VERSION 5.8 ;
BUSBITCHARS "[]" ;
DIVIDERCHAR "/" ;
UNITS
    DATABASE MICRONS 1000 ;
END UNITS

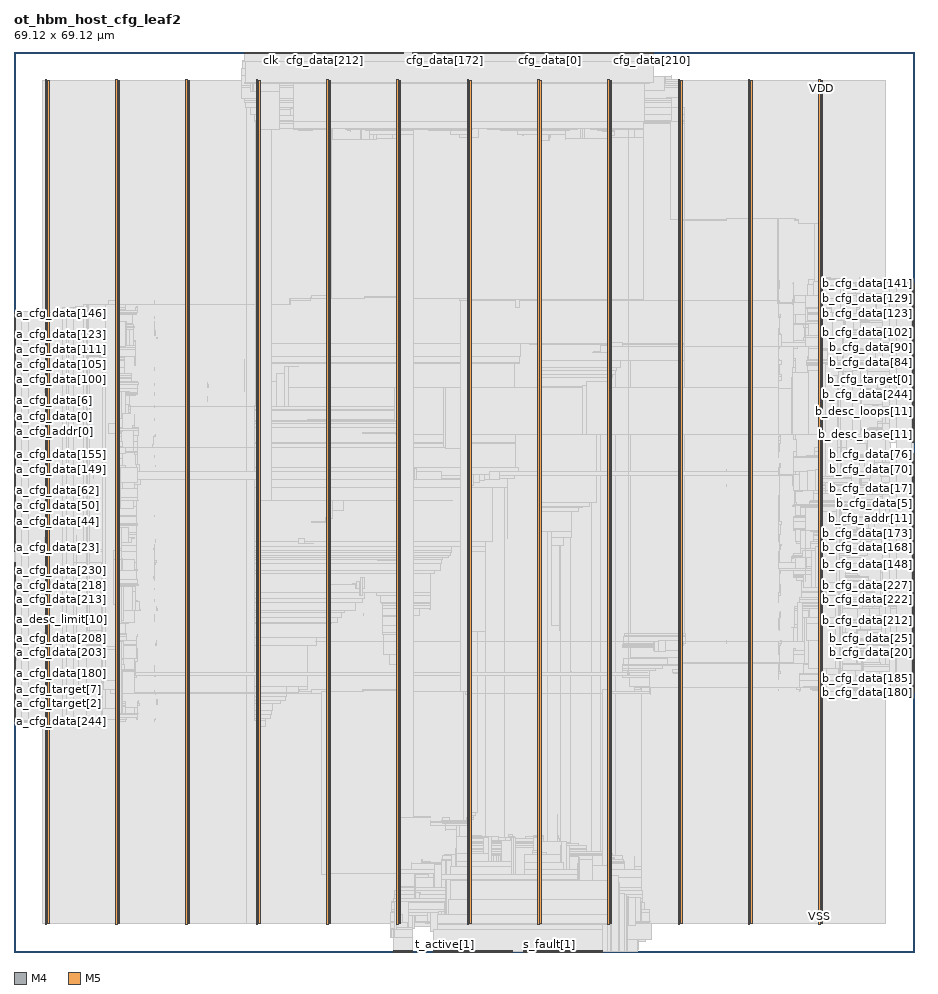
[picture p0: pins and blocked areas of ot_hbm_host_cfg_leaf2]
MACRO ot_hbm_host_cfg_leaf2
  FOREIGN ot_hbm_host_cfg_leaf2 0 0 ;
  CLASS BLOCK ;
  SIZE 69.12 BY 69.12 ;
  PIN a_cfg_addr[0]
    DIRECTION OUTPUT ;
    USE SIGNAL ;
    PORT
      LAYER M4 ;
        RECT  0 39.984 0.084 40.008 ;
    END
  END a_cfg_addr[0]
  PIN a_cfg_addr[10]
    DIRECTION OUTPUT ;
    USE SIGNAL ;
    PORT
      LAYER M4 ;
        RECT  0 40.944 0.084 40.968 ;
    END
  END a_cfg_addr[10]
  PIN a_cfg_addr[11]
    DIRECTION OUTPUT ;
    USE SIGNAL ;
    PORT
      LAYER M4 ;
        RECT  0 41.04 0.084 41.064 ;
    END
  END a_cfg_addr[11]
  PIN a_cfg_addr[1]
    DIRECTION OUTPUT ;
    USE SIGNAL ;
    PORT
      LAYER M4 ;
        RECT  0 40.08 0.084 40.104 ;
    END
  END a_cfg_addr[1]
  PIN a_cfg_addr[2]
    DIRECTION OUTPUT ;
    USE SIGNAL ;
    PORT
      LAYER M4 ;
        RECT  0 40.176 0.084 40.2 ;
    END
  END a_cfg_addr[2]
  PIN a_cfg_addr[3]
    DIRECTION OUTPUT ;
    USE SIGNAL ;
    PORT
      LAYER M4 ;
        RECT  0 40.272 0.084 40.296 ;
    END
  END a_cfg_addr[3]
  PIN a_cfg_addr[4]
    DIRECTION OUTPUT ;
    USE SIGNAL ;
    PORT
      LAYER M4 ;
        RECT  0 40.368 0.084 40.392 ;
    END
  END a_cfg_addr[4]
  PIN a_cfg_addr[5]
    DIRECTION OUTPUT ;
    USE SIGNAL ;
    PORT
      LAYER M4 ;
        RECT  0 40.464 0.084 40.488 ;
    END
  END a_cfg_addr[5]
  PIN a_cfg_addr[6]
    DIRECTION OUTPUT ;
    USE SIGNAL ;
    PORT
      LAYER M4 ;
        RECT  0 40.56 0.084 40.584 ;
    END
  END a_cfg_addr[6]
  PIN a_cfg_addr[7]
    DIRECTION OUTPUT ;
    USE SIGNAL ;
    PORT
      LAYER M4 ;
        RECT  0 40.656 0.084 40.68 ;
    END
  END a_cfg_addr[7]
  PIN a_cfg_addr[8]
    DIRECTION OUTPUT ;
    USE SIGNAL ;
    PORT
      LAYER M4 ;
        RECT  0 40.752 0.084 40.776 ;
    END
  END a_cfg_addr[8]
  PIN a_cfg_addr[9]
    DIRECTION OUTPUT ;
    USE SIGNAL ;
    PORT
      LAYER M4 ;
        RECT  0 40.848 0.084 40.872 ;
    END
  END a_cfg_addr[9]
  PIN a_cfg_data[0]
    DIRECTION OUTPUT ;
    USE SIGNAL ;
    PORT
      LAYER M4 ;
        RECT  0 41.136 0.084 41.16 ;
    END
  END a_cfg_data[0]
  PIN a_cfg_data[100]
    DIRECTION OUTPUT ;
    USE SIGNAL ;
    PORT
      LAYER M4 ;
        RECT  0 44.592 0.084 44.616 ;
    END
  END a_cfg_data[100]
  PIN a_cfg_data[101]
    DIRECTION OUTPUT ;
    USE SIGNAL ;
    PORT
      LAYER M4 ;
        RECT  0 44.688 0.084 44.712 ;
    END
  END a_cfg_data[101]
  PIN a_cfg_data[102]
    DIRECTION OUTPUT ;
    USE SIGNAL ;
    PORT
      LAYER M4 ;
        RECT  0 44.784 0.084 44.808 ;
    END
  END a_cfg_data[102]
  PIN a_cfg_data[103]
    DIRECTION OUTPUT ;
    USE SIGNAL ;
    PORT
      LAYER M4 ;
        RECT  0 44.88 0.084 44.904 ;
    END
  END a_cfg_data[103]
  PIN a_cfg_data[104]
    DIRECTION OUTPUT ;
    USE SIGNAL ;
    PORT
      LAYER M4 ;
        RECT  0 44.976 0.084 45 ;
    END
  END a_cfg_data[104]
  PIN a_cfg_data[105]
    DIRECTION OUTPUT ;
    USE SIGNAL ;
    PORT
      LAYER M4 ;
        RECT  0 45.072 0.084 45.096 ;
    END
  END a_cfg_data[105]
  PIN a_cfg_data[106]
    DIRECTION OUTPUT ;
    USE SIGNAL ;
    PORT
      LAYER M4 ;
        RECT  0 45.168 0.084 45.192 ;
    END
  END a_cfg_data[106]
  PIN a_cfg_data[107]
    DIRECTION OUTPUT ;
    USE SIGNAL ;
    PORT
      LAYER M4 ;
        RECT  0 45.264 0.084 45.288 ;
    END
  END a_cfg_data[107]
  PIN a_cfg_data[108]
    DIRECTION OUTPUT ;
    USE SIGNAL ;
    PORT
      LAYER M4 ;
        RECT  0 45.36 0.084 45.384 ;
    END
  END a_cfg_data[108]
  PIN a_cfg_data[109]
    DIRECTION OUTPUT ;
    USE SIGNAL ;
    PORT
      LAYER M4 ;
        RECT  0 45.456 0.084 45.48 ;
    END
  END a_cfg_data[109]
  PIN a_cfg_data[10]
    DIRECTION OUTPUT ;
    USE SIGNAL ;
    PORT
      LAYER M4 ;
        RECT  0 42.096 0.084 42.12 ;
    END
  END a_cfg_data[10]
  PIN a_cfg_data[110]
    DIRECTION OUTPUT ;
    USE SIGNAL ;
    PORT
      LAYER M4 ;
        RECT  0 45.552 0.084 45.576 ;
    END
  END a_cfg_data[110]
  PIN a_cfg_data[111]
    DIRECTION OUTPUT ;
    USE SIGNAL ;
    PORT
      LAYER M4 ;
        RECT  0 45.648 0.084 45.672 ;
    END
  END a_cfg_data[111]
  PIN a_cfg_data[112]
    DIRECTION OUTPUT ;
    USE SIGNAL ;
    PORT
      LAYER M4 ;
        RECT  0 45.744 0.084 45.768 ;
    END
  END a_cfg_data[112]
  PIN a_cfg_data[113]
    DIRECTION OUTPUT ;
    USE SIGNAL ;
    PORT
      LAYER M4 ;
        RECT  0 45.84 0.084 45.864 ;
    END
  END a_cfg_data[113]
  PIN a_cfg_data[114]
    DIRECTION OUTPUT ;
    USE SIGNAL ;
    PORT
      LAYER M4 ;
        RECT  0 45.936 0.084 45.96 ;
    END
  END a_cfg_data[114]
  PIN a_cfg_data[115]
    DIRECTION OUTPUT ;
    USE SIGNAL ;
    PORT
      LAYER M4 ;
        RECT  0 46.032 0.084 46.056 ;
    END
  END a_cfg_data[115]
  PIN a_cfg_data[116]
    DIRECTION OUTPUT ;
    USE SIGNAL ;
    PORT
      LAYER M4 ;
        RECT  0 46.128 0.084 46.152 ;
    END
  END a_cfg_data[116]
  PIN a_cfg_data[117]
    DIRECTION OUTPUT ;
    USE SIGNAL ;
    PORT
      LAYER M4 ;
        RECT  0 46.224 0.084 46.248 ;
    END
  END a_cfg_data[117]
  PIN a_cfg_data[118]
    DIRECTION OUTPUT ;
    USE SIGNAL ;
    PORT
      LAYER M4 ;
        RECT  0 46.32 0.084 46.344 ;
    END
  END a_cfg_data[118]
  PIN a_cfg_data[119]
    DIRECTION OUTPUT ;
    USE SIGNAL ;
    PORT
      LAYER M4 ;
        RECT  0 46.416 0.084 46.44 ;
    END
  END a_cfg_data[119]
  PIN a_cfg_data[11]
    DIRECTION OUTPUT ;
    USE SIGNAL ;
    PORT
      LAYER M4 ;
        RECT  0 42.192 0.084 42.216 ;
    END
  END a_cfg_data[11]
  PIN a_cfg_data[120]
    DIRECTION OUTPUT ;
    USE SIGNAL ;
    PORT
      LAYER M4 ;
        RECT  0 46.512 0.084 46.536 ;
    END
  END a_cfg_data[120]
  PIN a_cfg_data[121]
    DIRECTION OUTPUT ;
    USE SIGNAL ;
    PORT
      LAYER M4 ;
        RECT  0 46.608 0.084 46.632 ;
    END
  END a_cfg_data[121]
  PIN a_cfg_data[122]
    DIRECTION OUTPUT ;
    USE SIGNAL ;
    PORT
      LAYER M4 ;
        RECT  0 46.704 0.084 46.728 ;
    END
  END a_cfg_data[122]
  PIN a_cfg_data[123]
    DIRECTION OUTPUT ;
    USE SIGNAL ;
    PORT
      LAYER M4 ;
        RECT  0 46.8 0.084 46.824 ;
    END
  END a_cfg_data[123]
  PIN a_cfg_data[124]
    DIRECTION OUTPUT ;
    USE SIGNAL ;
    PORT
      LAYER M4 ;
        RECT  0 46.896 0.084 46.92 ;
    END
  END a_cfg_data[124]
  PIN a_cfg_data[125]
    DIRECTION OUTPUT ;
    USE SIGNAL ;
    PORT
      LAYER M4 ;
        RECT  0 46.992 0.084 47.016 ;
    END
  END a_cfg_data[125]
  PIN a_cfg_data[126]
    DIRECTION OUTPUT ;
    USE SIGNAL ;
    PORT
      LAYER M4 ;
        RECT  0 47.088 0.084 47.112 ;
    END
  END a_cfg_data[126]
  PIN a_cfg_data[127]
    DIRECTION OUTPUT ;
    USE SIGNAL ;
    PORT
      LAYER M4 ;
        RECT  0 47.184 0.084 47.208 ;
    END
  END a_cfg_data[127]
  PIN a_cfg_data[128]
    DIRECTION OUTPUT ;
    USE SIGNAL ;
    PORT
      LAYER M4 ;
        RECT  0 47.28 0.084 47.304 ;
    END
  END a_cfg_data[128]
  PIN a_cfg_data[129]
    DIRECTION OUTPUT ;
    USE SIGNAL ;
    PORT
      LAYER M4 ;
        RECT  0 47.376 0.084 47.4 ;
    END
  END a_cfg_data[129]
  PIN a_cfg_data[12]
    DIRECTION OUTPUT ;
    USE SIGNAL ;
    PORT
      LAYER M4 ;
        RECT  0 42.288 0.084 42.312 ;
    END
  END a_cfg_data[12]
  PIN a_cfg_data[130]
    DIRECTION OUTPUT ;
    USE SIGNAL ;
    PORT
      LAYER M4 ;
        RECT  0 47.472 0.084 47.496 ;
    END
  END a_cfg_data[130]
  PIN a_cfg_data[131]
    DIRECTION OUTPUT ;
    USE SIGNAL ;
    PORT
      LAYER M4 ;
        RECT  0 47.568 0.084 47.592 ;
    END
  END a_cfg_data[131]
  PIN a_cfg_data[132]
    DIRECTION OUTPUT ;
    USE SIGNAL ;
    PORT
      LAYER M4 ;
        RECT  0 47.664 0.084 47.688 ;
    END
  END a_cfg_data[132]
  PIN a_cfg_data[133]
    DIRECTION OUTPUT ;
    USE SIGNAL ;
    PORT
      LAYER M4 ;
        RECT  0 47.76 0.084 47.784 ;
    END
  END a_cfg_data[133]
  PIN a_cfg_data[134]
    DIRECTION OUTPUT ;
    USE SIGNAL ;
    PORT
      LAYER M4 ;
        RECT  0 47.856 0.084 47.88 ;
    END
  END a_cfg_data[134]
  PIN a_cfg_data[135]
    DIRECTION OUTPUT ;
    USE SIGNAL ;
    PORT
      LAYER M4 ;
        RECT  0 47.952 0.084 47.976 ;
    END
  END a_cfg_data[135]
  PIN a_cfg_data[136]
    DIRECTION OUTPUT ;
    USE SIGNAL ;
    PORT
      LAYER M4 ;
        RECT  0 48.048 0.084 48.072 ;
    END
  END a_cfg_data[136]
  PIN a_cfg_data[137]
    DIRECTION OUTPUT ;
    USE SIGNAL ;
    PORT
      LAYER M4 ;
        RECT  0 48.144 0.084 48.168 ;
    END
  END a_cfg_data[137]
  PIN a_cfg_data[138]
    DIRECTION OUTPUT ;
    USE SIGNAL ;
    PORT
      LAYER M4 ;
        RECT  0 48.24 0.084 48.264 ;
    END
  END a_cfg_data[138]
  PIN a_cfg_data[139]
    DIRECTION OUTPUT ;
    USE SIGNAL ;
    PORT
      LAYER M4 ;
        RECT  0 48.336 0.084 48.36 ;
    END
  END a_cfg_data[139]
  PIN a_cfg_data[13]
    DIRECTION OUTPUT ;
    USE SIGNAL ;
    PORT
      LAYER M4 ;
        RECT  0 42.384 0.084 42.408 ;
    END
  END a_cfg_data[13]
  PIN a_cfg_data[140]
    DIRECTION OUTPUT ;
    USE SIGNAL ;
    PORT
      LAYER M4 ;
        RECT  0 48.432 0.084 48.456 ;
    END
  END a_cfg_data[140]
  PIN a_cfg_data[141]
    DIRECTION OUTPUT ;
    USE SIGNAL ;
    PORT
      LAYER M4 ;
        RECT  0 48.528 0.084 48.552 ;
    END
  END a_cfg_data[141]
  PIN a_cfg_data[142]
    DIRECTION OUTPUT ;
    USE SIGNAL ;
    PORT
      LAYER M4 ;
        RECT  0 48.624 0.084 48.648 ;
    END
  END a_cfg_data[142]
  PIN a_cfg_data[143]
    DIRECTION OUTPUT ;
    USE SIGNAL ;
    PORT
      LAYER M4 ;
        RECT  0 48.72 0.084 48.744 ;
    END
  END a_cfg_data[143]
  PIN a_cfg_data[144]
    DIRECTION OUTPUT ;
    USE SIGNAL ;
    PORT
      LAYER M4 ;
        RECT  0 48.816 0.084 48.84 ;
    END
  END a_cfg_data[144]
  PIN a_cfg_data[145]
    DIRECTION OUTPUT ;
    USE SIGNAL ;
    PORT
      LAYER M4 ;
        RECT  0 48.912 0.084 48.936 ;
    END
  END a_cfg_data[145]
  PIN a_cfg_data[146]
    DIRECTION OUTPUT ;
    USE SIGNAL ;
    PORT
      LAYER M4 ;
        RECT  0 49.008 0.084 49.032 ;
    END
  END a_cfg_data[146]
  PIN a_cfg_data[147]
    DIRECTION OUTPUT ;
    USE SIGNAL ;
    PORT
      LAYER M4 ;
        RECT  0 49.104 0.084 49.128 ;
    END
  END a_cfg_data[147]
  PIN a_cfg_data[148]
    DIRECTION OUTPUT ;
    USE SIGNAL ;
    PORT
      LAYER M4 ;
        RECT  0 36.912 0.084 36.936 ;
    END
  END a_cfg_data[148]
  PIN a_cfg_data[149]
    DIRECTION OUTPUT ;
    USE SIGNAL ;
    PORT
      LAYER M4 ;
        RECT  0 37.008 0.084 37.032 ;
    END
  END a_cfg_data[149]
  PIN a_cfg_data[14]
    DIRECTION OUTPUT ;
    USE SIGNAL ;
    PORT
      LAYER M4 ;
        RECT  0 42.48 0.084 42.504 ;
    END
  END a_cfg_data[14]
  PIN a_cfg_data[150]
    DIRECTION OUTPUT ;
    USE SIGNAL ;
    PORT
      LAYER M4 ;
        RECT  0 37.104 0.084 37.128 ;
    END
  END a_cfg_data[150]
  PIN a_cfg_data[151]
    DIRECTION OUTPUT ;
    USE SIGNAL ;
    PORT
      LAYER M4 ;
        RECT  0 37.2 0.084 37.224 ;
    END
  END a_cfg_data[151]
  PIN a_cfg_data[152]
    DIRECTION OUTPUT ;
    USE SIGNAL ;
    PORT
      LAYER M4 ;
        RECT  0 37.296 0.084 37.32 ;
    END
  END a_cfg_data[152]
  PIN a_cfg_data[153]
    DIRECTION OUTPUT ;
    USE SIGNAL ;
    PORT
      LAYER M4 ;
        RECT  0 37.392 0.084 37.416 ;
    END
  END a_cfg_data[153]
  PIN a_cfg_data[154]
    DIRECTION OUTPUT ;
    USE SIGNAL ;
    PORT
      LAYER M4 ;
        RECT  0 37.488 0.084 37.512 ;
    END
  END a_cfg_data[154]
  PIN a_cfg_data[155]
    DIRECTION OUTPUT ;
    USE SIGNAL ;
    PORT
      LAYER M4 ;
        RECT  0 37.584 0.084 37.608 ;
    END
  END a_cfg_data[155]
  PIN a_cfg_data[156]
    DIRECTION OUTPUT ;
    USE SIGNAL ;
    PORT
      LAYER M4 ;
        RECT  0 37.68 0.084 37.704 ;
    END
  END a_cfg_data[156]
  PIN a_cfg_data[157]
    DIRECTION OUTPUT ;
    USE SIGNAL ;
    PORT
      LAYER M4 ;
        RECT  0 37.776 0.084 37.8 ;
    END
  END a_cfg_data[157]
  PIN a_cfg_data[158]
    DIRECTION OUTPUT ;
    USE SIGNAL ;
    PORT
      LAYER M4 ;
        RECT  0 37.872 0.084 37.896 ;
    END
  END a_cfg_data[158]
  PIN a_cfg_data[159]
    DIRECTION OUTPUT ;
    USE SIGNAL ;
    PORT
      LAYER M4 ;
        RECT  0 37.968 0.084 37.992 ;
    END
  END a_cfg_data[159]
  PIN a_cfg_data[15]
    DIRECTION OUTPUT ;
    USE SIGNAL ;
    PORT
      LAYER M4 ;
        RECT  0 42.576 0.084 42.6 ;
    END
  END a_cfg_data[15]
  PIN a_cfg_data[160]
    DIRECTION OUTPUT ;
    USE SIGNAL ;
    PORT
      LAYER M4 ;
        RECT  0 38.064 0.084 38.088 ;
    END
  END a_cfg_data[160]
  PIN a_cfg_data[161]
    DIRECTION OUTPUT ;
    USE SIGNAL ;
    PORT
      LAYER M4 ;
        RECT  0 38.16 0.084 38.184 ;
    END
  END a_cfg_data[161]
  PIN a_cfg_data[162]
    DIRECTION OUTPUT ;
    USE SIGNAL ;
    PORT
      LAYER M4 ;
        RECT  0 38.256 0.084 38.28 ;
    END
  END a_cfg_data[162]
  PIN a_cfg_data[163]
    DIRECTION OUTPUT ;
    USE SIGNAL ;
    PORT
      LAYER M4 ;
        RECT  0 38.352 0.084 38.376 ;
    END
  END a_cfg_data[163]
  PIN a_cfg_data[164]
    DIRECTION OUTPUT ;
    USE SIGNAL ;
    PORT
      LAYER M4 ;
        RECT  0 38.448 0.084 38.472 ;
    END
  END a_cfg_data[164]
  PIN a_cfg_data[165]
    DIRECTION OUTPUT ;
    USE SIGNAL ;
    PORT
      LAYER M4 ;
        RECT  0 38.544 0.084 38.568 ;
    END
  END a_cfg_data[165]
  PIN a_cfg_data[166]
    DIRECTION OUTPUT ;
    USE SIGNAL ;
    PORT
      LAYER M4 ;
        RECT  0 38.64 0.084 38.664 ;
    END
  END a_cfg_data[166]
  PIN a_cfg_data[167]
    DIRECTION OUTPUT ;
    USE SIGNAL ;
    PORT
      LAYER M4 ;
        RECT  0 38.736 0.084 38.76 ;
    END
  END a_cfg_data[167]
  PIN a_cfg_data[168]
    DIRECTION OUTPUT ;
    USE SIGNAL ;
    PORT
      LAYER M4 ;
        RECT  0 38.832 0.084 38.856 ;
    END
  END a_cfg_data[168]
  PIN a_cfg_data[169]
    DIRECTION OUTPUT ;
    USE SIGNAL ;
    PORT
      LAYER M4 ;
        RECT  0 38.928 0.084 38.952 ;
    END
  END a_cfg_data[169]
  PIN a_cfg_data[16]
    DIRECTION OUTPUT ;
    USE SIGNAL ;
    PORT
      LAYER M4 ;
        RECT  0 42.672 0.084 42.696 ;
    END
  END a_cfg_data[16]
  PIN a_cfg_data[170]
    DIRECTION OUTPUT ;
    USE SIGNAL ;
    PORT
      LAYER M4 ;
        RECT  0 39.024 0.084 39.048 ;
    END
  END a_cfg_data[170]
  PIN a_cfg_data[171]
    DIRECTION OUTPUT ;
    USE SIGNAL ;
    PORT
      LAYER M4 ;
        RECT  0 39.12 0.084 39.144 ;
    END
  END a_cfg_data[171]
  PIN a_cfg_data[172]
    DIRECTION OUTPUT ;
    USE SIGNAL ;
    PORT
      LAYER M4 ;
        RECT  0 39.216 0.084 39.24 ;
    END
  END a_cfg_data[172]
  PIN a_cfg_data[173]
    DIRECTION OUTPUT ;
    USE SIGNAL ;
    PORT
      LAYER M4 ;
        RECT  0 39.312 0.084 39.336 ;
    END
  END a_cfg_data[173]
  PIN a_cfg_data[174]
    DIRECTION OUTPUT ;
    USE SIGNAL ;
    PORT
      LAYER M4 ;
        RECT  0 39.408 0.084 39.432 ;
    END
  END a_cfg_data[174]
  PIN a_cfg_data[175]
    DIRECTION OUTPUT ;
    USE SIGNAL ;
    PORT
      LAYER M4 ;
        RECT  0 39.504 0.084 39.528 ;
    END
  END a_cfg_data[175]
  PIN a_cfg_data[176]
    DIRECTION OUTPUT ;
    USE SIGNAL ;
    PORT
      LAYER M4 ;
        RECT  0 39.6 0.084 39.624 ;
    END
  END a_cfg_data[176]
  PIN a_cfg_data[177]
    DIRECTION OUTPUT ;
    USE SIGNAL ;
    PORT
      LAYER M4 ;
        RECT  0 39.696 0.084 39.72 ;
    END
  END a_cfg_data[177]
  PIN a_cfg_data[178]
    DIRECTION OUTPUT ;
    USE SIGNAL ;
    PORT
      LAYER M4 ;
        RECT  0 39.792 0.084 39.816 ;
    END
  END a_cfg_data[178]
  PIN a_cfg_data[179]
    DIRECTION OUTPUT ;
    USE SIGNAL ;
    PORT
      LAYER M4 ;
        RECT  0 39.888 0.084 39.912 ;
    END
  END a_cfg_data[179]
  PIN a_cfg_data[17]
    DIRECTION OUTPUT ;
    USE SIGNAL ;
    PORT
      LAYER M4 ;
        RECT  0 42.768 0.084 42.792 ;
    END
  END a_cfg_data[17]
  PIN a_cfg_data[180]
    DIRECTION OUTPUT ;
    USE SIGNAL ;
    PORT
      LAYER M4 ;
        RECT  0 20.784 0.084 20.808 ;
    END
  END a_cfg_data[180]
  PIN a_cfg_data[181]
    DIRECTION OUTPUT ;
    USE SIGNAL ;
    PORT
      LAYER M4 ;
        RECT  0 20.88 0.084 20.904 ;
    END
  END a_cfg_data[181]
  PIN a_cfg_data[182]
    DIRECTION OUTPUT ;
    USE SIGNAL ;
    PORT
      LAYER M4 ;
        RECT  0 20.976 0.084 21 ;
    END
  END a_cfg_data[182]
  PIN a_cfg_data[183]
    DIRECTION OUTPUT ;
    USE SIGNAL ;
    PORT
      LAYER M4 ;
        RECT  0 21.072 0.084 21.096 ;
    END
  END a_cfg_data[183]
  PIN a_cfg_data[184]
    DIRECTION OUTPUT ;
    USE SIGNAL ;
    PORT
      LAYER M4 ;
        RECT  0 21.168 0.084 21.192 ;
    END
  END a_cfg_data[184]
  PIN a_cfg_data[185]
    DIRECTION OUTPUT ;
    USE SIGNAL ;
    PORT
      LAYER M4 ;
        RECT  0 21.264 0.084 21.288 ;
    END
  END a_cfg_data[185]
  PIN a_cfg_data[186]
    DIRECTION OUTPUT ;
    USE SIGNAL ;
    PORT
      LAYER M4 ;
        RECT  0 21.36 0.084 21.384 ;
    END
  END a_cfg_data[186]
  PIN a_cfg_data[187]
    DIRECTION OUTPUT ;
    USE SIGNAL ;
    PORT
      LAYER M4 ;
        RECT  0 21.456 0.084 21.48 ;
    END
  END a_cfg_data[187]
  PIN a_cfg_data[188]
    DIRECTION OUTPUT ;
    USE SIGNAL ;
    PORT
      LAYER M4 ;
        RECT  0 21.552 0.084 21.576 ;
    END
  END a_cfg_data[188]
  PIN a_cfg_data[189]
    DIRECTION OUTPUT ;
    USE SIGNAL ;
    PORT
      LAYER M4 ;
        RECT  0 21.648 0.084 21.672 ;
    END
  END a_cfg_data[189]
  PIN a_cfg_data[18]
    DIRECTION OUTPUT ;
    USE SIGNAL ;
    PORT
      LAYER M4 ;
        RECT  0 42.864 0.084 42.888 ;
    END
  END a_cfg_data[18]
  PIN a_cfg_data[190]
    DIRECTION OUTPUT ;
    USE SIGNAL ;
    PORT
      LAYER M4 ;
        RECT  0 21.744 0.084 21.768 ;
    END
  END a_cfg_data[190]
  PIN a_cfg_data[191]
    DIRECTION OUTPUT ;
    USE SIGNAL ;
    PORT
      LAYER M4 ;
        RECT  0 21.84 0.084 21.864 ;
    END
  END a_cfg_data[191]
  PIN a_cfg_data[192]
    DIRECTION OUTPUT ;
    USE SIGNAL ;
    PORT
      LAYER M4 ;
        RECT  0 21.936 0.084 21.96 ;
    END
  END a_cfg_data[192]
  PIN a_cfg_data[193]
    DIRECTION OUTPUT ;
    USE SIGNAL ;
    PORT
      LAYER M4 ;
        RECT  0 22.032 0.084 22.056 ;
    END
  END a_cfg_data[193]
  PIN a_cfg_data[194]
    DIRECTION OUTPUT ;
    USE SIGNAL ;
    PORT
      LAYER M4 ;
        RECT  0 22.128 0.084 22.152 ;
    END
  END a_cfg_data[194]
  PIN a_cfg_data[195]
    DIRECTION OUTPUT ;
    USE SIGNAL ;
    PORT
      LAYER M4 ;
        RECT  0 22.224 0.084 22.248 ;
    END
  END a_cfg_data[195]
  PIN a_cfg_data[196]
    DIRECTION OUTPUT ;
    USE SIGNAL ;
    PORT
      LAYER M4 ;
        RECT  0 22.32 0.084 22.344 ;
    END
  END a_cfg_data[196]
  PIN a_cfg_data[197]
    DIRECTION OUTPUT ;
    USE SIGNAL ;
    PORT
      LAYER M4 ;
        RECT  0 22.416 0.084 22.44 ;
    END
  END a_cfg_data[197]
  PIN a_cfg_data[198]
    DIRECTION OUTPUT ;
    USE SIGNAL ;
    PORT
      LAYER M4 ;
        RECT  0 22.512 0.084 22.536 ;
    END
  END a_cfg_data[198]
  PIN a_cfg_data[199]
    DIRECTION OUTPUT ;
    USE SIGNAL ;
    PORT
      LAYER M4 ;
        RECT  0 22.608 0.084 22.632 ;
    END
  END a_cfg_data[199]
  PIN a_cfg_data[19]
    DIRECTION OUTPUT ;
    USE SIGNAL ;
    PORT
      LAYER M4 ;
        RECT  0 42.96 0.084 42.984 ;
    END
  END a_cfg_data[19]
  PIN a_cfg_data[1]
    DIRECTION OUTPUT ;
    USE SIGNAL ;
    PORT
      LAYER M4 ;
        RECT  0 41.232 0.084 41.256 ;
    END
  END a_cfg_data[1]
  PIN a_cfg_data[200]
    DIRECTION OUTPUT ;
    USE SIGNAL ;
    PORT
      LAYER M4 ;
        RECT  0 22.704 0.084 22.728 ;
    END
  END a_cfg_data[200]
  PIN a_cfg_data[201]
    DIRECTION OUTPUT ;
    USE SIGNAL ;
    PORT
      LAYER M4 ;
        RECT  0 22.8 0.084 22.824 ;
    END
  END a_cfg_data[201]
  PIN a_cfg_data[202]
    DIRECTION OUTPUT ;
    USE SIGNAL ;
    PORT
      LAYER M4 ;
        RECT  0 22.896 0.084 22.92 ;
    END
  END a_cfg_data[202]
  PIN a_cfg_data[203]
    DIRECTION OUTPUT ;
    USE SIGNAL ;
    PORT
      LAYER M4 ;
        RECT  0 22.992 0.084 23.016 ;
    END
  END a_cfg_data[203]
  PIN a_cfg_data[204]
    DIRECTION OUTPUT ;
    USE SIGNAL ;
    PORT
      LAYER M4 ;
        RECT  0 23.088 0.084 23.112 ;
    END
  END a_cfg_data[204]
  PIN a_cfg_data[205]
    DIRECTION OUTPUT ;
    USE SIGNAL ;
    PORT
      LAYER M4 ;
        RECT  0 23.184 0.084 23.208 ;
    END
  END a_cfg_data[205]
  PIN a_cfg_data[206]
    DIRECTION OUTPUT ;
    USE SIGNAL ;
    PORT
      LAYER M4 ;
        RECT  0 23.28 0.084 23.304 ;
    END
  END a_cfg_data[206]
  PIN a_cfg_data[207]
    DIRECTION OUTPUT ;
    USE SIGNAL ;
    PORT
      LAYER M4 ;
        RECT  0 23.376 0.084 23.4 ;
    END
  END a_cfg_data[207]
  PIN a_cfg_data[208]
    DIRECTION OUTPUT ;
    USE SIGNAL ;
    PORT
      LAYER M4 ;
        RECT  0 23.472 0.084 23.496 ;
    END
  END a_cfg_data[208]
  PIN a_cfg_data[209]
    DIRECTION OUTPUT ;
    USE SIGNAL ;
    PORT
      LAYER M4 ;
        RECT  0 23.568 0.084 23.592 ;
    END
  END a_cfg_data[209]
  PIN a_cfg_data[20]
    DIRECTION OUTPUT ;
    USE SIGNAL ;
    PORT
      LAYER M4 ;
        RECT  0 30.768 0.084 30.792 ;
    END
  END a_cfg_data[20]
  PIN a_cfg_data[210]
    DIRECTION OUTPUT ;
    USE SIGNAL ;
    PORT
      LAYER M4 ;
        RECT  0 23.664 0.084 23.688 ;
    END
  END a_cfg_data[210]
  PIN a_cfg_data[211]
    DIRECTION OUTPUT ;
    USE SIGNAL ;
    PORT
      LAYER M4 ;
        RECT  0 23.76 0.084 23.784 ;
    END
  END a_cfg_data[211]
  PIN a_cfg_data[212]
    DIRECTION OUTPUT ;
    USE SIGNAL ;
    PORT
      LAYER M4 ;
        RECT  0 26.928 0.084 26.952 ;
    END
  END a_cfg_data[212]
  PIN a_cfg_data[213]
    DIRECTION OUTPUT ;
    USE SIGNAL ;
    PORT
      LAYER M4 ;
        RECT  0 27.024 0.084 27.048 ;
    END
  END a_cfg_data[213]
  PIN a_cfg_data[214]
    DIRECTION OUTPUT ;
    USE SIGNAL ;
    PORT
      LAYER M4 ;
        RECT  0 27.12 0.084 27.144 ;
    END
  END a_cfg_data[214]
  PIN a_cfg_data[215]
    DIRECTION OUTPUT ;
    USE SIGNAL ;
    PORT
      LAYER M4 ;
        RECT  0 27.216 0.084 27.24 ;
    END
  END a_cfg_data[215]
  PIN a_cfg_data[216]
    DIRECTION OUTPUT ;
    USE SIGNAL ;
    PORT
      LAYER M4 ;
        RECT  0 27.312 0.084 27.336 ;
    END
  END a_cfg_data[216]
  PIN a_cfg_data[217]
    DIRECTION OUTPUT ;
    USE SIGNAL ;
    PORT
      LAYER M4 ;
        RECT  0 27.408 0.084 27.432 ;
    END
  END a_cfg_data[217]
  PIN a_cfg_data[218]
    DIRECTION OUTPUT ;
    USE SIGNAL ;
    PORT
      LAYER M4 ;
        RECT  0 27.504 0.084 27.528 ;
    END
  END a_cfg_data[218]
  PIN a_cfg_data[219]
    DIRECTION OUTPUT ;
    USE SIGNAL ;
    PORT
      LAYER M4 ;
        RECT  0 27.6 0.084 27.624 ;
    END
  END a_cfg_data[219]
  PIN a_cfg_data[21]
    DIRECTION OUTPUT ;
    USE SIGNAL ;
    PORT
      LAYER M4 ;
        RECT  0 30.864 0.084 30.888 ;
    END
  END a_cfg_data[21]
  PIN a_cfg_data[220]
    DIRECTION OUTPUT ;
    USE SIGNAL ;
    PORT
      LAYER M4 ;
        RECT  0 27.696 0.084 27.72 ;
    END
  END a_cfg_data[220]
  PIN a_cfg_data[221]
    DIRECTION OUTPUT ;
    USE SIGNAL ;
    PORT
      LAYER M4 ;
        RECT  0 27.792 0.084 27.816 ;
    END
  END a_cfg_data[221]
  PIN a_cfg_data[222]
    DIRECTION OUTPUT ;
    USE SIGNAL ;
    PORT
      LAYER M4 ;
        RECT  0 27.888 0.084 27.912 ;
    END
  END a_cfg_data[222]
  PIN a_cfg_data[223]
    DIRECTION OUTPUT ;
    USE SIGNAL ;
    PORT
      LAYER M4 ;
        RECT  0 27.984 0.084 28.008 ;
    END
  END a_cfg_data[223]
  PIN a_cfg_data[224]
    DIRECTION OUTPUT ;
    USE SIGNAL ;
    PORT
      LAYER M4 ;
        RECT  0 28.08 0.084 28.104 ;
    END
  END a_cfg_data[224]
  PIN a_cfg_data[225]
    DIRECTION OUTPUT ;
    USE SIGNAL ;
    PORT
      LAYER M4 ;
        RECT  0 28.176 0.084 28.2 ;
    END
  END a_cfg_data[225]
  PIN a_cfg_data[226]
    DIRECTION OUTPUT ;
    USE SIGNAL ;
    PORT
      LAYER M4 ;
        RECT  0 28.272 0.084 28.296 ;
    END
  END a_cfg_data[226]
  PIN a_cfg_data[227]
    DIRECTION OUTPUT ;
    USE SIGNAL ;
    PORT
      LAYER M4 ;
        RECT  0 28.368 0.084 28.392 ;
    END
  END a_cfg_data[227]
  PIN a_cfg_data[228]
    DIRECTION OUTPUT ;
    USE SIGNAL ;
    PORT
      LAYER M4 ;
        RECT  0 28.464 0.084 28.488 ;
    END
  END a_cfg_data[228]
  PIN a_cfg_data[229]
    DIRECTION OUTPUT ;
    USE SIGNAL ;
    PORT
      LAYER M4 ;
        RECT  0 28.56 0.084 28.584 ;
    END
  END a_cfg_data[229]
  PIN a_cfg_data[22]
    DIRECTION OUTPUT ;
    USE SIGNAL ;
    PORT
      LAYER M4 ;
        RECT  0 30.96 0.084 30.984 ;
    END
  END a_cfg_data[22]
  PIN a_cfg_data[230]
    DIRECTION OUTPUT ;
    USE SIGNAL ;
    PORT
      LAYER M4 ;
        RECT  0 28.656 0.084 28.68 ;
    END
  END a_cfg_data[230]
  PIN a_cfg_data[231]
    DIRECTION OUTPUT ;
    USE SIGNAL ;
    PORT
      LAYER M4 ;
        RECT  0 28.752 0.084 28.776 ;
    END
  END a_cfg_data[231]
  PIN a_cfg_data[232]
    DIRECTION OUTPUT ;
    USE SIGNAL ;
    PORT
      LAYER M4 ;
        RECT  0 28.848 0.084 28.872 ;
    END
  END a_cfg_data[232]
  PIN a_cfg_data[233]
    DIRECTION OUTPUT ;
    USE SIGNAL ;
    PORT
      LAYER M4 ;
        RECT  0 28.944 0.084 28.968 ;
    END
  END a_cfg_data[233]
  PIN a_cfg_data[234]
    DIRECTION OUTPUT ;
    USE SIGNAL ;
    PORT
      LAYER M4 ;
        RECT  0 29.04 0.084 29.064 ;
    END
  END a_cfg_data[234]
  PIN a_cfg_data[235]
    DIRECTION OUTPUT ;
    USE SIGNAL ;
    PORT
      LAYER M4 ;
        RECT  0 29.136 0.084 29.16 ;
    END
  END a_cfg_data[235]
  PIN a_cfg_data[236]
    DIRECTION OUTPUT ;
    USE SIGNAL ;
    PORT
      LAYER M4 ;
        RECT  0 29.232 0.084 29.256 ;
    END
  END a_cfg_data[236]
  PIN a_cfg_data[237]
    DIRECTION OUTPUT ;
    USE SIGNAL ;
    PORT
      LAYER M4 ;
        RECT  0 29.328 0.084 29.352 ;
    END
  END a_cfg_data[237]
  PIN a_cfg_data[238]
    DIRECTION OUTPUT ;
    USE SIGNAL ;
    PORT
      LAYER M4 ;
        RECT  0 29.424 0.084 29.448 ;
    END
  END a_cfg_data[238]
  PIN a_cfg_data[239]
    DIRECTION OUTPUT ;
    USE SIGNAL ;
    PORT
      LAYER M4 ;
        RECT  0 29.52 0.084 29.544 ;
    END
  END a_cfg_data[239]
  PIN a_cfg_data[23]
    DIRECTION OUTPUT ;
    USE SIGNAL ;
    PORT
      LAYER M4 ;
        RECT  0 31.056 0.084 31.08 ;
    END
  END a_cfg_data[23]
  PIN a_cfg_data[240]
    DIRECTION OUTPUT ;
    USE SIGNAL ;
    PORT
      LAYER M4 ;
        RECT  0 29.616 0.084 29.64 ;
    END
  END a_cfg_data[240]
  PIN a_cfg_data[241]
    DIRECTION OUTPUT ;
    USE SIGNAL ;
    PORT
      LAYER M4 ;
        RECT  0 29.712 0.084 29.736 ;
    END
  END a_cfg_data[241]
  PIN a_cfg_data[242]
    DIRECTION OUTPUT ;
    USE SIGNAL ;
    PORT
      LAYER M4 ;
        RECT  0 29.808 0.084 29.832 ;
    END
  END a_cfg_data[242]
  PIN a_cfg_data[243]
    DIRECTION OUTPUT ;
    USE SIGNAL ;
    PORT
      LAYER M4 ;
        RECT  0 29.904 0.084 29.928 ;
    END
  END a_cfg_data[243]
  PIN a_cfg_data[244]
    DIRECTION OUTPUT ;
    USE SIGNAL ;
    PORT
      LAYER M4 ;
        RECT  0 17.712 0.084 17.736 ;
    END
  END a_cfg_data[244]
  PIN a_cfg_data[245]
    DIRECTION OUTPUT ;
    USE SIGNAL ;
    PORT
      LAYER M4 ;
        RECT  0 17.808 0.084 17.832 ;
    END
  END a_cfg_data[245]
  PIN a_cfg_data[246]
    DIRECTION OUTPUT ;
    USE SIGNAL ;
    PORT
      LAYER M4 ;
        RECT  0 17.904 0.084 17.928 ;
    END
  END a_cfg_data[246]
  PIN a_cfg_data[247]
    DIRECTION OUTPUT ;
    USE SIGNAL ;
    PORT
      LAYER M4 ;
        RECT  0 18 0.084 18.024 ;
    END
  END a_cfg_data[247]
  PIN a_cfg_data[248]
    DIRECTION OUTPUT ;
    USE SIGNAL ;
    PORT
      LAYER M4 ;
        RECT  0 18.096 0.084 18.12 ;
    END
  END a_cfg_data[248]
  PIN a_cfg_data[249]
    DIRECTION OUTPUT ;
    USE SIGNAL ;
    PORT
      LAYER M4 ;
        RECT  0 18.192 0.084 18.216 ;
    END
  END a_cfg_data[249]
  PIN a_cfg_data[24]
    DIRECTION OUTPUT ;
    USE SIGNAL ;
    PORT
      LAYER M4 ;
        RECT  0 31.152 0.084 31.176 ;
    END
  END a_cfg_data[24]
  PIN a_cfg_data[250]
    DIRECTION OUTPUT ;
    USE SIGNAL ;
    PORT
      LAYER M4 ;
        RECT  0 18.288 0.084 18.312 ;
    END
  END a_cfg_data[250]
  PIN a_cfg_data[251]
    DIRECTION OUTPUT ;
    USE SIGNAL ;
    PORT
      LAYER M4 ;
        RECT  0 18.384 0.084 18.408 ;
    END
  END a_cfg_data[251]
  PIN a_cfg_data[252]
    DIRECTION OUTPUT ;
    USE SIGNAL ;
    PORT
      LAYER M4 ;
        RECT  0 18.48 0.084 18.504 ;
    END
  END a_cfg_data[252]
  PIN a_cfg_data[253]
    DIRECTION OUTPUT ;
    USE SIGNAL ;
    PORT
      LAYER M4 ;
        RECT  0 18.576 0.084 18.6 ;
    END
  END a_cfg_data[253]
  PIN a_cfg_data[254]
    DIRECTION OUTPUT ;
    USE SIGNAL ;
    PORT
      LAYER M4 ;
        RECT  0 18.672 0.084 18.696 ;
    END
  END a_cfg_data[254]
  PIN a_cfg_data[255]
    DIRECTION OUTPUT ;
    USE SIGNAL ;
    PORT
      LAYER M4 ;
        RECT  0 18.768 0.084 18.792 ;
    END
  END a_cfg_data[255]
  PIN a_cfg_data[25]
    DIRECTION OUTPUT ;
    USE SIGNAL ;
    PORT
      LAYER M4 ;
        RECT  0 31.248 0.084 31.272 ;
    END
  END a_cfg_data[25]
  PIN a_cfg_data[26]
    DIRECTION OUTPUT ;
    USE SIGNAL ;
    PORT
      LAYER M4 ;
        RECT  0 31.344 0.084 31.368 ;
    END
  END a_cfg_data[26]
  PIN a_cfg_data[27]
    DIRECTION OUTPUT ;
    USE SIGNAL ;
    PORT
      LAYER M4 ;
        RECT  0 31.44 0.084 31.464 ;
    END
  END a_cfg_data[27]
  PIN a_cfg_data[28]
    DIRECTION OUTPUT ;
    USE SIGNAL ;
    PORT
      LAYER M4 ;
        RECT  0 31.536 0.084 31.56 ;
    END
  END a_cfg_data[28]
  PIN a_cfg_data[29]
    DIRECTION OUTPUT ;
    USE SIGNAL ;
    PORT
      LAYER M4 ;
        RECT  0 31.632 0.084 31.656 ;
    END
  END a_cfg_data[29]
  PIN a_cfg_data[2]
    DIRECTION OUTPUT ;
    USE SIGNAL ;
    PORT
      LAYER M4 ;
        RECT  0 41.328 0.084 41.352 ;
    END
  END a_cfg_data[2]
  PIN a_cfg_data[30]
    DIRECTION OUTPUT ;
    USE SIGNAL ;
    PORT
      LAYER M4 ;
        RECT  0 31.728 0.084 31.752 ;
    END
  END a_cfg_data[30]
  PIN a_cfg_data[31]
    DIRECTION OUTPUT ;
    USE SIGNAL ;
    PORT
      LAYER M4 ;
        RECT  0 31.824 0.084 31.848 ;
    END
  END a_cfg_data[31]
  PIN a_cfg_data[32]
    DIRECTION OUTPUT ;
    USE SIGNAL ;
    PORT
      LAYER M4 ;
        RECT  0 31.92 0.084 31.944 ;
    END
  END a_cfg_data[32]
  PIN a_cfg_data[33]
    DIRECTION OUTPUT ;
    USE SIGNAL ;
    PORT
      LAYER M4 ;
        RECT  0 32.016 0.084 32.04 ;
    END
  END a_cfg_data[33]
  PIN a_cfg_data[34]
    DIRECTION OUTPUT ;
    USE SIGNAL ;
    PORT
      LAYER M4 ;
        RECT  0 32.112 0.084 32.136 ;
    END
  END a_cfg_data[34]
  PIN a_cfg_data[35]
    DIRECTION OUTPUT ;
    USE SIGNAL ;
    PORT
      LAYER M4 ;
        RECT  0 32.208 0.084 32.232 ;
    END
  END a_cfg_data[35]
  PIN a_cfg_data[36]
    DIRECTION OUTPUT ;
    USE SIGNAL ;
    PORT
      LAYER M4 ;
        RECT  0 32.304 0.084 32.328 ;
    END
  END a_cfg_data[36]
  PIN a_cfg_data[37]
    DIRECTION OUTPUT ;
    USE SIGNAL ;
    PORT
      LAYER M4 ;
        RECT  0 32.4 0.084 32.424 ;
    END
  END a_cfg_data[37]
  PIN a_cfg_data[38]
    DIRECTION OUTPUT ;
    USE SIGNAL ;
    PORT
      LAYER M4 ;
        RECT  0 32.496 0.084 32.52 ;
    END
  END a_cfg_data[38]
  PIN a_cfg_data[39]
    DIRECTION OUTPUT ;
    USE SIGNAL ;
    PORT
      LAYER M4 ;
        RECT  0 32.592 0.084 32.616 ;
    END
  END a_cfg_data[39]
  PIN a_cfg_data[3]
    DIRECTION OUTPUT ;
    USE SIGNAL ;
    PORT
      LAYER M4 ;
        RECT  0 41.424 0.084 41.448 ;
    END
  END a_cfg_data[3]
  PIN a_cfg_data[40]
    DIRECTION OUTPUT ;
    USE SIGNAL ;
    PORT
      LAYER M4 ;
        RECT  0 32.688 0.084 32.712 ;
    END
  END a_cfg_data[40]
  PIN a_cfg_data[41]
    DIRECTION OUTPUT ;
    USE SIGNAL ;
    PORT
      LAYER M4 ;
        RECT  0 32.784 0.084 32.808 ;
    END
  END a_cfg_data[41]
  PIN a_cfg_data[42]
    DIRECTION OUTPUT ;
    USE SIGNAL ;
    PORT
      LAYER M4 ;
        RECT  0 32.88 0.084 32.904 ;
    END
  END a_cfg_data[42]
  PIN a_cfg_data[43]
    DIRECTION OUTPUT ;
    USE SIGNAL ;
    PORT
      LAYER M4 ;
        RECT  0 32.976 0.084 33 ;
    END
  END a_cfg_data[43]
  PIN a_cfg_data[44]
    DIRECTION OUTPUT ;
    USE SIGNAL ;
    PORT
      LAYER M4 ;
        RECT  0 33.072 0.084 33.096 ;
    END
  END a_cfg_data[44]
  PIN a_cfg_data[45]
    DIRECTION OUTPUT ;
    USE SIGNAL ;
    PORT
      LAYER M4 ;
        RECT  0 33.168 0.084 33.192 ;
    END
  END a_cfg_data[45]
  PIN a_cfg_data[46]
    DIRECTION OUTPUT ;
    USE SIGNAL ;
    PORT
      LAYER M4 ;
        RECT  0 33.264 0.084 33.288 ;
    END
  END a_cfg_data[46]
  PIN a_cfg_data[47]
    DIRECTION OUTPUT ;
    USE SIGNAL ;
    PORT
      LAYER M4 ;
        RECT  0 33.36 0.084 33.384 ;
    END
  END a_cfg_data[47]
  PIN a_cfg_data[48]
    DIRECTION OUTPUT ;
    USE SIGNAL ;
    PORT
      LAYER M4 ;
        RECT  0 33.456 0.084 33.48 ;
    END
  END a_cfg_data[48]
  PIN a_cfg_data[49]
    DIRECTION OUTPUT ;
    USE SIGNAL ;
    PORT
      LAYER M4 ;
        RECT  0 33.552 0.084 33.576 ;
    END
  END a_cfg_data[49]
  PIN a_cfg_data[4]
    DIRECTION OUTPUT ;
    USE SIGNAL ;
    PORT
      LAYER M4 ;
        RECT  0 41.52 0.084 41.544 ;
    END
  END a_cfg_data[4]
  PIN a_cfg_data[50]
    DIRECTION OUTPUT ;
    USE SIGNAL ;
    PORT
      LAYER M4 ;
        RECT  0 33.648 0.084 33.672 ;
    END
  END a_cfg_data[50]
  PIN a_cfg_data[51]
    DIRECTION OUTPUT ;
    USE SIGNAL ;
    PORT
      LAYER M4 ;
        RECT  0 33.744 0.084 33.768 ;
    END
  END a_cfg_data[51]
  PIN a_cfg_data[52]
    DIRECTION OUTPUT ;
    USE SIGNAL ;
    PORT
      LAYER M4 ;
        RECT  0 33.84 0.084 33.864 ;
    END
  END a_cfg_data[52]
  PIN a_cfg_data[53]
    DIRECTION OUTPUT ;
    USE SIGNAL ;
    PORT
      LAYER M4 ;
        RECT  0 33.936 0.084 33.96 ;
    END
  END a_cfg_data[53]
  PIN a_cfg_data[54]
    DIRECTION OUTPUT ;
    USE SIGNAL ;
    PORT
      LAYER M4 ;
        RECT  0 34.032 0.084 34.056 ;
    END
  END a_cfg_data[54]
  PIN a_cfg_data[55]
    DIRECTION OUTPUT ;
    USE SIGNAL ;
    PORT
      LAYER M4 ;
        RECT  0 34.128 0.084 34.152 ;
    END
  END a_cfg_data[55]
  PIN a_cfg_data[56]
    DIRECTION OUTPUT ;
    USE SIGNAL ;
    PORT
      LAYER M4 ;
        RECT  0 34.224 0.084 34.248 ;
    END
  END a_cfg_data[56]
  PIN a_cfg_data[57]
    DIRECTION OUTPUT ;
    USE SIGNAL ;
    PORT
      LAYER M4 ;
        RECT  0 34.32 0.084 34.344 ;
    END
  END a_cfg_data[57]
  PIN a_cfg_data[58]
    DIRECTION OUTPUT ;
    USE SIGNAL ;
    PORT
      LAYER M4 ;
        RECT  0 34.416 0.084 34.44 ;
    END
  END a_cfg_data[58]
  PIN a_cfg_data[59]
    DIRECTION OUTPUT ;
    USE SIGNAL ;
    PORT
      LAYER M4 ;
        RECT  0 34.512 0.084 34.536 ;
    END
  END a_cfg_data[59]
  PIN a_cfg_data[5]
    DIRECTION OUTPUT ;
    USE SIGNAL ;
    PORT
      LAYER M4 ;
        RECT  0 41.616 0.084 41.64 ;
    END
  END a_cfg_data[5]
  PIN a_cfg_data[60]
    DIRECTION OUTPUT ;
    USE SIGNAL ;
    PORT
      LAYER M4 ;
        RECT  0 34.608 0.084 34.632 ;
    END
  END a_cfg_data[60]
  PIN a_cfg_data[61]
    DIRECTION OUTPUT ;
    USE SIGNAL ;
    PORT
      LAYER M4 ;
        RECT  0 34.704 0.084 34.728 ;
    END
  END a_cfg_data[61]
  PIN a_cfg_data[62]
    DIRECTION OUTPUT ;
    USE SIGNAL ;
    PORT
      LAYER M4 ;
        RECT  0 34.8 0.084 34.824 ;
    END
  END a_cfg_data[62]
  PIN a_cfg_data[63]
    DIRECTION OUTPUT ;
    USE SIGNAL ;
    PORT
      LAYER M4 ;
        RECT  0 34.896 0.084 34.92 ;
    END
  END a_cfg_data[63]
  PIN a_cfg_data[64]
    DIRECTION OUTPUT ;
    USE SIGNAL ;
    PORT
      LAYER M4 ;
        RECT  0 34.992 0.084 35.016 ;
    END
  END a_cfg_data[64]
  PIN a_cfg_data[65]
    DIRECTION OUTPUT ;
    USE SIGNAL ;
    PORT
      LAYER M4 ;
        RECT  0 35.088 0.084 35.112 ;
    END
  END a_cfg_data[65]
  PIN a_cfg_data[66]
    DIRECTION OUTPUT ;
    USE SIGNAL ;
    PORT
      LAYER M4 ;
        RECT  0 35.184 0.084 35.208 ;
    END
  END a_cfg_data[66]
  PIN a_cfg_data[67]
    DIRECTION OUTPUT ;
    USE SIGNAL ;
    PORT
      LAYER M4 ;
        RECT  0 35.28 0.084 35.304 ;
    END
  END a_cfg_data[67]
  PIN a_cfg_data[68]
    DIRECTION OUTPUT ;
    USE SIGNAL ;
    PORT
      LAYER M4 ;
        RECT  0 35.376 0.084 35.4 ;
    END
  END a_cfg_data[68]
  PIN a_cfg_data[69]
    DIRECTION OUTPUT ;
    USE SIGNAL ;
    PORT
      LAYER M4 ;
        RECT  0 35.472 0.084 35.496 ;
    END
  END a_cfg_data[69]
  PIN a_cfg_data[6]
    DIRECTION OUTPUT ;
    USE SIGNAL ;
    PORT
      LAYER M4 ;
        RECT  0 41.712 0.084 41.736 ;
    END
  END a_cfg_data[6]
  PIN a_cfg_data[70]
    DIRECTION OUTPUT ;
    USE SIGNAL ;
    PORT
      LAYER M4 ;
        RECT  0 35.568 0.084 35.592 ;
    END
  END a_cfg_data[70]
  PIN a_cfg_data[71]
    DIRECTION OUTPUT ;
    USE SIGNAL ;
    PORT
      LAYER M4 ;
        RECT  0 35.664 0.084 35.688 ;
    END
  END a_cfg_data[71]
  PIN a_cfg_data[72]
    DIRECTION OUTPUT ;
    USE SIGNAL ;
    PORT
      LAYER M4 ;
        RECT  0 35.76 0.084 35.784 ;
    END
  END a_cfg_data[72]
  PIN a_cfg_data[73]
    DIRECTION OUTPUT ;
    USE SIGNAL ;
    PORT
      LAYER M4 ;
        RECT  0 35.856 0.084 35.88 ;
    END
  END a_cfg_data[73]
  PIN a_cfg_data[74]
    DIRECTION OUTPUT ;
    USE SIGNAL ;
    PORT
      LAYER M4 ;
        RECT  0 35.952 0.084 35.976 ;
    END
  END a_cfg_data[74]
  PIN a_cfg_data[75]
    DIRECTION OUTPUT ;
    USE SIGNAL ;
    PORT
      LAYER M4 ;
        RECT  0 36.048 0.084 36.072 ;
    END
  END a_cfg_data[75]
  PIN a_cfg_data[76]
    DIRECTION OUTPUT ;
    USE SIGNAL ;
    PORT
      LAYER M4 ;
        RECT  0 36.144 0.084 36.168 ;
    END
  END a_cfg_data[76]
  PIN a_cfg_data[77]
    DIRECTION OUTPUT ;
    USE SIGNAL ;
    PORT
      LAYER M4 ;
        RECT  0 36.24 0.084 36.264 ;
    END
  END a_cfg_data[77]
  PIN a_cfg_data[78]
    DIRECTION OUTPUT ;
    USE SIGNAL ;
    PORT
      LAYER M4 ;
        RECT  0 36.336 0.084 36.36 ;
    END
  END a_cfg_data[78]
  PIN a_cfg_data[79]
    DIRECTION OUTPUT ;
    USE SIGNAL ;
    PORT
      LAYER M4 ;
        RECT  0 36.432 0.084 36.456 ;
    END
  END a_cfg_data[79]
  PIN a_cfg_data[7]
    DIRECTION OUTPUT ;
    USE SIGNAL ;
    PORT
      LAYER M4 ;
        RECT  0 41.808 0.084 41.832 ;
    END
  END a_cfg_data[7]
  PIN a_cfg_data[80]
    DIRECTION OUTPUT ;
    USE SIGNAL ;
    PORT
      LAYER M4 ;
        RECT  0 36.528 0.084 36.552 ;
    END
  END a_cfg_data[80]
  PIN a_cfg_data[81]
    DIRECTION OUTPUT ;
    USE SIGNAL ;
    PORT
      LAYER M4 ;
        RECT  0 36.624 0.084 36.648 ;
    END
  END a_cfg_data[81]
  PIN a_cfg_data[82]
    DIRECTION OUTPUT ;
    USE SIGNAL ;
    PORT
      LAYER M4 ;
        RECT  0 36.72 0.084 36.744 ;
    END
  END a_cfg_data[82]
  PIN a_cfg_data[83]
    DIRECTION OUTPUT ;
    USE SIGNAL ;
    PORT
      LAYER M4 ;
        RECT  0 36.816 0.084 36.84 ;
    END
  END a_cfg_data[83]
  PIN a_cfg_data[84]
    DIRECTION OUTPUT ;
    USE SIGNAL ;
    PORT
      LAYER M4 ;
        RECT  0 43.056 0.084 43.08 ;
    END
  END a_cfg_data[84]
  PIN a_cfg_data[85]
    DIRECTION OUTPUT ;
    USE SIGNAL ;
    PORT
      LAYER M4 ;
        RECT  0 43.152 0.084 43.176 ;
    END
  END a_cfg_data[85]
  PIN a_cfg_data[86]
    DIRECTION OUTPUT ;
    USE SIGNAL ;
    PORT
      LAYER M4 ;
        RECT  0 43.248 0.084 43.272 ;
    END
  END a_cfg_data[86]
  PIN a_cfg_data[87]
    DIRECTION OUTPUT ;
    USE SIGNAL ;
    PORT
      LAYER M4 ;
        RECT  0 43.344 0.084 43.368 ;
    END
  END a_cfg_data[87]
  PIN a_cfg_data[88]
    DIRECTION OUTPUT ;
    USE SIGNAL ;
    PORT
      LAYER M4 ;
        RECT  0 43.44 0.084 43.464 ;
    END
  END a_cfg_data[88]
  PIN a_cfg_data[89]
    DIRECTION OUTPUT ;
    USE SIGNAL ;
    PORT
      LAYER M4 ;
        RECT  0 43.536 0.084 43.56 ;
    END
  END a_cfg_data[89]
  PIN a_cfg_data[8]
    DIRECTION OUTPUT ;
    USE SIGNAL ;
    PORT
      LAYER M4 ;
        RECT  0 41.904 0.084 41.928 ;
    END
  END a_cfg_data[8]
  PIN a_cfg_data[90]
    DIRECTION OUTPUT ;
    USE SIGNAL ;
    PORT
      LAYER M4 ;
        RECT  0 43.632 0.084 43.656 ;
    END
  END a_cfg_data[90]
  PIN a_cfg_data[91]
    DIRECTION OUTPUT ;
    USE SIGNAL ;
    PORT
      LAYER M4 ;
        RECT  0 43.728 0.084 43.752 ;
    END
  END a_cfg_data[91]
  PIN a_cfg_data[92]
    DIRECTION OUTPUT ;
    USE SIGNAL ;
    PORT
      LAYER M4 ;
        RECT  0 43.824 0.084 43.848 ;
    END
  END a_cfg_data[92]
  PIN a_cfg_data[93]
    DIRECTION OUTPUT ;
    USE SIGNAL ;
    PORT
      LAYER M4 ;
        RECT  0 43.92 0.084 43.944 ;
    END
  END a_cfg_data[93]
  PIN a_cfg_data[94]
    DIRECTION OUTPUT ;
    USE SIGNAL ;
    PORT
      LAYER M4 ;
        RECT  0 44.016 0.084 44.04 ;
    END
  END a_cfg_data[94]
  PIN a_cfg_data[95]
    DIRECTION OUTPUT ;
    USE SIGNAL ;
    PORT
      LAYER M4 ;
        RECT  0 44.112 0.084 44.136 ;
    END
  END a_cfg_data[95]
  PIN a_cfg_data[96]
    DIRECTION OUTPUT ;
    USE SIGNAL ;
    PORT
      LAYER M4 ;
        RECT  0 44.208 0.084 44.232 ;
    END
  END a_cfg_data[96]
  PIN a_cfg_data[97]
    DIRECTION OUTPUT ;
    USE SIGNAL ;
    PORT
      LAYER M4 ;
        RECT  0 44.304 0.084 44.328 ;
    END
  END a_cfg_data[97]
  PIN a_cfg_data[98]
    DIRECTION OUTPUT ;
    USE SIGNAL ;
    PORT
      LAYER M4 ;
        RECT  0 44.4 0.084 44.424 ;
    END
  END a_cfg_data[98]
  PIN a_cfg_data[99]
    DIRECTION OUTPUT ;
    USE SIGNAL ;
    PORT
      LAYER M4 ;
        RECT  0 44.496 0.084 44.52 ;
    END
  END a_cfg_data[99]
  PIN a_cfg_data[9]
    DIRECTION OUTPUT ;
    USE SIGNAL ;
    PORT
      LAYER M4 ;
        RECT  0 42 0.084 42.024 ;
    END
  END a_cfg_data[9]
  PIN a_cfg_target[0]
    DIRECTION OUTPUT ;
    USE SIGNAL ;
    PORT
      LAYER M4 ;
        RECT  0 18.864 0.084 18.888 ;
    END
  END a_cfg_target[0]
  PIN a_cfg_target[1]
    DIRECTION OUTPUT ;
    USE SIGNAL ;
    PORT
      LAYER M4 ;
        RECT  0 18.96 0.084 18.984 ;
    END
  END a_cfg_target[1]
  PIN a_cfg_target[2]
    DIRECTION OUTPUT ;
    USE SIGNAL ;
    PORT
      LAYER M4 ;
        RECT  0 19.056 0.084 19.08 ;
    END
  END a_cfg_target[2]
  PIN a_cfg_target[3]
    DIRECTION OUTPUT ;
    USE SIGNAL ;
    PORT
      LAYER M4 ;
        RECT  0 19.152 0.084 19.176 ;
    END
  END a_cfg_target[3]
  PIN a_cfg_target[4]
    DIRECTION OUTPUT ;
    USE SIGNAL ;
    PORT
      LAYER M4 ;
        RECT  0 19.248 0.084 19.272 ;
    END
  END a_cfg_target[4]
  PIN a_cfg_target[5]
    DIRECTION OUTPUT ;
    USE SIGNAL ;
    PORT
      LAYER M4 ;
        RECT  0 19.344 0.084 19.368 ;
    END
  END a_cfg_target[5]
  PIN a_cfg_target[6]
    DIRECTION OUTPUT ;
    USE SIGNAL ;
    PORT
      LAYER M4 ;
        RECT  0 19.44 0.084 19.464 ;
    END
  END a_cfg_target[6]
  PIN a_cfg_target[7]
    DIRECTION OUTPUT ;
    USE SIGNAL ;
    PORT
      LAYER M4 ;
        RECT  0 19.536 0.084 19.56 ;
    END
  END a_cfg_target[7]
  PIN a_cfg_v
    DIRECTION OUTPUT ;
    USE SIGNAL ;
    PORT
      LAYER M4 ;
        RECT  0 19.632 0.084 19.656 ;
    END
  END a_cfg_v
  PIN a_desc_base[0]
    DIRECTION OUTPUT ;
    USE SIGNAL ;
    PORT
      LAYER M4 ;
        RECT  0 19.728 0.084 19.752 ;
    END
  END a_desc_base[0]
  PIN a_desc_base[10]
    DIRECTION OUTPUT ;
    USE SIGNAL ;
    PORT
      LAYER M4 ;
        RECT  0 20.688 0.084 20.712 ;
    END
  END a_desc_base[10]
  PIN a_desc_base[11]
    DIRECTION OUTPUT ;
    USE SIGNAL ;
    PORT
      LAYER M4 ;
        RECT  0 23.856 0.084 23.88 ;
    END
  END a_desc_base[11]
  PIN a_desc_base[1]
    DIRECTION OUTPUT ;
    USE SIGNAL ;
    PORT
      LAYER M4 ;
        RECT  0 19.824 0.084 19.848 ;
    END
  END a_desc_base[1]
  PIN a_desc_base[2]
    DIRECTION OUTPUT ;
    USE SIGNAL ;
    PORT
      LAYER M4 ;
        RECT  0 19.92 0.084 19.944 ;
    END
  END a_desc_base[2]
  PIN a_desc_base[3]
    DIRECTION OUTPUT ;
    USE SIGNAL ;
    PORT
      LAYER M4 ;
        RECT  0 20.016 0.084 20.04 ;
    END
  END a_desc_base[3]
  PIN a_desc_base[4]
    DIRECTION OUTPUT ;
    USE SIGNAL ;
    PORT
      LAYER M4 ;
        RECT  0 20.112 0.084 20.136 ;
    END
  END a_desc_base[4]
  PIN a_desc_base[5]
    DIRECTION OUTPUT ;
    USE SIGNAL ;
    PORT
      LAYER M4 ;
        RECT  0 20.208 0.084 20.232 ;
    END
  END a_desc_base[5]
  PIN a_desc_base[6]
    DIRECTION OUTPUT ;
    USE SIGNAL ;
    PORT
      LAYER M4 ;
        RECT  0 20.304 0.084 20.328 ;
    END
  END a_desc_base[6]
  PIN a_desc_base[7]
    DIRECTION OUTPUT ;
    USE SIGNAL ;
    PORT
      LAYER M4 ;
        RECT  0 20.4 0.084 20.424 ;
    END
  END a_desc_base[7]
  PIN a_desc_base[8]
    DIRECTION OUTPUT ;
    USE SIGNAL ;
    PORT
      LAYER M4 ;
        RECT  0 20.496 0.084 20.52 ;
    END
  END a_desc_base[8]
  PIN a_desc_base[9]
    DIRECTION OUTPUT ;
    USE SIGNAL ;
    PORT
      LAYER M4 ;
        RECT  0 20.592 0.084 20.616 ;
    END
  END a_desc_base[9]
  PIN a_desc_limit[0]
    DIRECTION OUTPUT ;
    USE SIGNAL ;
    PORT
      LAYER M4 ;
        RECT  0 23.952 0.084 23.976 ;
    END
  END a_desc_limit[0]
  PIN a_desc_limit[10]
    DIRECTION OUTPUT ;
    USE SIGNAL ;
    PORT
      LAYER M4 ;
        RECT  0 24.912 0.084 24.936 ;
    END
  END a_desc_limit[10]
  PIN a_desc_limit[11]
    DIRECTION OUTPUT ;
    USE SIGNAL ;
    PORT
      LAYER M4 ;
        RECT  0 25.008 0.084 25.032 ;
    END
  END a_desc_limit[11]
  PIN a_desc_limit[12]
    DIRECTION OUTPUT ;
    USE SIGNAL ;
    PORT
      LAYER M4 ;
        RECT  0 25.104 0.084 25.128 ;
    END
  END a_desc_limit[12]
  PIN a_desc_limit[1]
    DIRECTION OUTPUT ;
    USE SIGNAL ;
    PORT
      LAYER M4 ;
        RECT  0 24.048 0.084 24.072 ;
    END
  END a_desc_limit[1]
  PIN a_desc_limit[2]
    DIRECTION OUTPUT ;
    USE SIGNAL ;
    PORT
      LAYER M4 ;
        RECT  0 24.144 0.084 24.168 ;
    END
  END a_desc_limit[2]
  PIN a_desc_limit[3]
    DIRECTION OUTPUT ;
    USE SIGNAL ;
    PORT
      LAYER M4 ;
        RECT  0 24.24 0.084 24.264 ;
    END
  END a_desc_limit[3]
  PIN a_desc_limit[4]
    DIRECTION OUTPUT ;
    USE SIGNAL ;
    PORT
      LAYER M4 ;
        RECT  0 24.336 0.084 24.36 ;
    END
  END a_desc_limit[4]
  PIN a_desc_limit[5]
    DIRECTION OUTPUT ;
    USE SIGNAL ;
    PORT
      LAYER M4 ;
        RECT  0 24.432 0.084 24.456 ;
    END
  END a_desc_limit[5]
  PIN a_desc_limit[6]
    DIRECTION OUTPUT ;
    USE SIGNAL ;
    PORT
      LAYER M4 ;
        RECT  0 24.528 0.084 24.552 ;
    END
  END a_desc_limit[6]
  PIN a_desc_limit[7]
    DIRECTION OUTPUT ;
    USE SIGNAL ;
    PORT
      LAYER M4 ;
        RECT  0 24.624 0.084 24.648 ;
    END
  END a_desc_limit[7]
  PIN a_desc_limit[8]
    DIRECTION OUTPUT ;
    USE SIGNAL ;
    PORT
      LAYER M4 ;
        RECT  0 24.72 0.084 24.744 ;
    END
  END a_desc_limit[8]
  PIN a_desc_limit[9]
    DIRECTION OUTPUT ;
    USE SIGNAL ;
    PORT
      LAYER M4 ;
        RECT  0 24.816 0.084 24.84 ;
    END
  END a_desc_limit[9]
  PIN a_desc_loops[0]
    DIRECTION OUTPUT ;
    USE SIGNAL ;
    PORT
      LAYER M4 ;
        RECT  0 25.2 0.084 25.224 ;
    END
  END a_desc_loops[0]
  PIN a_desc_loops[10]
    DIRECTION OUTPUT ;
    USE SIGNAL ;
    PORT
      LAYER M4 ;
        RECT  0 26.16 0.084 26.184 ;
    END
  END a_desc_loops[10]
  PIN a_desc_loops[11]
    DIRECTION OUTPUT ;
    USE SIGNAL ;
    PORT
      LAYER M4 ;
        RECT  0 26.256 0.084 26.28 ;
    END
  END a_desc_loops[11]
  PIN a_desc_loops[12]
    DIRECTION OUTPUT ;
    USE SIGNAL ;
    PORT
      LAYER M4 ;
        RECT  0 26.352 0.084 26.376 ;
    END
  END a_desc_loops[12]
  PIN a_desc_loops[13]
    DIRECTION OUTPUT ;
    USE SIGNAL ;
    PORT
      LAYER M4 ;
        RECT  0 26.448 0.084 26.472 ;
    END
  END a_desc_loops[13]
  PIN a_desc_loops[14]
    DIRECTION OUTPUT ;
    USE SIGNAL ;
    PORT
      LAYER M4 ;
        RECT  0 26.544 0.084 26.568 ;
    END
  END a_desc_loops[14]
  PIN a_desc_loops[15]
    DIRECTION OUTPUT ;
    USE SIGNAL ;
    PORT
      LAYER M4 ;
        RECT  0 26.64 0.084 26.664 ;
    END
  END a_desc_loops[15]
  PIN a_desc_loops[1]
    DIRECTION OUTPUT ;
    USE SIGNAL ;
    PORT
      LAYER M4 ;
        RECT  0 25.296 0.084 25.32 ;
    END
  END a_desc_loops[1]
  PIN a_desc_loops[2]
    DIRECTION OUTPUT ;
    USE SIGNAL ;
    PORT
      LAYER M4 ;
        RECT  0 25.392 0.084 25.416 ;
    END
  END a_desc_loops[2]
  PIN a_desc_loops[3]
    DIRECTION OUTPUT ;
    USE SIGNAL ;
    PORT
      LAYER M4 ;
        RECT  0 25.488 0.084 25.512 ;
    END
  END a_desc_loops[3]
  PIN a_desc_loops[4]
    DIRECTION OUTPUT ;
    USE SIGNAL ;
    PORT
      LAYER M4 ;
        RECT  0 25.584 0.084 25.608 ;
    END
  END a_desc_loops[4]
  PIN a_desc_loops[5]
    DIRECTION OUTPUT ;
    USE SIGNAL ;
    PORT
      LAYER M4 ;
        RECT  0 25.68 0.084 25.704 ;
    END
  END a_desc_loops[5]
  PIN a_desc_loops[6]
    DIRECTION OUTPUT ;
    USE SIGNAL ;
    PORT
      LAYER M4 ;
        RECT  0 25.776 0.084 25.8 ;
    END
  END a_desc_loops[6]
  PIN a_desc_loops[7]
    DIRECTION OUTPUT ;
    USE SIGNAL ;
    PORT
      LAYER M4 ;
        RECT  0 25.872 0.084 25.896 ;
    END
  END a_desc_loops[7]
  PIN a_desc_loops[8]
    DIRECTION OUTPUT ;
    USE SIGNAL ;
    PORT
      LAYER M4 ;
        RECT  0 25.968 0.084 25.992 ;
    END
  END a_desc_loops[8]
  PIN a_desc_loops[9]
    DIRECTION OUTPUT ;
    USE SIGNAL ;
    PORT
      LAYER M4 ;
        RECT  0 26.064 0.084 26.088 ;
    END
  END a_desc_loops[9]
  PIN a_desc_v
    DIRECTION OUTPUT ;
    USE SIGNAL ;
    PORT
      LAYER M4 ;
        RECT  0 26.736 0.084 26.76 ;
    END
  END a_desc_v
  PIN a_launch_v
    DIRECTION OUTPUT ;
    USE SIGNAL ;
    PORT
      LAYER M4 ;
        RECT  0 26.832 0.084 26.856 ;
    END
  END a_launch_v
  PIN b_cfg_addr[0]
    DIRECTION OUTPUT ;
    USE SIGNAL ;
    PORT
      LAYER M4 ;
        RECT  69.036 32.208 69.12 32.232 ;
    END
  END b_cfg_addr[0]
  PIN b_cfg_addr[10]
    DIRECTION OUTPUT ;
    USE SIGNAL ;
    PORT
      LAYER M4 ;
        RECT  69.036 33.168 69.12 33.192 ;
    END
  END b_cfg_addr[10]
  PIN b_cfg_addr[11]
    DIRECTION OUTPUT ;
    USE SIGNAL ;
    PORT
      LAYER M4 ;
        RECT  69.036 33.264 69.12 33.288 ;
    END
  END b_cfg_addr[11]
  PIN b_cfg_addr[1]
    DIRECTION OUTPUT ;
    USE SIGNAL ;
    PORT
      LAYER M4 ;
        RECT  69.036 32.304 69.12 32.328 ;
    END
  END b_cfg_addr[1]
  PIN b_cfg_addr[2]
    DIRECTION OUTPUT ;
    USE SIGNAL ;
    PORT
      LAYER M4 ;
        RECT  69.036 32.4 69.12 32.424 ;
    END
  END b_cfg_addr[2]
  PIN b_cfg_addr[3]
    DIRECTION OUTPUT ;
    USE SIGNAL ;
    PORT
      LAYER M4 ;
        RECT  69.036 32.496 69.12 32.52 ;
    END
  END b_cfg_addr[3]
  PIN b_cfg_addr[4]
    DIRECTION OUTPUT ;
    USE SIGNAL ;
    PORT
      LAYER M4 ;
        RECT  69.036 32.592 69.12 32.616 ;
    END
  END b_cfg_addr[4]
  PIN b_cfg_addr[5]
    DIRECTION OUTPUT ;
    USE SIGNAL ;
    PORT
      LAYER M4 ;
        RECT  69.036 32.688 69.12 32.712 ;
    END
  END b_cfg_addr[5]
  PIN b_cfg_addr[6]
    DIRECTION OUTPUT ;
    USE SIGNAL ;
    PORT
      LAYER M4 ;
        RECT  69.036 32.784 69.12 32.808 ;
    END
  END b_cfg_addr[6]
  PIN b_cfg_addr[7]
    DIRECTION OUTPUT ;
    USE SIGNAL ;
    PORT
      LAYER M4 ;
        RECT  69.036 32.88 69.12 32.904 ;
    END
  END b_cfg_addr[7]
  PIN b_cfg_addr[8]
    DIRECTION OUTPUT ;
    USE SIGNAL ;
    PORT
      LAYER M4 ;
        RECT  69.036 32.976 69.12 33 ;
    END
  END b_cfg_addr[8]
  PIN b_cfg_addr[9]
    DIRECTION OUTPUT ;
    USE SIGNAL ;
    PORT
      LAYER M4 ;
        RECT  69.036 33.072 69.12 33.096 ;
    END
  END b_cfg_addr[9]
  PIN b_cfg_data[0]
    DIRECTION OUTPUT ;
    USE SIGNAL ;
    PORT
      LAYER M4 ;
        RECT  69.036 33.36 69.12 33.384 ;
    END
  END b_cfg_data[0]
  PIN b_cfg_data[100]
    DIRECTION OUTPUT ;
    USE SIGNAL ;
    PORT
      LAYER M4 ;
        RECT  69.036 46.8 69.12 46.824 ;
    END
  END b_cfg_data[100]
  PIN b_cfg_data[101]
    DIRECTION OUTPUT ;
    USE SIGNAL ;
    PORT
      LAYER M4 ;
        RECT  69.036 46.896 69.12 46.92 ;
    END
  END b_cfg_data[101]
  PIN b_cfg_data[102]
    DIRECTION OUTPUT ;
    USE SIGNAL ;
    PORT
      LAYER M4 ;
        RECT  69.036 46.992 69.12 47.016 ;
    END
  END b_cfg_data[102]
  PIN b_cfg_data[103]
    DIRECTION OUTPUT ;
    USE SIGNAL ;
    PORT
      LAYER M4 ;
        RECT  69.036 47.088 69.12 47.112 ;
    END
  END b_cfg_data[103]
  PIN b_cfg_data[104]
    DIRECTION OUTPUT ;
    USE SIGNAL ;
    PORT
      LAYER M4 ;
        RECT  69.036 47.184 69.12 47.208 ;
    END
  END b_cfg_data[104]
  PIN b_cfg_data[105]
    DIRECTION OUTPUT ;
    USE SIGNAL ;
    PORT
      LAYER M4 ;
        RECT  69.036 47.28 69.12 47.304 ;
    END
  END b_cfg_data[105]
  PIN b_cfg_data[106]
    DIRECTION OUTPUT ;
    USE SIGNAL ;
    PORT
      LAYER M4 ;
        RECT  69.036 47.376 69.12 47.4 ;
    END
  END b_cfg_data[106]
  PIN b_cfg_data[107]
    DIRECTION OUTPUT ;
    USE SIGNAL ;
    PORT
      LAYER M4 ;
        RECT  69.036 47.472 69.12 47.496 ;
    END
  END b_cfg_data[107]
  PIN b_cfg_data[108]
    DIRECTION OUTPUT ;
    USE SIGNAL ;
    PORT
      LAYER M4 ;
        RECT  69.036 47.568 69.12 47.592 ;
    END
  END b_cfg_data[108]
  PIN b_cfg_data[109]
    DIRECTION OUTPUT ;
    USE SIGNAL ;
    PORT
      LAYER M4 ;
        RECT  69.036 47.664 69.12 47.688 ;
    END
  END b_cfg_data[109]
  PIN b_cfg_data[10]
    DIRECTION OUTPUT ;
    USE SIGNAL ;
    PORT
      LAYER M4 ;
        RECT  69.036 34.32 69.12 34.344 ;
    END
  END b_cfg_data[10]
  PIN b_cfg_data[110]
    DIRECTION OUTPUT ;
    USE SIGNAL ;
    PORT
      LAYER M4 ;
        RECT  69.036 47.76 69.12 47.784 ;
    END
  END b_cfg_data[110]
  PIN b_cfg_data[111]
    DIRECTION OUTPUT ;
    USE SIGNAL ;
    PORT
      LAYER M4 ;
        RECT  69.036 47.856 69.12 47.88 ;
    END
  END b_cfg_data[111]
  PIN b_cfg_data[112]
    DIRECTION OUTPUT ;
    USE SIGNAL ;
    PORT
      LAYER M4 ;
        RECT  69.036 47.952 69.12 47.976 ;
    END
  END b_cfg_data[112]
  PIN b_cfg_data[113]
    DIRECTION OUTPUT ;
    USE SIGNAL ;
    PORT
      LAYER M4 ;
        RECT  69.036 48.048 69.12 48.072 ;
    END
  END b_cfg_data[113]
  PIN b_cfg_data[114]
    DIRECTION OUTPUT ;
    USE SIGNAL ;
    PORT
      LAYER M4 ;
        RECT  69.036 48.144 69.12 48.168 ;
    END
  END b_cfg_data[114]
  PIN b_cfg_data[115]
    DIRECTION OUTPUT ;
    USE SIGNAL ;
    PORT
      LAYER M4 ;
        RECT  69.036 48.24 69.12 48.264 ;
    END
  END b_cfg_data[115]
  PIN b_cfg_data[116]
    DIRECTION OUTPUT ;
    USE SIGNAL ;
    PORT
      LAYER M4 ;
        RECT  69.036 48.336 69.12 48.36 ;
    END
  END b_cfg_data[116]
  PIN b_cfg_data[117]
    DIRECTION OUTPUT ;
    USE SIGNAL ;
    PORT
      LAYER M4 ;
        RECT  69.036 48.432 69.12 48.456 ;
    END
  END b_cfg_data[117]
  PIN b_cfg_data[118]
    DIRECTION OUTPUT ;
    USE SIGNAL ;
    PORT
      LAYER M4 ;
        RECT  69.036 48.528 69.12 48.552 ;
    END
  END b_cfg_data[118]
  PIN b_cfg_data[119]
    DIRECTION OUTPUT ;
    USE SIGNAL ;
    PORT
      LAYER M4 ;
        RECT  69.036 48.624 69.12 48.648 ;
    END
  END b_cfg_data[119]
  PIN b_cfg_data[11]
    DIRECTION OUTPUT ;
    USE SIGNAL ;
    PORT
      LAYER M4 ;
        RECT  69.036 34.416 69.12 34.44 ;
    END
  END b_cfg_data[11]
  PIN b_cfg_data[120]
    DIRECTION OUTPUT ;
    USE SIGNAL ;
    PORT
      LAYER M4 ;
        RECT  69.036 48.72 69.12 48.744 ;
    END
  END b_cfg_data[120]
  PIN b_cfg_data[121]
    DIRECTION OUTPUT ;
    USE SIGNAL ;
    PORT
      LAYER M4 ;
        RECT  69.036 48.816 69.12 48.84 ;
    END
  END b_cfg_data[121]
  PIN b_cfg_data[122]
    DIRECTION OUTPUT ;
    USE SIGNAL ;
    PORT
      LAYER M4 ;
        RECT  69.036 48.912 69.12 48.936 ;
    END
  END b_cfg_data[122]
  PIN b_cfg_data[123]
    DIRECTION OUTPUT ;
    USE SIGNAL ;
    PORT
      LAYER M4 ;
        RECT  69.036 49.008 69.12 49.032 ;
    END
  END b_cfg_data[123]
  PIN b_cfg_data[124]
    DIRECTION OUTPUT ;
    USE SIGNAL ;
    PORT
      LAYER M4 ;
        RECT  69.036 49.104 69.12 49.128 ;
    END
  END b_cfg_data[124]
  PIN b_cfg_data[125]
    DIRECTION OUTPUT ;
    USE SIGNAL ;
    PORT
      LAYER M4 ;
        RECT  69.036 49.2 69.12 49.224 ;
    END
  END b_cfg_data[125]
  PIN b_cfg_data[126]
    DIRECTION OUTPUT ;
    USE SIGNAL ;
    PORT
      LAYER M4 ;
        RECT  69.036 49.296 69.12 49.32 ;
    END
  END b_cfg_data[126]
  PIN b_cfg_data[127]
    DIRECTION OUTPUT ;
    USE SIGNAL ;
    PORT
      LAYER M4 ;
        RECT  69.036 49.392 69.12 49.416 ;
    END
  END b_cfg_data[127]
  PIN b_cfg_data[128]
    DIRECTION OUTPUT ;
    USE SIGNAL ;
    PORT
      LAYER M4 ;
        RECT  69.036 49.488 69.12 49.512 ;
    END
  END b_cfg_data[128]
  PIN b_cfg_data[129]
    DIRECTION OUTPUT ;
    USE SIGNAL ;
    PORT
      LAYER M4 ;
        RECT  69.036 49.584 69.12 49.608 ;
    END
  END b_cfg_data[129]
  PIN b_cfg_data[12]
    DIRECTION OUTPUT ;
    USE SIGNAL ;
    PORT
      LAYER M4 ;
        RECT  69.036 34.512 69.12 34.536 ;
    END
  END b_cfg_data[12]
  PIN b_cfg_data[130]
    DIRECTION OUTPUT ;
    USE SIGNAL ;
    PORT
      LAYER M4 ;
        RECT  69.036 49.68 69.12 49.704 ;
    END
  END b_cfg_data[130]
  PIN b_cfg_data[131]
    DIRECTION OUTPUT ;
    USE SIGNAL ;
    PORT
      LAYER M4 ;
        RECT  69.036 49.776 69.12 49.8 ;
    END
  END b_cfg_data[131]
  PIN b_cfg_data[132]
    DIRECTION OUTPUT ;
    USE SIGNAL ;
    PORT
      LAYER M4 ;
        RECT  69.036 49.872 69.12 49.896 ;
    END
  END b_cfg_data[132]
  PIN b_cfg_data[133]
    DIRECTION OUTPUT ;
    USE SIGNAL ;
    PORT
      LAYER M4 ;
        RECT  69.036 49.968 69.12 49.992 ;
    END
  END b_cfg_data[133]
  PIN b_cfg_data[134]
    DIRECTION OUTPUT ;
    USE SIGNAL ;
    PORT
      LAYER M4 ;
        RECT  69.036 50.064 69.12 50.088 ;
    END
  END b_cfg_data[134]
  PIN b_cfg_data[135]
    DIRECTION OUTPUT ;
    USE SIGNAL ;
    PORT
      LAYER M4 ;
        RECT  69.036 50.16 69.12 50.184 ;
    END
  END b_cfg_data[135]
  PIN b_cfg_data[136]
    DIRECTION OUTPUT ;
    USE SIGNAL ;
    PORT
      LAYER M4 ;
        RECT  69.036 50.256 69.12 50.28 ;
    END
  END b_cfg_data[136]
  PIN b_cfg_data[137]
    DIRECTION OUTPUT ;
    USE SIGNAL ;
    PORT
      LAYER M4 ;
        RECT  69.036 50.352 69.12 50.376 ;
    END
  END b_cfg_data[137]
  PIN b_cfg_data[138]
    DIRECTION OUTPUT ;
    USE SIGNAL ;
    PORT
      LAYER M4 ;
        RECT  69.036 50.448 69.12 50.472 ;
    END
  END b_cfg_data[138]
  PIN b_cfg_data[139]
    DIRECTION OUTPUT ;
    USE SIGNAL ;
    PORT
      LAYER M4 ;
        RECT  69.036 50.544 69.12 50.568 ;
    END
  END b_cfg_data[139]
  PIN b_cfg_data[13]
    DIRECTION OUTPUT ;
    USE SIGNAL ;
    PORT
      LAYER M4 ;
        RECT  69.036 34.608 69.12 34.632 ;
    END
  END b_cfg_data[13]
  PIN b_cfg_data[140]
    DIRECTION OUTPUT ;
    USE SIGNAL ;
    PORT
      LAYER M4 ;
        RECT  69.036 50.64 69.12 50.664 ;
    END
  END b_cfg_data[140]
  PIN b_cfg_data[141]
    DIRECTION OUTPUT ;
    USE SIGNAL ;
    PORT
      LAYER M4 ;
        RECT  69.036 50.736 69.12 50.76 ;
    END
  END b_cfg_data[141]
  PIN b_cfg_data[142]
    DIRECTION OUTPUT ;
    USE SIGNAL ;
    PORT
      LAYER M4 ;
        RECT  69.036 50.832 69.12 50.856 ;
    END
  END b_cfg_data[142]
  PIN b_cfg_data[143]
    DIRECTION OUTPUT ;
    USE SIGNAL ;
    PORT
      LAYER M4 ;
        RECT  69.036 50.928 69.12 50.952 ;
    END
  END b_cfg_data[143]
  PIN b_cfg_data[144]
    DIRECTION OUTPUT ;
    USE SIGNAL ;
    PORT
      LAYER M4 ;
        RECT  69.036 51.024 69.12 51.048 ;
    END
  END b_cfg_data[144]
  PIN b_cfg_data[145]
    DIRECTION OUTPUT ;
    USE SIGNAL ;
    PORT
      LAYER M4 ;
        RECT  69.036 51.12 69.12 51.144 ;
    END
  END b_cfg_data[145]
  PIN b_cfg_data[146]
    DIRECTION OUTPUT ;
    USE SIGNAL ;
    PORT
      LAYER M4 ;
        RECT  69.036 51.216 69.12 51.24 ;
    END
  END b_cfg_data[146]
  PIN b_cfg_data[147]
    DIRECTION OUTPUT ;
    USE SIGNAL ;
    PORT
      LAYER M4 ;
        RECT  69.036 51.312 69.12 51.336 ;
    END
  END b_cfg_data[147]
  PIN b_cfg_data[148]
    DIRECTION OUTPUT ;
    USE SIGNAL ;
    PORT
      LAYER M4 ;
        RECT  69.036 29.136 69.12 29.16 ;
    END
  END b_cfg_data[148]
  PIN b_cfg_data[149]
    DIRECTION OUTPUT ;
    USE SIGNAL ;
    PORT
      LAYER M4 ;
        RECT  69.036 29.232 69.12 29.256 ;
    END
  END b_cfg_data[149]
  PIN b_cfg_data[14]
    DIRECTION OUTPUT ;
    USE SIGNAL ;
    PORT
      LAYER M4 ;
        RECT  69.036 34.704 69.12 34.728 ;
    END
  END b_cfg_data[14]
  PIN b_cfg_data[150]
    DIRECTION OUTPUT ;
    USE SIGNAL ;
    PORT
      LAYER M4 ;
        RECT  69.036 29.328 69.12 29.352 ;
    END
  END b_cfg_data[150]
  PIN b_cfg_data[151]
    DIRECTION OUTPUT ;
    USE SIGNAL ;
    PORT
      LAYER M4 ;
        RECT  69.036 29.424 69.12 29.448 ;
    END
  END b_cfg_data[151]
  PIN b_cfg_data[152]
    DIRECTION OUTPUT ;
    USE SIGNAL ;
    PORT
      LAYER M4 ;
        RECT  69.036 29.52 69.12 29.544 ;
    END
  END b_cfg_data[152]
  PIN b_cfg_data[153]
    DIRECTION OUTPUT ;
    USE SIGNAL ;
    PORT
      LAYER M4 ;
        RECT  69.036 29.616 69.12 29.64 ;
    END
  END b_cfg_data[153]
  PIN b_cfg_data[154]
    DIRECTION OUTPUT ;
    USE SIGNAL ;
    PORT
      LAYER M4 ;
        RECT  69.036 29.712 69.12 29.736 ;
    END
  END b_cfg_data[154]
  PIN b_cfg_data[155]
    DIRECTION OUTPUT ;
    USE SIGNAL ;
    PORT
      LAYER M4 ;
        RECT  69.036 29.808 69.12 29.832 ;
    END
  END b_cfg_data[155]
  PIN b_cfg_data[156]
    DIRECTION OUTPUT ;
    USE SIGNAL ;
    PORT
      LAYER M4 ;
        RECT  69.036 29.904 69.12 29.928 ;
    END
  END b_cfg_data[156]
  PIN b_cfg_data[157]
    DIRECTION OUTPUT ;
    USE SIGNAL ;
    PORT
      LAYER M4 ;
        RECT  69.036 30 69.12 30.024 ;
    END
  END b_cfg_data[157]
  PIN b_cfg_data[158]
    DIRECTION OUTPUT ;
    USE SIGNAL ;
    PORT
      LAYER M4 ;
        RECT  69.036 30.096 69.12 30.12 ;
    END
  END b_cfg_data[158]
  PIN b_cfg_data[159]
    DIRECTION OUTPUT ;
    USE SIGNAL ;
    PORT
      LAYER M4 ;
        RECT  69.036 30.192 69.12 30.216 ;
    END
  END b_cfg_data[159]
  PIN b_cfg_data[15]
    DIRECTION OUTPUT ;
    USE SIGNAL ;
    PORT
      LAYER M4 ;
        RECT  69.036 34.8 69.12 34.824 ;
    END
  END b_cfg_data[15]
  PIN b_cfg_data[160]
    DIRECTION OUTPUT ;
    USE SIGNAL ;
    PORT
      LAYER M4 ;
        RECT  69.036 30.288 69.12 30.312 ;
    END
  END b_cfg_data[160]
  PIN b_cfg_data[161]
    DIRECTION OUTPUT ;
    USE SIGNAL ;
    PORT
      LAYER M4 ;
        RECT  69.036 30.384 69.12 30.408 ;
    END
  END b_cfg_data[161]
  PIN b_cfg_data[162]
    DIRECTION OUTPUT ;
    USE SIGNAL ;
    PORT
      LAYER M4 ;
        RECT  69.036 30.48 69.12 30.504 ;
    END
  END b_cfg_data[162]
  PIN b_cfg_data[163]
    DIRECTION OUTPUT ;
    USE SIGNAL ;
    PORT
      LAYER M4 ;
        RECT  69.036 30.576 69.12 30.6 ;
    END
  END b_cfg_data[163]
  PIN b_cfg_data[164]
    DIRECTION OUTPUT ;
    USE SIGNAL ;
    PORT
      LAYER M4 ;
        RECT  69.036 30.672 69.12 30.696 ;
    END
  END b_cfg_data[164]
  PIN b_cfg_data[165]
    DIRECTION OUTPUT ;
    USE SIGNAL ;
    PORT
      LAYER M4 ;
        RECT  69.036 30.768 69.12 30.792 ;
    END
  END b_cfg_data[165]
  PIN b_cfg_data[166]
    DIRECTION OUTPUT ;
    USE SIGNAL ;
    PORT
      LAYER M4 ;
        RECT  69.036 30.864 69.12 30.888 ;
    END
  END b_cfg_data[166]
  PIN b_cfg_data[167]
    DIRECTION OUTPUT ;
    USE SIGNAL ;
    PORT
      LAYER M4 ;
        RECT  69.036 30.96 69.12 30.984 ;
    END
  END b_cfg_data[167]
  PIN b_cfg_data[168]
    DIRECTION OUTPUT ;
    USE SIGNAL ;
    PORT
      LAYER M4 ;
        RECT  69.036 31.056 69.12 31.08 ;
    END
  END b_cfg_data[168]
  PIN b_cfg_data[169]
    DIRECTION OUTPUT ;
    USE SIGNAL ;
    PORT
      LAYER M4 ;
        RECT  69.036 31.152 69.12 31.176 ;
    END
  END b_cfg_data[169]
  PIN b_cfg_data[16]
    DIRECTION OUTPUT ;
    USE SIGNAL ;
    PORT
      LAYER M4 ;
        RECT  69.036 34.896 69.12 34.92 ;
    END
  END b_cfg_data[16]
  PIN b_cfg_data[170]
    DIRECTION OUTPUT ;
    USE SIGNAL ;
    PORT
      LAYER M4 ;
        RECT  69.036 31.248 69.12 31.272 ;
    END
  END b_cfg_data[170]
  PIN b_cfg_data[171]
    DIRECTION OUTPUT ;
    USE SIGNAL ;
    PORT
      LAYER M4 ;
        RECT  69.036 31.344 69.12 31.368 ;
    END
  END b_cfg_data[171]
  PIN b_cfg_data[172]
    DIRECTION OUTPUT ;
    USE SIGNAL ;
    PORT
      LAYER M4 ;
        RECT  69.036 31.44 69.12 31.464 ;
    END
  END b_cfg_data[172]
  PIN b_cfg_data[173]
    DIRECTION OUTPUT ;
    USE SIGNAL ;
    PORT
      LAYER M4 ;
        RECT  69.036 31.536 69.12 31.56 ;
    END
  END b_cfg_data[173]
  PIN b_cfg_data[174]
    DIRECTION OUTPUT ;
    USE SIGNAL ;
    PORT
      LAYER M4 ;
        RECT  69.036 31.632 69.12 31.656 ;
    END
  END b_cfg_data[174]
  PIN b_cfg_data[175]
    DIRECTION OUTPUT ;
    USE SIGNAL ;
    PORT
      LAYER M4 ;
        RECT  69.036 31.728 69.12 31.752 ;
    END
  END b_cfg_data[175]
  PIN b_cfg_data[176]
    DIRECTION OUTPUT ;
    USE SIGNAL ;
    PORT
      LAYER M4 ;
        RECT  69.036 31.824 69.12 31.848 ;
    END
  END b_cfg_data[176]
  PIN b_cfg_data[177]
    DIRECTION OUTPUT ;
    USE SIGNAL ;
    PORT
      LAYER M4 ;
        RECT  69.036 31.92 69.12 31.944 ;
    END
  END b_cfg_data[177]
  PIN b_cfg_data[178]
    DIRECTION OUTPUT ;
    USE SIGNAL ;
    PORT
      LAYER M4 ;
        RECT  69.036 32.016 69.12 32.04 ;
    END
  END b_cfg_data[178]
  PIN b_cfg_data[179]
    DIRECTION OUTPUT ;
    USE SIGNAL ;
    PORT
      LAYER M4 ;
        RECT  69.036 32.112 69.12 32.136 ;
    END
  END b_cfg_data[179]
  PIN b_cfg_data[17]
    DIRECTION OUTPUT ;
    USE SIGNAL ;
    PORT
      LAYER M4 ;
        RECT  69.036 34.992 69.12 35.016 ;
    END
  END b_cfg_data[17]
  PIN b_cfg_data[180]
    DIRECTION OUTPUT ;
    USE SIGNAL ;
    PORT
      LAYER M4 ;
        RECT  69.036 19.92 69.12 19.944 ;
    END
  END b_cfg_data[180]
  PIN b_cfg_data[181]
    DIRECTION OUTPUT ;
    USE SIGNAL ;
    PORT
      LAYER M4 ;
        RECT  69.036 20.016 69.12 20.04 ;
    END
  END b_cfg_data[181]
  PIN b_cfg_data[182]
    DIRECTION OUTPUT ;
    USE SIGNAL ;
    PORT
      LAYER M4 ;
        RECT  69.036 20.112 69.12 20.136 ;
    END
  END b_cfg_data[182]
  PIN b_cfg_data[183]
    DIRECTION OUTPUT ;
    USE SIGNAL ;
    PORT
      LAYER M4 ;
        RECT  69.036 20.208 69.12 20.232 ;
    END
  END b_cfg_data[183]
  PIN b_cfg_data[184]
    DIRECTION OUTPUT ;
    USE SIGNAL ;
    PORT
      LAYER M4 ;
        RECT  69.036 20.304 69.12 20.328 ;
    END
  END b_cfg_data[184]
  PIN b_cfg_data[185]
    DIRECTION OUTPUT ;
    USE SIGNAL ;
    PORT
      LAYER M4 ;
        RECT  69.036 20.4 69.12 20.424 ;
    END
  END b_cfg_data[185]
  PIN b_cfg_data[186]
    DIRECTION OUTPUT ;
    USE SIGNAL ;
    PORT
      LAYER M4 ;
        RECT  69.036 20.496 69.12 20.52 ;
    END
  END b_cfg_data[186]
  PIN b_cfg_data[187]
    DIRECTION OUTPUT ;
    USE SIGNAL ;
    PORT
      LAYER M4 ;
        RECT  69.036 20.592 69.12 20.616 ;
    END
  END b_cfg_data[187]
  PIN b_cfg_data[188]
    DIRECTION OUTPUT ;
    USE SIGNAL ;
    PORT
      LAYER M4 ;
        RECT  69.036 20.688 69.12 20.712 ;
    END
  END b_cfg_data[188]
  PIN b_cfg_data[189]
    DIRECTION OUTPUT ;
    USE SIGNAL ;
    PORT
      LAYER M4 ;
        RECT  69.036 20.784 69.12 20.808 ;
    END
  END b_cfg_data[189]
  PIN b_cfg_data[18]
    DIRECTION OUTPUT ;
    USE SIGNAL ;
    PORT
      LAYER M4 ;
        RECT  69.036 35.088 69.12 35.112 ;
    END
  END b_cfg_data[18]
  PIN b_cfg_data[190]
    DIRECTION OUTPUT ;
    USE SIGNAL ;
    PORT
      LAYER M4 ;
        RECT  69.036 20.88 69.12 20.904 ;
    END
  END b_cfg_data[190]
  PIN b_cfg_data[191]
    DIRECTION OUTPUT ;
    USE SIGNAL ;
    PORT
      LAYER M4 ;
        RECT  69.036 20.976 69.12 21 ;
    END
  END b_cfg_data[191]
  PIN b_cfg_data[192]
    DIRECTION OUTPUT ;
    USE SIGNAL ;
    PORT
      LAYER M4 ;
        RECT  69.036 21.072 69.12 21.096 ;
    END
  END b_cfg_data[192]
  PIN b_cfg_data[193]
    DIRECTION OUTPUT ;
    USE SIGNAL ;
    PORT
      LAYER M4 ;
        RECT  69.036 21.168 69.12 21.192 ;
    END
  END b_cfg_data[193]
  PIN b_cfg_data[194]
    DIRECTION OUTPUT ;
    USE SIGNAL ;
    PORT
      LAYER M4 ;
        RECT  69.036 21.264 69.12 21.288 ;
    END
  END b_cfg_data[194]
  PIN b_cfg_data[195]
    DIRECTION OUTPUT ;
    USE SIGNAL ;
    PORT
      LAYER M4 ;
        RECT  69.036 21.36 69.12 21.384 ;
    END
  END b_cfg_data[195]
  PIN b_cfg_data[196]
    DIRECTION OUTPUT ;
    USE SIGNAL ;
    PORT
      LAYER M4 ;
        RECT  69.036 21.456 69.12 21.48 ;
    END
  END b_cfg_data[196]
  PIN b_cfg_data[197]
    DIRECTION OUTPUT ;
    USE SIGNAL ;
    PORT
      LAYER M4 ;
        RECT  69.036 21.552 69.12 21.576 ;
    END
  END b_cfg_data[197]
  PIN b_cfg_data[198]
    DIRECTION OUTPUT ;
    USE SIGNAL ;
    PORT
      LAYER M4 ;
        RECT  69.036 21.648 69.12 21.672 ;
    END
  END b_cfg_data[198]
  PIN b_cfg_data[199]
    DIRECTION OUTPUT ;
    USE SIGNAL ;
    PORT
      LAYER M4 ;
        RECT  69.036 21.744 69.12 21.768 ;
    END
  END b_cfg_data[199]
  PIN b_cfg_data[19]
    DIRECTION OUTPUT ;
    USE SIGNAL ;
    PORT
      LAYER M4 ;
        RECT  69.036 35.184 69.12 35.208 ;
    END
  END b_cfg_data[19]
  PIN b_cfg_data[1]
    DIRECTION OUTPUT ;
    USE SIGNAL ;
    PORT
      LAYER M4 ;
        RECT  69.036 33.456 69.12 33.48 ;
    END
  END b_cfg_data[1]
  PIN b_cfg_data[200]
    DIRECTION OUTPUT ;
    USE SIGNAL ;
    PORT
      LAYER M4 ;
        RECT  69.036 21.84 69.12 21.864 ;
    END
  END b_cfg_data[200]
  PIN b_cfg_data[201]
    DIRECTION OUTPUT ;
    USE SIGNAL ;
    PORT
      LAYER M4 ;
        RECT  69.036 21.936 69.12 21.96 ;
    END
  END b_cfg_data[201]
  PIN b_cfg_data[202]
    DIRECTION OUTPUT ;
    USE SIGNAL ;
    PORT
      LAYER M4 ;
        RECT  69.036 22.032 69.12 22.056 ;
    END
  END b_cfg_data[202]
  PIN b_cfg_data[203]
    DIRECTION OUTPUT ;
    USE SIGNAL ;
    PORT
      LAYER M4 ;
        RECT  69.036 22.128 69.12 22.152 ;
    END
  END b_cfg_data[203]
  PIN b_cfg_data[204]
    DIRECTION OUTPUT ;
    USE SIGNAL ;
    PORT
      LAYER M4 ;
        RECT  69.036 22.224 69.12 22.248 ;
    END
  END b_cfg_data[204]
  PIN b_cfg_data[205]
    DIRECTION OUTPUT ;
    USE SIGNAL ;
    PORT
      LAYER M4 ;
        RECT  69.036 22.32 69.12 22.344 ;
    END
  END b_cfg_data[205]
  PIN b_cfg_data[206]
    DIRECTION OUTPUT ;
    USE SIGNAL ;
    PORT
      LAYER M4 ;
        RECT  69.036 22.416 69.12 22.44 ;
    END
  END b_cfg_data[206]
  PIN b_cfg_data[207]
    DIRECTION OUTPUT ;
    USE SIGNAL ;
    PORT
      LAYER M4 ;
        RECT  69.036 22.512 69.12 22.536 ;
    END
  END b_cfg_data[207]
  PIN b_cfg_data[208]
    DIRECTION OUTPUT ;
    USE SIGNAL ;
    PORT
      LAYER M4 ;
        RECT  69.036 22.608 69.12 22.632 ;
    END
  END b_cfg_data[208]
  PIN b_cfg_data[209]
    DIRECTION OUTPUT ;
    USE SIGNAL ;
    PORT
      LAYER M4 ;
        RECT  69.036 22.704 69.12 22.728 ;
    END
  END b_cfg_data[209]
  PIN b_cfg_data[20]
    DIRECTION OUTPUT ;
    USE SIGNAL ;
    PORT
      LAYER M4 ;
        RECT  69.036 22.992 69.12 23.016 ;
    END
  END b_cfg_data[20]
  PIN b_cfg_data[210]
    DIRECTION OUTPUT ;
    USE SIGNAL ;
    PORT
      LAYER M4 ;
        RECT  69.036 22.8 69.12 22.824 ;
    END
  END b_cfg_data[210]
  PIN b_cfg_data[211]
    DIRECTION OUTPUT ;
    USE SIGNAL ;
    PORT
      LAYER M4 ;
        RECT  69.036 22.896 69.12 22.92 ;
    END
  END b_cfg_data[211]
  PIN b_cfg_data[212]
    DIRECTION OUTPUT ;
    USE SIGNAL ;
    PORT
      LAYER M4 ;
        RECT  69.036 26.064 69.12 26.088 ;
    END
  END b_cfg_data[212]
  PIN b_cfg_data[213]
    DIRECTION OUTPUT ;
    USE SIGNAL ;
    PORT
      LAYER M4 ;
        RECT  69.036 26.16 69.12 26.184 ;
    END
  END b_cfg_data[213]
  PIN b_cfg_data[214]
    DIRECTION OUTPUT ;
    USE SIGNAL ;
    PORT
      LAYER M4 ;
        RECT  69.036 26.256 69.12 26.28 ;
    END
  END b_cfg_data[214]
  PIN b_cfg_data[215]
    DIRECTION OUTPUT ;
    USE SIGNAL ;
    PORT
      LAYER M4 ;
        RECT  69.036 26.352 69.12 26.376 ;
    END
  END b_cfg_data[215]
  PIN b_cfg_data[216]
    DIRECTION OUTPUT ;
    USE SIGNAL ;
    PORT
      LAYER M4 ;
        RECT  69.036 26.448 69.12 26.472 ;
    END
  END b_cfg_data[216]
  PIN b_cfg_data[217]
    DIRECTION OUTPUT ;
    USE SIGNAL ;
    PORT
      LAYER M4 ;
        RECT  69.036 26.544 69.12 26.568 ;
    END
  END b_cfg_data[217]
  PIN b_cfg_data[218]
    DIRECTION OUTPUT ;
    USE SIGNAL ;
    PORT
      LAYER M4 ;
        RECT  69.036 26.64 69.12 26.664 ;
    END
  END b_cfg_data[218]
  PIN b_cfg_data[219]
    DIRECTION OUTPUT ;
    USE SIGNAL ;
    PORT
      LAYER M4 ;
        RECT  69.036 26.736 69.12 26.76 ;
    END
  END b_cfg_data[219]
  PIN b_cfg_data[21]
    DIRECTION OUTPUT ;
    USE SIGNAL ;
    PORT
      LAYER M4 ;
        RECT  69.036 23.088 69.12 23.112 ;
    END
  END b_cfg_data[21]
  PIN b_cfg_data[220]
    DIRECTION OUTPUT ;
    USE SIGNAL ;
    PORT
      LAYER M4 ;
        RECT  69.036 26.832 69.12 26.856 ;
    END
  END b_cfg_data[220]
  PIN b_cfg_data[221]
    DIRECTION OUTPUT ;
    USE SIGNAL ;
    PORT
      LAYER M4 ;
        RECT  69.036 26.928 69.12 26.952 ;
    END
  END b_cfg_data[221]
  PIN b_cfg_data[222]
    DIRECTION OUTPUT ;
    USE SIGNAL ;
    PORT
      LAYER M4 ;
        RECT  69.036 27.024 69.12 27.048 ;
    END
  END b_cfg_data[222]
  PIN b_cfg_data[223]
    DIRECTION OUTPUT ;
    USE SIGNAL ;
    PORT
      LAYER M4 ;
        RECT  69.036 27.12 69.12 27.144 ;
    END
  END b_cfg_data[223]
  PIN b_cfg_data[224]
    DIRECTION OUTPUT ;
    USE SIGNAL ;
    PORT
      LAYER M4 ;
        RECT  69.036 27.216 69.12 27.24 ;
    END
  END b_cfg_data[224]
  PIN b_cfg_data[225]
    DIRECTION OUTPUT ;
    USE SIGNAL ;
    PORT
      LAYER M4 ;
        RECT  69.036 27.312 69.12 27.336 ;
    END
  END b_cfg_data[225]
  PIN b_cfg_data[226]
    DIRECTION OUTPUT ;
    USE SIGNAL ;
    PORT
      LAYER M4 ;
        RECT  69.036 27.408 69.12 27.432 ;
    END
  END b_cfg_data[226]
  PIN b_cfg_data[227]
    DIRECTION OUTPUT ;
    USE SIGNAL ;
    PORT
      LAYER M4 ;
        RECT  69.036 27.504 69.12 27.528 ;
    END
  END b_cfg_data[227]
  PIN b_cfg_data[228]
    DIRECTION OUTPUT ;
    USE SIGNAL ;
    PORT
      LAYER M4 ;
        RECT  69.036 27.6 69.12 27.624 ;
    END
  END b_cfg_data[228]
  PIN b_cfg_data[229]
    DIRECTION OUTPUT ;
    USE SIGNAL ;
    PORT
      LAYER M4 ;
        RECT  69.036 27.696 69.12 27.72 ;
    END
  END b_cfg_data[229]
  PIN b_cfg_data[22]
    DIRECTION OUTPUT ;
    USE SIGNAL ;
    PORT
      LAYER M4 ;
        RECT  69.036 23.184 69.12 23.208 ;
    END
  END b_cfg_data[22]
  PIN b_cfg_data[230]
    DIRECTION OUTPUT ;
    USE SIGNAL ;
    PORT
      LAYER M4 ;
        RECT  69.036 27.792 69.12 27.816 ;
    END
  END b_cfg_data[230]
  PIN b_cfg_data[231]
    DIRECTION OUTPUT ;
    USE SIGNAL ;
    PORT
      LAYER M4 ;
        RECT  69.036 27.888 69.12 27.912 ;
    END
  END b_cfg_data[231]
  PIN b_cfg_data[232]
    DIRECTION OUTPUT ;
    USE SIGNAL ;
    PORT
      LAYER M4 ;
        RECT  69.036 27.984 69.12 28.008 ;
    END
  END b_cfg_data[232]
  PIN b_cfg_data[233]
    DIRECTION OUTPUT ;
    USE SIGNAL ;
    PORT
      LAYER M4 ;
        RECT  69.036 28.08 69.12 28.104 ;
    END
  END b_cfg_data[233]
  PIN b_cfg_data[234]
    DIRECTION OUTPUT ;
    USE SIGNAL ;
    PORT
      LAYER M4 ;
        RECT  69.036 28.176 69.12 28.2 ;
    END
  END b_cfg_data[234]
  PIN b_cfg_data[235]
    DIRECTION OUTPUT ;
    USE SIGNAL ;
    PORT
      LAYER M4 ;
        RECT  69.036 28.272 69.12 28.296 ;
    END
  END b_cfg_data[235]
  PIN b_cfg_data[236]
    DIRECTION OUTPUT ;
    USE SIGNAL ;
    PORT
      LAYER M4 ;
        RECT  69.036 28.368 69.12 28.392 ;
    END
  END b_cfg_data[236]
  PIN b_cfg_data[237]
    DIRECTION OUTPUT ;
    USE SIGNAL ;
    PORT
      LAYER M4 ;
        RECT  69.036 28.464 69.12 28.488 ;
    END
  END b_cfg_data[237]
  PIN b_cfg_data[238]
    DIRECTION OUTPUT ;
    USE SIGNAL ;
    PORT
      LAYER M4 ;
        RECT  69.036 28.56 69.12 28.584 ;
    END
  END b_cfg_data[238]
  PIN b_cfg_data[239]
    DIRECTION OUTPUT ;
    USE SIGNAL ;
    PORT
      LAYER M4 ;
        RECT  69.036 28.656 69.12 28.68 ;
    END
  END b_cfg_data[239]
  PIN b_cfg_data[23]
    DIRECTION OUTPUT ;
    USE SIGNAL ;
    PORT
      LAYER M4 ;
        RECT  69.036 23.28 69.12 23.304 ;
    END
  END b_cfg_data[23]
  PIN b_cfg_data[240]
    DIRECTION OUTPUT ;
    USE SIGNAL ;
    PORT
      LAYER M4 ;
        RECT  69.036 28.752 69.12 28.776 ;
    END
  END b_cfg_data[240]
  PIN b_cfg_data[241]
    DIRECTION OUTPUT ;
    USE SIGNAL ;
    PORT
      LAYER M4 ;
        RECT  69.036 28.848 69.12 28.872 ;
    END
  END b_cfg_data[241]
  PIN b_cfg_data[242]
    DIRECTION OUTPUT ;
    USE SIGNAL ;
    PORT
      LAYER M4 ;
        RECT  69.036 28.944 69.12 28.968 ;
    END
  END b_cfg_data[242]
  PIN b_cfg_data[243]
    DIRECTION OUTPUT ;
    USE SIGNAL ;
    PORT
      LAYER M4 ;
        RECT  69.036 29.04 69.12 29.064 ;
    END
  END b_cfg_data[243]
  PIN b_cfg_data[244]
    DIRECTION OUTPUT ;
    USE SIGNAL ;
    PORT
      LAYER M4 ;
        RECT  69.036 42.192 69.12 42.216 ;
    END
  END b_cfg_data[244]
  PIN b_cfg_data[245]
    DIRECTION OUTPUT ;
    USE SIGNAL ;
    PORT
      LAYER M4 ;
        RECT  69.036 42.288 69.12 42.312 ;
    END
  END b_cfg_data[245]
  PIN b_cfg_data[246]
    DIRECTION OUTPUT ;
    USE SIGNAL ;
    PORT
      LAYER M4 ;
        RECT  69.036 42.384 69.12 42.408 ;
    END
  END b_cfg_data[246]
  PIN b_cfg_data[247]
    DIRECTION OUTPUT ;
    USE SIGNAL ;
    PORT
      LAYER M4 ;
        RECT  69.036 42.48 69.12 42.504 ;
    END
  END b_cfg_data[247]
  PIN b_cfg_data[248]
    DIRECTION OUTPUT ;
    USE SIGNAL ;
    PORT
      LAYER M4 ;
        RECT  69.036 42.576 69.12 42.6 ;
    END
  END b_cfg_data[248]
  PIN b_cfg_data[249]
    DIRECTION OUTPUT ;
    USE SIGNAL ;
    PORT
      LAYER M4 ;
        RECT  69.036 42.672 69.12 42.696 ;
    END
  END b_cfg_data[249]
  PIN b_cfg_data[24]
    DIRECTION OUTPUT ;
    USE SIGNAL ;
    PORT
      LAYER M4 ;
        RECT  69.036 23.376 69.12 23.4 ;
    END
  END b_cfg_data[24]
  PIN b_cfg_data[250]
    DIRECTION OUTPUT ;
    USE SIGNAL ;
    PORT
      LAYER M4 ;
        RECT  69.036 42.768 69.12 42.792 ;
    END
  END b_cfg_data[250]
  PIN b_cfg_data[251]
    DIRECTION OUTPUT ;
    USE SIGNAL ;
    PORT
      LAYER M4 ;
        RECT  69.036 42.864 69.12 42.888 ;
    END
  END b_cfg_data[251]
  PIN b_cfg_data[252]
    DIRECTION OUTPUT ;
    USE SIGNAL ;
    PORT
      LAYER M4 ;
        RECT  69.036 42.96 69.12 42.984 ;
    END
  END b_cfg_data[252]
  PIN b_cfg_data[253]
    DIRECTION OUTPUT ;
    USE SIGNAL ;
    PORT
      LAYER M4 ;
        RECT  69.036 43.056 69.12 43.08 ;
    END
  END b_cfg_data[253]
  PIN b_cfg_data[254]
    DIRECTION OUTPUT ;
    USE SIGNAL ;
    PORT
      LAYER M4 ;
        RECT  69.036 43.152 69.12 43.176 ;
    END
  END b_cfg_data[254]
  PIN b_cfg_data[255]
    DIRECTION OUTPUT ;
    USE SIGNAL ;
    PORT
      LAYER M4 ;
        RECT  69.036 43.248 69.12 43.272 ;
    END
  END b_cfg_data[255]
  PIN b_cfg_data[25]
    DIRECTION OUTPUT ;
    USE SIGNAL ;
    PORT
      LAYER M4 ;
        RECT  69.036 23.472 69.12 23.496 ;
    END
  END b_cfg_data[25]
  PIN b_cfg_data[26]
    DIRECTION OUTPUT ;
    USE SIGNAL ;
    PORT
      LAYER M4 ;
        RECT  69.036 23.568 69.12 23.592 ;
    END
  END b_cfg_data[26]
  PIN b_cfg_data[27]
    DIRECTION OUTPUT ;
    USE SIGNAL ;
    PORT
      LAYER M4 ;
        RECT  69.036 23.664 69.12 23.688 ;
    END
  END b_cfg_data[27]
  PIN b_cfg_data[28]
    DIRECTION OUTPUT ;
    USE SIGNAL ;
    PORT
      LAYER M4 ;
        RECT  69.036 23.76 69.12 23.784 ;
    END
  END b_cfg_data[28]
  PIN b_cfg_data[29]
    DIRECTION OUTPUT ;
    USE SIGNAL ;
    PORT
      LAYER M4 ;
        RECT  69.036 23.856 69.12 23.88 ;
    END
  END b_cfg_data[29]
  PIN b_cfg_data[2]
    DIRECTION OUTPUT ;
    USE SIGNAL ;
    PORT
      LAYER M4 ;
        RECT  69.036 33.552 69.12 33.576 ;
    END
  END b_cfg_data[2]
  PIN b_cfg_data[30]
    DIRECTION OUTPUT ;
    USE SIGNAL ;
    PORT
      LAYER M4 ;
        RECT  69.036 23.952 69.12 23.976 ;
    END
  END b_cfg_data[30]
  PIN b_cfg_data[31]
    DIRECTION OUTPUT ;
    USE SIGNAL ;
    PORT
      LAYER M4 ;
        RECT  69.036 24.048 69.12 24.072 ;
    END
  END b_cfg_data[31]
  PIN b_cfg_data[32]
    DIRECTION OUTPUT ;
    USE SIGNAL ;
    PORT
      LAYER M4 ;
        RECT  69.036 24.144 69.12 24.168 ;
    END
  END b_cfg_data[32]
  PIN b_cfg_data[33]
    DIRECTION OUTPUT ;
    USE SIGNAL ;
    PORT
      LAYER M4 ;
        RECT  69.036 24.24 69.12 24.264 ;
    END
  END b_cfg_data[33]
  PIN b_cfg_data[34]
    DIRECTION OUTPUT ;
    USE SIGNAL ;
    PORT
      LAYER M4 ;
        RECT  69.036 24.336 69.12 24.36 ;
    END
  END b_cfg_data[34]
  PIN b_cfg_data[35]
    DIRECTION OUTPUT ;
    USE SIGNAL ;
    PORT
      LAYER M4 ;
        RECT  69.036 24.432 69.12 24.456 ;
    END
  END b_cfg_data[35]
  PIN b_cfg_data[36]
    DIRECTION OUTPUT ;
    USE SIGNAL ;
    PORT
      LAYER M4 ;
        RECT  69.036 24.528 69.12 24.552 ;
    END
  END b_cfg_data[36]
  PIN b_cfg_data[37]
    DIRECTION OUTPUT ;
    USE SIGNAL ;
    PORT
      LAYER M4 ;
        RECT  69.036 24.624 69.12 24.648 ;
    END
  END b_cfg_data[37]
  PIN b_cfg_data[38]
    DIRECTION OUTPUT ;
    USE SIGNAL ;
    PORT
      LAYER M4 ;
        RECT  69.036 24.72 69.12 24.744 ;
    END
  END b_cfg_data[38]
  PIN b_cfg_data[39]
    DIRECTION OUTPUT ;
    USE SIGNAL ;
    PORT
      LAYER M4 ;
        RECT  69.036 24.816 69.12 24.84 ;
    END
  END b_cfg_data[39]
  PIN b_cfg_data[3]
    DIRECTION OUTPUT ;
    USE SIGNAL ;
    PORT
      LAYER M4 ;
        RECT  69.036 33.648 69.12 33.672 ;
    END
  END b_cfg_data[3]
  PIN b_cfg_data[40]
    DIRECTION OUTPUT ;
    USE SIGNAL ;
    PORT
      LAYER M4 ;
        RECT  69.036 24.912 69.12 24.936 ;
    END
  END b_cfg_data[40]
  PIN b_cfg_data[41]
    DIRECTION OUTPUT ;
    USE SIGNAL ;
    PORT
      LAYER M4 ;
        RECT  69.036 25.008 69.12 25.032 ;
    END
  END b_cfg_data[41]
  PIN b_cfg_data[42]
    DIRECTION OUTPUT ;
    USE SIGNAL ;
    PORT
      LAYER M4 ;
        RECT  69.036 25.104 69.12 25.128 ;
    END
  END b_cfg_data[42]
  PIN b_cfg_data[43]
    DIRECTION OUTPUT ;
    USE SIGNAL ;
    PORT
      LAYER M4 ;
        RECT  69.036 25.2 69.12 25.224 ;
    END
  END b_cfg_data[43]
  PIN b_cfg_data[44]
    DIRECTION OUTPUT ;
    USE SIGNAL ;
    PORT
      LAYER M4 ;
        RECT  69.036 25.296 69.12 25.32 ;
    END
  END b_cfg_data[44]
  PIN b_cfg_data[45]
    DIRECTION OUTPUT ;
    USE SIGNAL ;
    PORT
      LAYER M4 ;
        RECT  69.036 25.392 69.12 25.416 ;
    END
  END b_cfg_data[45]
  PIN b_cfg_data[46]
    DIRECTION OUTPUT ;
    USE SIGNAL ;
    PORT
      LAYER M4 ;
        RECT  69.036 25.488 69.12 25.512 ;
    END
  END b_cfg_data[46]
  PIN b_cfg_data[47]
    DIRECTION OUTPUT ;
    USE SIGNAL ;
    PORT
      LAYER M4 ;
        RECT  69.036 25.584 69.12 25.608 ;
    END
  END b_cfg_data[47]
  PIN b_cfg_data[48]
    DIRECTION OUTPUT ;
    USE SIGNAL ;
    PORT
      LAYER M4 ;
        RECT  69.036 25.68 69.12 25.704 ;
    END
  END b_cfg_data[48]
  PIN b_cfg_data[49]
    DIRECTION OUTPUT ;
    USE SIGNAL ;
    PORT
      LAYER M4 ;
        RECT  69.036 25.776 69.12 25.8 ;
    END
  END b_cfg_data[49]
  PIN b_cfg_data[4]
    DIRECTION OUTPUT ;
    USE SIGNAL ;
    PORT
      LAYER M4 ;
        RECT  69.036 33.744 69.12 33.768 ;
    END
  END b_cfg_data[4]
  PIN b_cfg_data[50]
    DIRECTION OUTPUT ;
    USE SIGNAL ;
    PORT
      LAYER M4 ;
        RECT  69.036 25.872 69.12 25.896 ;
    END
  END b_cfg_data[50]
  PIN b_cfg_data[51]
    DIRECTION OUTPUT ;
    USE SIGNAL ;
    PORT
      LAYER M4 ;
        RECT  69.036 25.968 69.12 25.992 ;
    END
  END b_cfg_data[51]
  PIN b_cfg_data[52]
    DIRECTION OUTPUT ;
    USE SIGNAL ;
    PORT
      LAYER M4 ;
        RECT  69.036 35.28 69.12 35.304 ;
    END
  END b_cfg_data[52]
  PIN b_cfg_data[53]
    DIRECTION OUTPUT ;
    USE SIGNAL ;
    PORT
      LAYER M4 ;
        RECT  69.036 35.376 69.12 35.4 ;
    END
  END b_cfg_data[53]
  PIN b_cfg_data[54]
    DIRECTION OUTPUT ;
    USE SIGNAL ;
    PORT
      LAYER M4 ;
        RECT  69.036 35.472 69.12 35.496 ;
    END
  END b_cfg_data[54]
  PIN b_cfg_data[55]
    DIRECTION OUTPUT ;
    USE SIGNAL ;
    PORT
      LAYER M4 ;
        RECT  69.036 35.568 69.12 35.592 ;
    END
  END b_cfg_data[55]
  PIN b_cfg_data[56]
    DIRECTION OUTPUT ;
    USE SIGNAL ;
    PORT
      LAYER M4 ;
        RECT  69.036 35.664 69.12 35.688 ;
    END
  END b_cfg_data[56]
  PIN b_cfg_data[57]
    DIRECTION OUTPUT ;
    USE SIGNAL ;
    PORT
      LAYER M4 ;
        RECT  69.036 35.76 69.12 35.784 ;
    END
  END b_cfg_data[57]
  PIN b_cfg_data[58]
    DIRECTION OUTPUT ;
    USE SIGNAL ;
    PORT
      LAYER M4 ;
        RECT  69.036 35.856 69.12 35.88 ;
    END
  END b_cfg_data[58]
  PIN b_cfg_data[59]
    DIRECTION OUTPUT ;
    USE SIGNAL ;
    PORT
      LAYER M4 ;
        RECT  69.036 35.952 69.12 35.976 ;
    END
  END b_cfg_data[59]
  PIN b_cfg_data[5]
    DIRECTION OUTPUT ;
    USE SIGNAL ;
    PORT
      LAYER M4 ;
        RECT  69.036 33.84 69.12 33.864 ;
    END
  END b_cfg_data[5]
  PIN b_cfg_data[60]
    DIRECTION OUTPUT ;
    USE SIGNAL ;
    PORT
      LAYER M4 ;
        RECT  69.036 36.048 69.12 36.072 ;
    END
  END b_cfg_data[60]
  PIN b_cfg_data[61]
    DIRECTION OUTPUT ;
    USE SIGNAL ;
    PORT
      LAYER M4 ;
        RECT  69.036 36.144 69.12 36.168 ;
    END
  END b_cfg_data[61]
  PIN b_cfg_data[62]
    DIRECTION OUTPUT ;
    USE SIGNAL ;
    PORT
      LAYER M4 ;
        RECT  69.036 36.24 69.12 36.264 ;
    END
  END b_cfg_data[62]
  PIN b_cfg_data[63]
    DIRECTION OUTPUT ;
    USE SIGNAL ;
    PORT
      LAYER M4 ;
        RECT  69.036 36.336 69.12 36.36 ;
    END
  END b_cfg_data[63]
  PIN b_cfg_data[64]
    DIRECTION OUTPUT ;
    USE SIGNAL ;
    PORT
      LAYER M4 ;
        RECT  69.036 36.432 69.12 36.456 ;
    END
  END b_cfg_data[64]
  PIN b_cfg_data[65]
    DIRECTION OUTPUT ;
    USE SIGNAL ;
    PORT
      LAYER M4 ;
        RECT  69.036 36.528 69.12 36.552 ;
    END
  END b_cfg_data[65]
  PIN b_cfg_data[66]
    DIRECTION OUTPUT ;
    USE SIGNAL ;
    PORT
      LAYER M4 ;
        RECT  69.036 36.624 69.12 36.648 ;
    END
  END b_cfg_data[66]
  PIN b_cfg_data[67]
    DIRECTION OUTPUT ;
    USE SIGNAL ;
    PORT
      LAYER M4 ;
        RECT  69.036 36.72 69.12 36.744 ;
    END
  END b_cfg_data[67]
  PIN b_cfg_data[68]
    DIRECTION OUTPUT ;
    USE SIGNAL ;
    PORT
      LAYER M4 ;
        RECT  69.036 36.816 69.12 36.84 ;
    END
  END b_cfg_data[68]
  PIN b_cfg_data[69]
    DIRECTION OUTPUT ;
    USE SIGNAL ;
    PORT
      LAYER M4 ;
        RECT  69.036 36.912 69.12 36.936 ;
    END
  END b_cfg_data[69]
  PIN b_cfg_data[6]
    DIRECTION OUTPUT ;
    USE SIGNAL ;
    PORT
      LAYER M4 ;
        RECT  69.036 33.936 69.12 33.96 ;
    END
  END b_cfg_data[6]
  PIN b_cfg_data[70]
    DIRECTION OUTPUT ;
    USE SIGNAL ;
    PORT
      LAYER M4 ;
        RECT  69.036 37.008 69.12 37.032 ;
    END
  END b_cfg_data[70]
  PIN b_cfg_data[71]
    DIRECTION OUTPUT ;
    USE SIGNAL ;
    PORT
      LAYER M4 ;
        RECT  69.036 37.104 69.12 37.128 ;
    END
  END b_cfg_data[71]
  PIN b_cfg_data[72]
    DIRECTION OUTPUT ;
    USE SIGNAL ;
    PORT
      LAYER M4 ;
        RECT  69.036 37.2 69.12 37.224 ;
    END
  END b_cfg_data[72]
  PIN b_cfg_data[73]
    DIRECTION OUTPUT ;
    USE SIGNAL ;
    PORT
      LAYER M4 ;
        RECT  69.036 37.296 69.12 37.32 ;
    END
  END b_cfg_data[73]
  PIN b_cfg_data[74]
    DIRECTION OUTPUT ;
    USE SIGNAL ;
    PORT
      LAYER M4 ;
        RECT  69.036 37.392 69.12 37.416 ;
    END
  END b_cfg_data[74]
  PIN b_cfg_data[75]
    DIRECTION OUTPUT ;
    USE SIGNAL ;
    PORT
      LAYER M4 ;
        RECT  69.036 37.488 69.12 37.512 ;
    END
  END b_cfg_data[75]
  PIN b_cfg_data[76]
    DIRECTION OUTPUT ;
    USE SIGNAL ;
    PORT
      LAYER M4 ;
        RECT  69.036 37.584 69.12 37.608 ;
    END
  END b_cfg_data[76]
  PIN b_cfg_data[77]
    DIRECTION OUTPUT ;
    USE SIGNAL ;
    PORT
      LAYER M4 ;
        RECT  69.036 37.68 69.12 37.704 ;
    END
  END b_cfg_data[77]
  PIN b_cfg_data[78]
    DIRECTION OUTPUT ;
    USE SIGNAL ;
    PORT
      LAYER M4 ;
        RECT  69.036 37.776 69.12 37.8 ;
    END
  END b_cfg_data[78]
  PIN b_cfg_data[79]
    DIRECTION OUTPUT ;
    USE SIGNAL ;
    PORT
      LAYER M4 ;
        RECT  69.036 37.872 69.12 37.896 ;
    END
  END b_cfg_data[79]
  PIN b_cfg_data[7]
    DIRECTION OUTPUT ;
    USE SIGNAL ;
    PORT
      LAYER M4 ;
        RECT  69.036 34.032 69.12 34.056 ;
    END
  END b_cfg_data[7]
  PIN b_cfg_data[80]
    DIRECTION OUTPUT ;
    USE SIGNAL ;
    PORT
      LAYER M4 ;
        RECT  69.036 37.968 69.12 37.992 ;
    END
  END b_cfg_data[80]
  PIN b_cfg_data[81]
    DIRECTION OUTPUT ;
    USE SIGNAL ;
    PORT
      LAYER M4 ;
        RECT  69.036 38.064 69.12 38.088 ;
    END
  END b_cfg_data[81]
  PIN b_cfg_data[82]
    DIRECTION OUTPUT ;
    USE SIGNAL ;
    PORT
      LAYER M4 ;
        RECT  69.036 38.16 69.12 38.184 ;
    END
  END b_cfg_data[82]
  PIN b_cfg_data[83]
    DIRECTION OUTPUT ;
    USE SIGNAL ;
    PORT
      LAYER M4 ;
        RECT  69.036 38.256 69.12 38.28 ;
    END
  END b_cfg_data[83]
  PIN b_cfg_data[84]
    DIRECTION OUTPUT ;
    USE SIGNAL ;
    PORT
      LAYER M4 ;
        RECT  69.036 45.264 69.12 45.288 ;
    END
  END b_cfg_data[84]
  PIN b_cfg_data[85]
    DIRECTION OUTPUT ;
    USE SIGNAL ;
    PORT
      LAYER M4 ;
        RECT  69.036 45.36 69.12 45.384 ;
    END
  END b_cfg_data[85]
  PIN b_cfg_data[86]
    DIRECTION OUTPUT ;
    USE SIGNAL ;
    PORT
      LAYER M4 ;
        RECT  69.036 45.456 69.12 45.48 ;
    END
  END b_cfg_data[86]
  PIN b_cfg_data[87]
    DIRECTION OUTPUT ;
    USE SIGNAL ;
    PORT
      LAYER M4 ;
        RECT  69.036 45.552 69.12 45.576 ;
    END
  END b_cfg_data[87]
  PIN b_cfg_data[88]
    DIRECTION OUTPUT ;
    USE SIGNAL ;
    PORT
      LAYER M4 ;
        RECT  69.036 45.648 69.12 45.672 ;
    END
  END b_cfg_data[88]
  PIN b_cfg_data[89]
    DIRECTION OUTPUT ;
    USE SIGNAL ;
    PORT
      LAYER M4 ;
        RECT  69.036 45.744 69.12 45.768 ;
    END
  END b_cfg_data[89]
  PIN b_cfg_data[8]
    DIRECTION OUTPUT ;
    USE SIGNAL ;
    PORT
      LAYER M4 ;
        RECT  69.036 34.128 69.12 34.152 ;
    END
  END b_cfg_data[8]
  PIN b_cfg_data[90]
    DIRECTION OUTPUT ;
    USE SIGNAL ;
    PORT
      LAYER M4 ;
        RECT  69.036 45.84 69.12 45.864 ;
    END
  END b_cfg_data[90]
  PIN b_cfg_data[91]
    DIRECTION OUTPUT ;
    USE SIGNAL ;
    PORT
      LAYER M4 ;
        RECT  69.036 45.936 69.12 45.96 ;
    END
  END b_cfg_data[91]
  PIN b_cfg_data[92]
    DIRECTION OUTPUT ;
    USE SIGNAL ;
    PORT
      LAYER M4 ;
        RECT  69.036 46.032 69.12 46.056 ;
    END
  END b_cfg_data[92]
  PIN b_cfg_data[93]
    DIRECTION OUTPUT ;
    USE SIGNAL ;
    PORT
      LAYER M4 ;
        RECT  69.036 46.128 69.12 46.152 ;
    END
  END b_cfg_data[93]
  PIN b_cfg_data[94]
    DIRECTION OUTPUT ;
    USE SIGNAL ;
    PORT
      LAYER M4 ;
        RECT  69.036 46.224 69.12 46.248 ;
    END
  END b_cfg_data[94]
  PIN b_cfg_data[95]
    DIRECTION OUTPUT ;
    USE SIGNAL ;
    PORT
      LAYER M4 ;
        RECT  69.036 46.32 69.12 46.344 ;
    END
  END b_cfg_data[95]
  PIN b_cfg_data[96]
    DIRECTION OUTPUT ;
    USE SIGNAL ;
    PORT
      LAYER M4 ;
        RECT  69.036 46.416 69.12 46.44 ;
    END
  END b_cfg_data[96]
  PIN b_cfg_data[97]
    DIRECTION OUTPUT ;
    USE SIGNAL ;
    PORT
      LAYER M4 ;
        RECT  69.036 46.512 69.12 46.536 ;
    END
  END b_cfg_data[97]
  PIN b_cfg_data[98]
    DIRECTION OUTPUT ;
    USE SIGNAL ;
    PORT
      LAYER M4 ;
        RECT  69.036 46.608 69.12 46.632 ;
    END
  END b_cfg_data[98]
  PIN b_cfg_data[99]
    DIRECTION OUTPUT ;
    USE SIGNAL ;
    PORT
      LAYER M4 ;
        RECT  69.036 46.704 69.12 46.728 ;
    END
  END b_cfg_data[99]
  PIN b_cfg_data[9]
    DIRECTION OUTPUT ;
    USE SIGNAL ;
    PORT
      LAYER M4 ;
        RECT  69.036 34.224 69.12 34.248 ;
    END
  END b_cfg_data[9]
  PIN b_cfg_target[0]
    DIRECTION OUTPUT ;
    USE SIGNAL ;
    PORT
      LAYER M4 ;
        RECT  69.036 43.344 69.12 43.368 ;
    END
  END b_cfg_target[0]
  PIN b_cfg_target[1]
    DIRECTION OUTPUT ;
    USE SIGNAL ;
    PORT
      LAYER M4 ;
        RECT  69.036 43.44 69.12 43.464 ;
    END
  END b_cfg_target[1]
  PIN b_cfg_target[2]
    DIRECTION OUTPUT ;
    USE SIGNAL ;
    PORT
      LAYER M4 ;
        RECT  69.036 43.536 69.12 43.56 ;
    END
  END b_cfg_target[2]
  PIN b_cfg_target[3]
    DIRECTION OUTPUT ;
    USE SIGNAL ;
    PORT
      LAYER M4 ;
        RECT  69.036 43.632 69.12 43.656 ;
    END
  END b_cfg_target[3]
  PIN b_cfg_target[4]
    DIRECTION OUTPUT ;
    USE SIGNAL ;
    PORT
      LAYER M4 ;
        RECT  69.036 43.728 69.12 43.752 ;
    END
  END b_cfg_target[4]
  PIN b_cfg_target[5]
    DIRECTION OUTPUT ;
    USE SIGNAL ;
    PORT
      LAYER M4 ;
        RECT  69.036 43.824 69.12 43.848 ;
    END
  END b_cfg_target[5]
  PIN b_cfg_target[6]
    DIRECTION OUTPUT ;
    USE SIGNAL ;
    PORT
      LAYER M4 ;
        RECT  69.036 43.92 69.12 43.944 ;
    END
  END b_cfg_target[6]
  PIN b_cfg_target[7]
    DIRECTION OUTPUT ;
    USE SIGNAL ;
    PORT
      LAYER M4 ;
        RECT  69.036 44.016 69.12 44.04 ;
    END
  END b_cfg_target[7]
  PIN b_cfg_v
    DIRECTION OUTPUT ;
    USE SIGNAL ;
    PORT
      LAYER M4 ;
        RECT  69.036 44.112 69.12 44.136 ;
    END
  END b_cfg_v
  PIN b_desc_base[0]
    DIRECTION OUTPUT ;
    USE SIGNAL ;
    PORT
      LAYER M4 ;
        RECT  69.036 44.208 69.12 44.232 ;
    END
  END b_desc_base[0]
  PIN b_desc_base[10]
    DIRECTION OUTPUT ;
    USE SIGNAL ;
    PORT
      LAYER M4 ;
        RECT  69.036 45.168 69.12 45.192 ;
    END
  END b_desc_base[10]
  PIN b_desc_base[11]
    DIRECTION OUTPUT ;
    USE SIGNAL ;
    PORT
      LAYER M4 ;
        RECT  69.036 39.12 69.12 39.144 ;
    END
  END b_desc_base[11]
  PIN b_desc_base[1]
    DIRECTION OUTPUT ;
    USE SIGNAL ;
    PORT
      LAYER M4 ;
        RECT  69.036 44.304 69.12 44.328 ;
    END
  END b_desc_base[1]
  PIN b_desc_base[2]
    DIRECTION OUTPUT ;
    USE SIGNAL ;
    PORT
      LAYER M4 ;
        RECT  69.036 44.4 69.12 44.424 ;
    END
  END b_desc_base[2]
  PIN b_desc_base[3]
    DIRECTION OUTPUT ;
    USE SIGNAL ;
    PORT
      LAYER M4 ;
        RECT  69.036 44.496 69.12 44.52 ;
    END
  END b_desc_base[3]
  PIN b_desc_base[4]
    DIRECTION OUTPUT ;
    USE SIGNAL ;
    PORT
      LAYER M4 ;
        RECT  69.036 44.592 69.12 44.616 ;
    END
  END b_desc_base[4]
  PIN b_desc_base[5]
    DIRECTION OUTPUT ;
    USE SIGNAL ;
    PORT
      LAYER M4 ;
        RECT  69.036 44.688 69.12 44.712 ;
    END
  END b_desc_base[5]
  PIN b_desc_base[6]
    DIRECTION OUTPUT ;
    USE SIGNAL ;
    PORT
      LAYER M4 ;
        RECT  69.036 44.784 69.12 44.808 ;
    END
  END b_desc_base[6]
  PIN b_desc_base[7]
    DIRECTION OUTPUT ;
    USE SIGNAL ;
    PORT
      LAYER M4 ;
        RECT  69.036 44.88 69.12 44.904 ;
    END
  END b_desc_base[7]
  PIN b_desc_base[8]
    DIRECTION OUTPUT ;
    USE SIGNAL ;
    PORT
      LAYER M4 ;
        RECT  69.036 44.976 69.12 45 ;
    END
  END b_desc_base[8]
  PIN b_desc_base[9]
    DIRECTION OUTPUT ;
    USE SIGNAL ;
    PORT
      LAYER M4 ;
        RECT  69.036 45.072 69.12 45.096 ;
    END
  END b_desc_base[9]
  PIN b_desc_limit[0]
    DIRECTION OUTPUT ;
    USE SIGNAL ;
    PORT
      LAYER M4 ;
        RECT  69.036 39.216 69.12 39.24 ;
    END
  END b_desc_limit[0]
  PIN b_desc_limit[10]
    DIRECTION OUTPUT ;
    USE SIGNAL ;
    PORT
      LAYER M4 ;
        RECT  69.036 40.176 69.12 40.2 ;
    END
  END b_desc_limit[10]
  PIN b_desc_limit[11]
    DIRECTION OUTPUT ;
    USE SIGNAL ;
    PORT
      LAYER M4 ;
        RECT  69.036 40.272 69.12 40.296 ;
    END
  END b_desc_limit[11]
  PIN b_desc_limit[12]
    DIRECTION OUTPUT ;
    USE SIGNAL ;
    PORT
      LAYER M4 ;
        RECT  69.036 40.368 69.12 40.392 ;
    END
  END b_desc_limit[12]
  PIN b_desc_limit[1]
    DIRECTION OUTPUT ;
    USE SIGNAL ;
    PORT
      LAYER M4 ;
        RECT  69.036 39.312 69.12 39.336 ;
    END
  END b_desc_limit[1]
  PIN b_desc_limit[2]
    DIRECTION OUTPUT ;
    USE SIGNAL ;
    PORT
      LAYER M4 ;
        RECT  69.036 39.408 69.12 39.432 ;
    END
  END b_desc_limit[2]
  PIN b_desc_limit[3]
    DIRECTION OUTPUT ;
    USE SIGNAL ;
    PORT
      LAYER M4 ;
        RECT  69.036 39.504 69.12 39.528 ;
    END
  END b_desc_limit[3]
  PIN b_desc_limit[4]
    DIRECTION OUTPUT ;
    USE SIGNAL ;
    PORT
      LAYER M4 ;
        RECT  69.036 39.6 69.12 39.624 ;
    END
  END b_desc_limit[4]
  PIN b_desc_limit[5]
    DIRECTION OUTPUT ;
    USE SIGNAL ;
    PORT
      LAYER M4 ;
        RECT  69.036 39.696 69.12 39.72 ;
    END
  END b_desc_limit[5]
  PIN b_desc_limit[6]
    DIRECTION OUTPUT ;
    USE SIGNAL ;
    PORT
      LAYER M4 ;
        RECT  69.036 39.792 69.12 39.816 ;
    END
  END b_desc_limit[6]
  PIN b_desc_limit[7]
    DIRECTION OUTPUT ;
    USE SIGNAL ;
    PORT
      LAYER M4 ;
        RECT  69.036 39.888 69.12 39.912 ;
    END
  END b_desc_limit[7]
  PIN b_desc_limit[8]
    DIRECTION OUTPUT ;
    USE SIGNAL ;
    PORT
      LAYER M4 ;
        RECT  69.036 39.984 69.12 40.008 ;
    END
  END b_desc_limit[8]
  PIN b_desc_limit[9]
    DIRECTION OUTPUT ;
    USE SIGNAL ;
    PORT
      LAYER M4 ;
        RECT  69.036 40.08 69.12 40.104 ;
    END
  END b_desc_limit[9]
  PIN b_desc_loops[0]
    DIRECTION OUTPUT ;
    USE SIGNAL ;
    PORT
      LAYER M4 ;
        RECT  69.036 40.464 69.12 40.488 ;
    END
  END b_desc_loops[0]
  PIN b_desc_loops[10]
    DIRECTION OUTPUT ;
    USE SIGNAL ;
    PORT
      LAYER M4 ;
        RECT  69.036 41.424 69.12 41.448 ;
    END
  END b_desc_loops[10]
  PIN b_desc_loops[11]
    DIRECTION OUTPUT ;
    USE SIGNAL ;
    PORT
      LAYER M4 ;
        RECT  69.036 41.52 69.12 41.544 ;
    END
  END b_desc_loops[11]
  PIN b_desc_loops[12]
    DIRECTION OUTPUT ;
    USE SIGNAL ;
    PORT
      LAYER M4 ;
        RECT  69.036 41.616 69.12 41.64 ;
    END
  END b_desc_loops[12]
  PIN b_desc_loops[13]
    DIRECTION OUTPUT ;
    USE SIGNAL ;
    PORT
      LAYER M4 ;
        RECT  69.036 41.712 69.12 41.736 ;
    END
  END b_desc_loops[13]
  PIN b_desc_loops[14]
    DIRECTION OUTPUT ;
    USE SIGNAL ;
    PORT
      LAYER M4 ;
        RECT  69.036 41.808 69.12 41.832 ;
    END
  END b_desc_loops[14]
  PIN b_desc_loops[15]
    DIRECTION OUTPUT ;
    USE SIGNAL ;
    PORT
      LAYER M4 ;
        RECT  69.036 41.904 69.12 41.928 ;
    END
  END b_desc_loops[15]
  PIN b_desc_loops[1]
    DIRECTION OUTPUT ;
    USE SIGNAL ;
    PORT
      LAYER M4 ;
        RECT  69.036 40.56 69.12 40.584 ;
    END
  END b_desc_loops[1]
  PIN b_desc_loops[2]
    DIRECTION OUTPUT ;
    USE SIGNAL ;
    PORT
      LAYER M4 ;
        RECT  69.036 40.656 69.12 40.68 ;
    END
  END b_desc_loops[2]
  PIN b_desc_loops[3]
    DIRECTION OUTPUT ;
    USE SIGNAL ;
    PORT
      LAYER M4 ;
        RECT  69.036 40.752 69.12 40.776 ;
    END
  END b_desc_loops[3]
  PIN b_desc_loops[4]
    DIRECTION OUTPUT ;
    USE SIGNAL ;
    PORT
      LAYER M4 ;
        RECT  69.036 40.848 69.12 40.872 ;
    END
  END b_desc_loops[4]
  PIN b_desc_loops[5]
    DIRECTION OUTPUT ;
    USE SIGNAL ;
    PORT
      LAYER M4 ;
        RECT  69.036 40.944 69.12 40.968 ;
    END
  END b_desc_loops[5]
  PIN b_desc_loops[6]
    DIRECTION OUTPUT ;
    USE SIGNAL ;
    PORT
      LAYER M4 ;
        RECT  69.036 41.04 69.12 41.064 ;
    END
  END b_desc_loops[6]
  PIN b_desc_loops[7]
    DIRECTION OUTPUT ;
    USE SIGNAL ;
    PORT
      LAYER M4 ;
        RECT  69.036 41.136 69.12 41.16 ;
    END
  END b_desc_loops[7]
  PIN b_desc_loops[8]
    DIRECTION OUTPUT ;
    USE SIGNAL ;
    PORT
      LAYER M4 ;
        RECT  69.036 41.232 69.12 41.256 ;
    END
  END b_desc_loops[8]
  PIN b_desc_loops[9]
    DIRECTION OUTPUT ;
    USE SIGNAL ;
    PORT
      LAYER M4 ;
        RECT  69.036 41.328 69.12 41.352 ;
    END
  END b_desc_loops[9]
  PIN b_desc_v
    DIRECTION OUTPUT ;
    USE SIGNAL ;
    PORT
      LAYER M4 ;
        RECT  69.036 42 69.12 42.024 ;
    END
  END b_desc_v
  PIN b_launch_v
    DIRECTION OUTPUT ;
    USE SIGNAL ;
    PORT
      LAYER M4 ;
        RECT  69.036 42.096 69.12 42.12 ;
    END
  END b_launch_v
  PIN cfg_addr[0]
    DIRECTION INPUT ;
    USE SIGNAL ;
    PORT
      LAYER M5 ;
        RECT  39.984 69.036 40.008 69.12 ;
    END
  END cfg_addr[0]
  PIN cfg_addr[10]
    DIRECTION INPUT ;
    USE SIGNAL ;
    PORT
      LAYER M5 ;
        RECT  40.944 69.036 40.968 69.12 ;
    END
  END cfg_addr[10]
  PIN cfg_addr[11]
    DIRECTION INPUT ;
    USE SIGNAL ;
    PORT
      LAYER M5 ;
        RECT  41.04 69.036 41.064 69.12 ;
    END
  END cfg_addr[11]
  PIN cfg_addr[1]
    DIRECTION INPUT ;
    USE SIGNAL ;
    PORT
      LAYER M5 ;
        RECT  40.08 69.036 40.104 69.12 ;
    END
  END cfg_addr[1]
  PIN cfg_addr[2]
    DIRECTION INPUT ;
    USE SIGNAL ;
    PORT
      LAYER M5 ;
        RECT  40.176 69.036 40.2 69.12 ;
    END
  END cfg_addr[2]
  PIN cfg_addr[3]
    DIRECTION INPUT ;
    USE SIGNAL ;
    PORT
      LAYER M5 ;
        RECT  40.272 69.036 40.296 69.12 ;
    END
  END cfg_addr[3]
  PIN cfg_addr[4]
    DIRECTION INPUT ;
    USE SIGNAL ;
    PORT
      LAYER M5 ;
        RECT  40.368 69.036 40.392 69.12 ;
    END
  END cfg_addr[4]
  PIN cfg_addr[5]
    DIRECTION INPUT ;
    USE SIGNAL ;
    PORT
      LAYER M5 ;
        RECT  40.464 69.036 40.488 69.12 ;
    END
  END cfg_addr[5]
  PIN cfg_addr[6]
    DIRECTION INPUT ;
    USE SIGNAL ;
    PORT
      LAYER M5 ;
        RECT  40.56 69.036 40.584 69.12 ;
    END
  END cfg_addr[6]
  PIN cfg_addr[7]
    DIRECTION INPUT ;
    USE SIGNAL ;
    PORT
      LAYER M5 ;
        RECT  40.656 69.036 40.68 69.12 ;
    END
  END cfg_addr[7]
  PIN cfg_addr[8]
    DIRECTION INPUT ;
    USE SIGNAL ;
    PORT
      LAYER M5 ;
        RECT  40.752 69.036 40.776 69.12 ;
    END
  END cfg_addr[8]
  PIN cfg_addr[9]
    DIRECTION INPUT ;
    USE SIGNAL ;
    PORT
      LAYER M5 ;
        RECT  40.848 69.036 40.872 69.12 ;
    END
  END cfg_addr[9]
  PIN cfg_data[0]
    DIRECTION INPUT ;
    USE SIGNAL ;
    PORT
      LAYER M5 ;
        RECT  41.136 69.036 41.16 69.12 ;
    END
  END cfg_data[0]
  PIN cfg_data[100]
    DIRECTION INPUT ;
    USE SIGNAL ;
    PORT
      LAYER M5 ;
        RECT  44.592 69.036 44.616 69.12 ;
    END
  END cfg_data[100]
  PIN cfg_data[101]
    DIRECTION INPUT ;
    USE SIGNAL ;
    PORT
      LAYER M5 ;
        RECT  44.688 69.036 44.712 69.12 ;
    END
  END cfg_data[101]
  PIN cfg_data[102]
    DIRECTION INPUT ;
    USE SIGNAL ;
    PORT
      LAYER M5 ;
        RECT  44.784 69.036 44.808 69.12 ;
    END
  END cfg_data[102]
  PIN cfg_data[103]
    DIRECTION INPUT ;
    USE SIGNAL ;
    PORT
      LAYER M5 ;
        RECT  44.88 69.036 44.904 69.12 ;
    END
  END cfg_data[103]
  PIN cfg_data[104]
    DIRECTION INPUT ;
    USE SIGNAL ;
    PORT
      LAYER M5 ;
        RECT  44.976 69.036 45 69.12 ;
    END
  END cfg_data[104]
  PIN cfg_data[105]
    DIRECTION INPUT ;
    USE SIGNAL ;
    PORT
      LAYER M5 ;
        RECT  45.072 69.036 45.096 69.12 ;
    END
  END cfg_data[105]
  PIN cfg_data[106]
    DIRECTION INPUT ;
    USE SIGNAL ;
    PORT
      LAYER M5 ;
        RECT  45.168 69.036 45.192 69.12 ;
    END
  END cfg_data[106]
  PIN cfg_data[107]
    DIRECTION INPUT ;
    USE SIGNAL ;
    PORT
      LAYER M5 ;
        RECT  45.264 69.036 45.288 69.12 ;
    END
  END cfg_data[107]
  PIN cfg_data[108]
    DIRECTION INPUT ;
    USE SIGNAL ;
    PORT
      LAYER M5 ;
        RECT  45.36 69.036 45.384 69.12 ;
    END
  END cfg_data[108]
  PIN cfg_data[109]
    DIRECTION INPUT ;
    USE SIGNAL ;
    PORT
      LAYER M5 ;
        RECT  45.456 69.036 45.48 69.12 ;
    END
  END cfg_data[109]
  PIN cfg_data[10]
    DIRECTION INPUT ;
    USE SIGNAL ;
    PORT
      LAYER M5 ;
        RECT  42.096 69.036 42.12 69.12 ;
    END
  END cfg_data[10]
  PIN cfg_data[110]
    DIRECTION INPUT ;
    USE SIGNAL ;
    PORT
      LAYER M5 ;
        RECT  45.552 69.036 45.576 69.12 ;
    END
  END cfg_data[110]
  PIN cfg_data[111]
    DIRECTION INPUT ;
    USE SIGNAL ;
    PORT
      LAYER M5 ;
        RECT  45.648 69.036 45.672 69.12 ;
    END
  END cfg_data[111]
  PIN cfg_data[112]
    DIRECTION INPUT ;
    USE SIGNAL ;
    PORT
      LAYER M5 ;
        RECT  45.744 69.036 45.768 69.12 ;
    END
  END cfg_data[112]
  PIN cfg_data[113]
    DIRECTION INPUT ;
    USE SIGNAL ;
    PORT
      LAYER M5 ;
        RECT  45.84 69.036 45.864 69.12 ;
    END
  END cfg_data[113]
  PIN cfg_data[114]
    DIRECTION INPUT ;
    USE SIGNAL ;
    PORT
      LAYER M5 ;
        RECT  45.936 69.036 45.96 69.12 ;
    END
  END cfg_data[114]
  PIN cfg_data[115]
    DIRECTION INPUT ;
    USE SIGNAL ;
    PORT
      LAYER M5 ;
        RECT  46.032 69.036 46.056 69.12 ;
    END
  END cfg_data[115]
  PIN cfg_data[116]
    DIRECTION INPUT ;
    USE SIGNAL ;
    PORT
      LAYER M5 ;
        RECT  36.912 69.036 36.936 69.12 ;
    END
  END cfg_data[116]
  PIN cfg_data[117]
    DIRECTION INPUT ;
    USE SIGNAL ;
    PORT
      LAYER M5 ;
        RECT  37.008 69.036 37.032 69.12 ;
    END
  END cfg_data[117]
  PIN cfg_data[118]
    DIRECTION INPUT ;
    USE SIGNAL ;
    PORT
      LAYER M5 ;
        RECT  37.104 69.036 37.128 69.12 ;
    END
  END cfg_data[118]
  PIN cfg_data[119]
    DIRECTION INPUT ;
    USE SIGNAL ;
    PORT
      LAYER M5 ;
        RECT  37.2 69.036 37.224 69.12 ;
    END
  END cfg_data[119]
  PIN cfg_data[11]
    DIRECTION INPUT ;
    USE SIGNAL ;
    PORT
      LAYER M5 ;
        RECT  42.192 69.036 42.216 69.12 ;
    END
  END cfg_data[11]
  PIN cfg_data[120]
    DIRECTION INPUT ;
    USE SIGNAL ;
    PORT
      LAYER M5 ;
        RECT  37.296 69.036 37.32 69.12 ;
    END
  END cfg_data[120]
  PIN cfg_data[121]
    DIRECTION INPUT ;
    USE SIGNAL ;
    PORT
      LAYER M5 ;
        RECT  37.392 69.036 37.416 69.12 ;
    END
  END cfg_data[121]
  PIN cfg_data[122]
    DIRECTION INPUT ;
    USE SIGNAL ;
    PORT
      LAYER M5 ;
        RECT  37.488 69.036 37.512 69.12 ;
    END
  END cfg_data[122]
  PIN cfg_data[123]
    DIRECTION INPUT ;
    USE SIGNAL ;
    PORT
      LAYER M5 ;
        RECT  37.584 69.036 37.608 69.12 ;
    END
  END cfg_data[123]
  PIN cfg_data[124]
    DIRECTION INPUT ;
    USE SIGNAL ;
    PORT
      LAYER M5 ;
        RECT  37.68 69.036 37.704 69.12 ;
    END
  END cfg_data[124]
  PIN cfg_data[125]
    DIRECTION INPUT ;
    USE SIGNAL ;
    PORT
      LAYER M5 ;
        RECT  37.776 69.036 37.8 69.12 ;
    END
  END cfg_data[125]
  PIN cfg_data[126]
    DIRECTION INPUT ;
    USE SIGNAL ;
    PORT
      LAYER M5 ;
        RECT  37.872 69.036 37.896 69.12 ;
    END
  END cfg_data[126]
  PIN cfg_data[127]
    DIRECTION INPUT ;
    USE SIGNAL ;
    PORT
      LAYER M5 ;
        RECT  37.968 69.036 37.992 69.12 ;
    END
  END cfg_data[127]
  PIN cfg_data[128]
    DIRECTION INPUT ;
    USE SIGNAL ;
    PORT
      LAYER M5 ;
        RECT  38.064 69.036 38.088 69.12 ;
    END
  END cfg_data[128]
  PIN cfg_data[129]
    DIRECTION INPUT ;
    USE SIGNAL ;
    PORT
      LAYER M5 ;
        RECT  38.16 69.036 38.184 69.12 ;
    END
  END cfg_data[129]
  PIN cfg_data[12]
    DIRECTION INPUT ;
    USE SIGNAL ;
    PORT
      LAYER M5 ;
        RECT  42.288 69.036 42.312 69.12 ;
    END
  END cfg_data[12]
  PIN cfg_data[130]
    DIRECTION INPUT ;
    USE SIGNAL ;
    PORT
      LAYER M5 ;
        RECT  38.256 69.036 38.28 69.12 ;
    END
  END cfg_data[130]
  PIN cfg_data[131]
    DIRECTION INPUT ;
    USE SIGNAL ;
    PORT
      LAYER M5 ;
        RECT  38.352 69.036 38.376 69.12 ;
    END
  END cfg_data[131]
  PIN cfg_data[132]
    DIRECTION INPUT ;
    USE SIGNAL ;
    PORT
      LAYER M5 ;
        RECT  38.448 69.036 38.472 69.12 ;
    END
  END cfg_data[132]
  PIN cfg_data[133]
    DIRECTION INPUT ;
    USE SIGNAL ;
    PORT
      LAYER M5 ;
        RECT  38.544 69.036 38.568 69.12 ;
    END
  END cfg_data[133]
  PIN cfg_data[134]
    DIRECTION INPUT ;
    USE SIGNAL ;
    PORT
      LAYER M5 ;
        RECT  38.64 69.036 38.664 69.12 ;
    END
  END cfg_data[134]
  PIN cfg_data[135]
    DIRECTION INPUT ;
    USE SIGNAL ;
    PORT
      LAYER M5 ;
        RECT  38.736 69.036 38.76 69.12 ;
    END
  END cfg_data[135]
  PIN cfg_data[136]
    DIRECTION INPUT ;
    USE SIGNAL ;
    PORT
      LAYER M5 ;
        RECT  38.832 69.036 38.856 69.12 ;
    END
  END cfg_data[136]
  PIN cfg_data[137]
    DIRECTION INPUT ;
    USE SIGNAL ;
    PORT
      LAYER M5 ;
        RECT  38.928 69.036 38.952 69.12 ;
    END
  END cfg_data[137]
  PIN cfg_data[138]
    DIRECTION INPUT ;
    USE SIGNAL ;
    PORT
      LAYER M5 ;
        RECT  39.024 69.036 39.048 69.12 ;
    END
  END cfg_data[138]
  PIN cfg_data[139]
    DIRECTION INPUT ;
    USE SIGNAL ;
    PORT
      LAYER M5 ;
        RECT  39.12 69.036 39.144 69.12 ;
    END
  END cfg_data[139]
  PIN cfg_data[13]
    DIRECTION INPUT ;
    USE SIGNAL ;
    PORT
      LAYER M5 ;
        RECT  42.384 69.036 42.408 69.12 ;
    END
  END cfg_data[13]
  PIN cfg_data[140]
    DIRECTION INPUT ;
    USE SIGNAL ;
    PORT
      LAYER M5 ;
        RECT  39.216 69.036 39.24 69.12 ;
    END
  END cfg_data[140]
  PIN cfg_data[141]
    DIRECTION INPUT ;
    USE SIGNAL ;
    PORT
      LAYER M5 ;
        RECT  39.312 69.036 39.336 69.12 ;
    END
  END cfg_data[141]
  PIN cfg_data[142]
    DIRECTION INPUT ;
    USE SIGNAL ;
    PORT
      LAYER M5 ;
        RECT  39.408 69.036 39.432 69.12 ;
    END
  END cfg_data[142]
  PIN cfg_data[143]
    DIRECTION INPUT ;
    USE SIGNAL ;
    PORT
      LAYER M5 ;
        RECT  39.504 69.036 39.528 69.12 ;
    END
  END cfg_data[143]
  PIN cfg_data[144]
    DIRECTION INPUT ;
    USE SIGNAL ;
    PORT
      LAYER M5 ;
        RECT  39.6 69.036 39.624 69.12 ;
    END
  END cfg_data[144]
  PIN cfg_data[145]
    DIRECTION INPUT ;
    USE SIGNAL ;
    PORT
      LAYER M5 ;
        RECT  39.696 69.036 39.72 69.12 ;
    END
  END cfg_data[145]
  PIN cfg_data[146]
    DIRECTION INPUT ;
    USE SIGNAL ;
    PORT
      LAYER M5 ;
        RECT  39.792 69.036 39.816 69.12 ;
    END
  END cfg_data[146]
  PIN cfg_data[147]
    DIRECTION INPUT ;
    USE SIGNAL ;
    PORT
      LAYER M5 ;
        RECT  39.888 69.036 39.912 69.12 ;
    END
  END cfg_data[147]
  PIN cfg_data[148]
    DIRECTION INPUT ;
    USE SIGNAL ;
    PORT
      LAYER M5 ;
        RECT  30.768 69.036 30.792 69.12 ;
    END
  END cfg_data[148]
  PIN cfg_data[149]
    DIRECTION INPUT ;
    USE SIGNAL ;
    PORT
      LAYER M5 ;
        RECT  30.864 69.036 30.888 69.12 ;
    END
  END cfg_data[149]
  PIN cfg_data[14]
    DIRECTION INPUT ;
    USE SIGNAL ;
    PORT
      LAYER M5 ;
        RECT  42.48 69.036 42.504 69.12 ;
    END
  END cfg_data[14]
  PIN cfg_data[150]
    DIRECTION INPUT ;
    USE SIGNAL ;
    PORT
      LAYER M5 ;
        RECT  30.96 69.036 30.984 69.12 ;
    END
  END cfg_data[150]
  PIN cfg_data[151]
    DIRECTION INPUT ;
    USE SIGNAL ;
    PORT
      LAYER M5 ;
        RECT  31.056 69.036 31.08 69.12 ;
    END
  END cfg_data[151]
  PIN cfg_data[152]
    DIRECTION INPUT ;
    USE SIGNAL ;
    PORT
      LAYER M5 ;
        RECT  31.152 69.036 31.176 69.12 ;
    END
  END cfg_data[152]
  PIN cfg_data[153]
    DIRECTION INPUT ;
    USE SIGNAL ;
    PORT
      LAYER M5 ;
        RECT  31.248 69.036 31.272 69.12 ;
    END
  END cfg_data[153]
  PIN cfg_data[154]
    DIRECTION INPUT ;
    USE SIGNAL ;
    PORT
      LAYER M5 ;
        RECT  31.344 69.036 31.368 69.12 ;
    END
  END cfg_data[154]
  PIN cfg_data[155]
    DIRECTION INPUT ;
    USE SIGNAL ;
    PORT
      LAYER M5 ;
        RECT  31.44 69.036 31.464 69.12 ;
    END
  END cfg_data[155]
  PIN cfg_data[156]
    DIRECTION INPUT ;
    USE SIGNAL ;
    PORT
      LAYER M5 ;
        RECT  31.536 69.036 31.56 69.12 ;
    END
  END cfg_data[156]
  PIN cfg_data[157]
    DIRECTION INPUT ;
    USE SIGNAL ;
    PORT
      LAYER M5 ;
        RECT  31.632 69.036 31.656 69.12 ;
    END
  END cfg_data[157]
  PIN cfg_data[158]
    DIRECTION INPUT ;
    USE SIGNAL ;
    PORT
      LAYER M5 ;
        RECT  31.728 69.036 31.752 69.12 ;
    END
  END cfg_data[158]
  PIN cfg_data[159]
    DIRECTION INPUT ;
    USE SIGNAL ;
    PORT
      LAYER M5 ;
        RECT  31.824 69.036 31.848 69.12 ;
    END
  END cfg_data[159]
  PIN cfg_data[15]
    DIRECTION INPUT ;
    USE SIGNAL ;
    PORT
      LAYER M5 ;
        RECT  42.576 69.036 42.6 69.12 ;
    END
  END cfg_data[15]
  PIN cfg_data[160]
    DIRECTION INPUT ;
    USE SIGNAL ;
    PORT
      LAYER M5 ;
        RECT  31.92 69.036 31.944 69.12 ;
    END
  END cfg_data[160]
  PIN cfg_data[161]
    DIRECTION INPUT ;
    USE SIGNAL ;
    PORT
      LAYER M5 ;
        RECT  32.016 69.036 32.04 69.12 ;
    END
  END cfg_data[161]
  PIN cfg_data[162]
    DIRECTION INPUT ;
    USE SIGNAL ;
    PORT
      LAYER M5 ;
        RECT  32.112 69.036 32.136 69.12 ;
    END
  END cfg_data[162]
  PIN cfg_data[163]
    DIRECTION INPUT ;
    USE SIGNAL ;
    PORT
      LAYER M5 ;
        RECT  32.208 69.036 32.232 69.12 ;
    END
  END cfg_data[163]
  PIN cfg_data[164]
    DIRECTION INPUT ;
    USE SIGNAL ;
    PORT
      LAYER M5 ;
        RECT  32.304 69.036 32.328 69.12 ;
    END
  END cfg_data[164]
  PIN cfg_data[165]
    DIRECTION INPUT ;
    USE SIGNAL ;
    PORT
      LAYER M5 ;
        RECT  32.4 69.036 32.424 69.12 ;
    END
  END cfg_data[165]
  PIN cfg_data[166]
    DIRECTION INPUT ;
    USE SIGNAL ;
    PORT
      LAYER M5 ;
        RECT  32.496 69.036 32.52 69.12 ;
    END
  END cfg_data[166]
  PIN cfg_data[167]
    DIRECTION INPUT ;
    USE SIGNAL ;
    PORT
      LAYER M5 ;
        RECT  32.592 69.036 32.616 69.12 ;
    END
  END cfg_data[167]
  PIN cfg_data[168]
    DIRECTION INPUT ;
    USE SIGNAL ;
    PORT
      LAYER M5 ;
        RECT  32.688 69.036 32.712 69.12 ;
    END
  END cfg_data[168]
  PIN cfg_data[169]
    DIRECTION INPUT ;
    USE SIGNAL ;
    PORT
      LAYER M5 ;
        RECT  32.784 69.036 32.808 69.12 ;
    END
  END cfg_data[169]
  PIN cfg_data[16]
    DIRECTION INPUT ;
    USE SIGNAL ;
    PORT
      LAYER M5 ;
        RECT  42.672 69.036 42.696 69.12 ;
    END
  END cfg_data[16]
  PIN cfg_data[170]
    DIRECTION INPUT ;
    USE SIGNAL ;
    PORT
      LAYER M5 ;
        RECT  32.88 69.036 32.904 69.12 ;
    END
  END cfg_data[170]
  PIN cfg_data[171]
    DIRECTION INPUT ;
    USE SIGNAL ;
    PORT
      LAYER M5 ;
        RECT  32.976 69.036 33 69.12 ;
    END
  END cfg_data[171]
  PIN cfg_data[172]
    DIRECTION INPUT ;
    USE SIGNAL ;
    PORT
      LAYER M5 ;
        RECT  33.072 69.036 33.096 69.12 ;
    END
  END cfg_data[172]
  PIN cfg_data[173]
    DIRECTION INPUT ;
    USE SIGNAL ;
    PORT
      LAYER M5 ;
        RECT  33.168 69.036 33.192 69.12 ;
    END
  END cfg_data[173]
  PIN cfg_data[174]
    DIRECTION INPUT ;
    USE SIGNAL ;
    PORT
      LAYER M5 ;
        RECT  33.264 69.036 33.288 69.12 ;
    END
  END cfg_data[174]
  PIN cfg_data[175]
    DIRECTION INPUT ;
    USE SIGNAL ;
    PORT
      LAYER M5 ;
        RECT  33.36 69.036 33.384 69.12 ;
    END
  END cfg_data[175]
  PIN cfg_data[176]
    DIRECTION INPUT ;
    USE SIGNAL ;
    PORT
      LAYER M5 ;
        RECT  33.456 69.036 33.48 69.12 ;
    END
  END cfg_data[176]
  PIN cfg_data[177]
    DIRECTION INPUT ;
    USE SIGNAL ;
    PORT
      LAYER M5 ;
        RECT  33.552 69.036 33.576 69.12 ;
    END
  END cfg_data[177]
  PIN cfg_data[178]
    DIRECTION INPUT ;
    USE SIGNAL ;
    PORT
      LAYER M5 ;
        RECT  33.648 69.036 33.672 69.12 ;
    END
  END cfg_data[178]
  PIN cfg_data[179]
    DIRECTION INPUT ;
    USE SIGNAL ;
    PORT
      LAYER M5 ;
        RECT  33.744 69.036 33.768 69.12 ;
    END
  END cfg_data[179]
  PIN cfg_data[17]
    DIRECTION INPUT ;
    USE SIGNAL ;
    PORT
      LAYER M5 ;
        RECT  42.768 69.036 42.792 69.12 ;
    END
  END cfg_data[17]
  PIN cfg_data[180]
    DIRECTION INPUT ;
    USE SIGNAL ;
    PORT
      LAYER M5 ;
        RECT  46.128 69.036 46.152 69.12 ;
    END
  END cfg_data[180]
  PIN cfg_data[181]
    DIRECTION INPUT ;
    USE SIGNAL ;
    PORT
      LAYER M5 ;
        RECT  46.224 69.036 46.248 69.12 ;
    END
  END cfg_data[181]
  PIN cfg_data[182]
    DIRECTION INPUT ;
    USE SIGNAL ;
    PORT
      LAYER M5 ;
        RECT  46.32 69.036 46.344 69.12 ;
    END
  END cfg_data[182]
  PIN cfg_data[183]
    DIRECTION INPUT ;
    USE SIGNAL ;
    PORT
      LAYER M5 ;
        RECT  46.416 69.036 46.44 69.12 ;
    END
  END cfg_data[183]
  PIN cfg_data[184]
    DIRECTION INPUT ;
    USE SIGNAL ;
    PORT
      LAYER M5 ;
        RECT  46.512 69.036 46.536 69.12 ;
    END
  END cfg_data[184]
  PIN cfg_data[185]
    DIRECTION INPUT ;
    USE SIGNAL ;
    PORT
      LAYER M5 ;
        RECT  46.608 69.036 46.632 69.12 ;
    END
  END cfg_data[185]
  PIN cfg_data[186]
    DIRECTION INPUT ;
    USE SIGNAL ;
    PORT
      LAYER M5 ;
        RECT  46.704 69.036 46.728 69.12 ;
    END
  END cfg_data[186]
  PIN cfg_data[187]
    DIRECTION INPUT ;
    USE SIGNAL ;
    PORT
      LAYER M5 ;
        RECT  46.8 69.036 46.824 69.12 ;
    END
  END cfg_data[187]
  PIN cfg_data[188]
    DIRECTION INPUT ;
    USE SIGNAL ;
    PORT
      LAYER M5 ;
        RECT  46.896 69.036 46.92 69.12 ;
    END
  END cfg_data[188]
  PIN cfg_data[189]
    DIRECTION INPUT ;
    USE SIGNAL ;
    PORT
      LAYER M5 ;
        RECT  46.992 69.036 47.016 69.12 ;
    END
  END cfg_data[189]
  PIN cfg_data[18]
    DIRECTION INPUT ;
    USE SIGNAL ;
    PORT
      LAYER M5 ;
        RECT  42.864 69.036 42.888 69.12 ;
    END
  END cfg_data[18]
  PIN cfg_data[190]
    DIRECTION INPUT ;
    USE SIGNAL ;
    PORT
      LAYER M5 ;
        RECT  47.088 69.036 47.112 69.12 ;
    END
  END cfg_data[190]
  PIN cfg_data[191]
    DIRECTION INPUT ;
    USE SIGNAL ;
    PORT
      LAYER M5 ;
        RECT  47.184 69.036 47.208 69.12 ;
    END
  END cfg_data[191]
  PIN cfg_data[192]
    DIRECTION INPUT ;
    USE SIGNAL ;
    PORT
      LAYER M5 ;
        RECT  47.28 69.036 47.304 69.12 ;
    END
  END cfg_data[192]
  PIN cfg_data[193]
    DIRECTION INPUT ;
    USE SIGNAL ;
    PORT
      LAYER M5 ;
        RECT  47.376 69.036 47.4 69.12 ;
    END
  END cfg_data[193]
  PIN cfg_data[194]
    DIRECTION INPUT ;
    USE SIGNAL ;
    PORT
      LAYER M5 ;
        RECT  47.472 69.036 47.496 69.12 ;
    END
  END cfg_data[194]
  PIN cfg_data[195]
    DIRECTION INPUT ;
    USE SIGNAL ;
    PORT
      LAYER M5 ;
        RECT  47.568 69.036 47.592 69.12 ;
    END
  END cfg_data[195]
  PIN cfg_data[196]
    DIRECTION INPUT ;
    USE SIGNAL ;
    PORT
      LAYER M5 ;
        RECT  47.664 69.036 47.688 69.12 ;
    END
  END cfg_data[196]
  PIN cfg_data[197]
    DIRECTION INPUT ;
    USE SIGNAL ;
    PORT
      LAYER M5 ;
        RECT  47.76 69.036 47.784 69.12 ;
    END
  END cfg_data[197]
  PIN cfg_data[198]
    DIRECTION INPUT ;
    USE SIGNAL ;
    PORT
      LAYER M5 ;
        RECT  47.856 69.036 47.88 69.12 ;
    END
  END cfg_data[198]
  PIN cfg_data[199]
    DIRECTION INPUT ;
    USE SIGNAL ;
    PORT
      LAYER M5 ;
        RECT  47.952 69.036 47.976 69.12 ;
    END
  END cfg_data[199]
  PIN cfg_data[19]
    DIRECTION INPUT ;
    USE SIGNAL ;
    PORT
      LAYER M5 ;
        RECT  42.96 69.036 42.984 69.12 ;
    END
  END cfg_data[19]
  PIN cfg_data[1]
    DIRECTION INPUT ;
    USE SIGNAL ;
    PORT
      LAYER M5 ;
        RECT  41.232 69.036 41.256 69.12 ;
    END
  END cfg_data[1]
  PIN cfg_data[200]
    DIRECTION INPUT ;
    USE SIGNAL ;
    PORT
      LAYER M5 ;
        RECT  48.048 69.036 48.072 69.12 ;
    END
  END cfg_data[200]
  PIN cfg_data[201]
    DIRECTION INPUT ;
    USE SIGNAL ;
    PORT
      LAYER M5 ;
        RECT  48.144 69.036 48.168 69.12 ;
    END
  END cfg_data[201]
  PIN cfg_data[202]
    DIRECTION INPUT ;
    USE SIGNAL ;
    PORT
      LAYER M5 ;
        RECT  48.24 69.036 48.264 69.12 ;
    END
  END cfg_data[202]
  PIN cfg_data[203]
    DIRECTION INPUT ;
    USE SIGNAL ;
    PORT
      LAYER M5 ;
        RECT  48.336 69.036 48.36 69.12 ;
    END
  END cfg_data[203]
  PIN cfg_data[204]
    DIRECTION INPUT ;
    USE SIGNAL ;
    PORT
      LAYER M5 ;
        RECT  48.432 69.036 48.456 69.12 ;
    END
  END cfg_data[204]
  PIN cfg_data[205]
    DIRECTION INPUT ;
    USE SIGNAL ;
    PORT
      LAYER M5 ;
        RECT  48.528 69.036 48.552 69.12 ;
    END
  END cfg_data[205]
  PIN cfg_data[206]
    DIRECTION INPUT ;
    USE SIGNAL ;
    PORT
      LAYER M5 ;
        RECT  48.624 69.036 48.648 69.12 ;
    END
  END cfg_data[206]
  PIN cfg_data[207]
    DIRECTION INPUT ;
    USE SIGNAL ;
    PORT
      LAYER M5 ;
        RECT  48.72 69.036 48.744 69.12 ;
    END
  END cfg_data[207]
  PIN cfg_data[208]
    DIRECTION INPUT ;
    USE SIGNAL ;
    PORT
      LAYER M5 ;
        RECT  48.816 69.036 48.84 69.12 ;
    END
  END cfg_data[208]
  PIN cfg_data[209]
    DIRECTION INPUT ;
    USE SIGNAL ;
    PORT
      LAYER M5 ;
        RECT  48.912 69.036 48.936 69.12 ;
    END
  END cfg_data[209]
  PIN cfg_data[20]
    DIRECTION INPUT ;
    USE SIGNAL ;
    PORT
      LAYER M5 ;
        RECT  20.784 69.036 20.808 69.12 ;
    END
  END cfg_data[20]
  PIN cfg_data[210]
    DIRECTION INPUT ;
    USE SIGNAL ;
    PORT
      LAYER M5 ;
        RECT  49.008 69.036 49.032 69.12 ;
    END
  END cfg_data[210]
  PIN cfg_data[211]
    DIRECTION INPUT ;
    USE SIGNAL ;
    PORT
      LAYER M5 ;
        RECT  49.104 69.036 49.128 69.12 ;
    END
  END cfg_data[211]
  PIN cfg_data[212]
    DIRECTION INPUT ;
    USE SIGNAL ;
    PORT
      LAYER M5 ;
        RECT  23.856 69.036 23.88 69.12 ;
    END
  END cfg_data[212]
  PIN cfg_data[213]
    DIRECTION INPUT ;
    USE SIGNAL ;
    PORT
      LAYER M5 ;
        RECT  23.952 69.036 23.976 69.12 ;
    END
  END cfg_data[213]
  PIN cfg_data[214]
    DIRECTION INPUT ;
    USE SIGNAL ;
    PORT
      LAYER M5 ;
        RECT  24.048 69.036 24.072 69.12 ;
    END
  END cfg_data[214]
  PIN cfg_data[215]
    DIRECTION INPUT ;
    USE SIGNAL ;
    PORT
      LAYER M5 ;
        RECT  24.144 69.036 24.168 69.12 ;
    END
  END cfg_data[215]
  PIN cfg_data[216]
    DIRECTION INPUT ;
    USE SIGNAL ;
    PORT
      LAYER M5 ;
        RECT  24.24 69.036 24.264 69.12 ;
    END
  END cfg_data[216]
  PIN cfg_data[217]
    DIRECTION INPUT ;
    USE SIGNAL ;
    PORT
      LAYER M5 ;
        RECT  24.336 69.036 24.36 69.12 ;
    END
  END cfg_data[217]
  PIN cfg_data[218]
    DIRECTION INPUT ;
    USE SIGNAL ;
    PORT
      LAYER M5 ;
        RECT  24.432 69.036 24.456 69.12 ;
    END
  END cfg_data[218]
  PIN cfg_data[219]
    DIRECTION INPUT ;
    USE SIGNAL ;
    PORT
      LAYER M5 ;
        RECT  24.528 69.036 24.552 69.12 ;
    END
  END cfg_data[219]
  PIN cfg_data[21]
    DIRECTION INPUT ;
    USE SIGNAL ;
    PORT
      LAYER M5 ;
        RECT  20.88 69.036 20.904 69.12 ;
    END
  END cfg_data[21]
  PIN cfg_data[220]
    DIRECTION INPUT ;
    USE SIGNAL ;
    PORT
      LAYER M5 ;
        RECT  24.624 69.036 24.648 69.12 ;
    END
  END cfg_data[220]
  PIN cfg_data[221]
    DIRECTION INPUT ;
    USE SIGNAL ;
    PORT
      LAYER M5 ;
        RECT  24.72 69.036 24.744 69.12 ;
    END
  END cfg_data[221]
  PIN cfg_data[222]
    DIRECTION INPUT ;
    USE SIGNAL ;
    PORT
      LAYER M5 ;
        RECT  24.816 69.036 24.84 69.12 ;
    END
  END cfg_data[222]
  PIN cfg_data[223]
    DIRECTION INPUT ;
    USE SIGNAL ;
    PORT
      LAYER M5 ;
        RECT  24.912 69.036 24.936 69.12 ;
    END
  END cfg_data[223]
  PIN cfg_data[224]
    DIRECTION INPUT ;
    USE SIGNAL ;
    PORT
      LAYER M5 ;
        RECT  25.008 69.036 25.032 69.12 ;
    END
  END cfg_data[224]
  PIN cfg_data[225]
    DIRECTION INPUT ;
    USE SIGNAL ;
    PORT
      LAYER M5 ;
        RECT  25.104 69.036 25.128 69.12 ;
    END
  END cfg_data[225]
  PIN cfg_data[226]
    DIRECTION INPUT ;
    USE SIGNAL ;
    PORT
      LAYER M5 ;
        RECT  25.2 69.036 25.224 69.12 ;
    END
  END cfg_data[226]
  PIN cfg_data[227]
    DIRECTION INPUT ;
    USE SIGNAL ;
    PORT
      LAYER M5 ;
        RECT  25.296 69.036 25.32 69.12 ;
    END
  END cfg_data[227]
  PIN cfg_data[228]
    DIRECTION INPUT ;
    USE SIGNAL ;
    PORT
      LAYER M5 ;
        RECT  25.392 69.036 25.416 69.12 ;
    END
  END cfg_data[228]
  PIN cfg_data[229]
    DIRECTION INPUT ;
    USE SIGNAL ;
    PORT
      LAYER M5 ;
        RECT  25.488 69.036 25.512 69.12 ;
    END
  END cfg_data[229]
  PIN cfg_data[22]
    DIRECTION INPUT ;
    USE SIGNAL ;
    PORT
      LAYER M5 ;
        RECT  20.976 69.036 21 69.12 ;
    END
  END cfg_data[22]
  PIN cfg_data[230]
    DIRECTION INPUT ;
    USE SIGNAL ;
    PORT
      LAYER M5 ;
        RECT  25.584 69.036 25.608 69.12 ;
    END
  END cfg_data[230]
  PIN cfg_data[231]
    DIRECTION INPUT ;
    USE SIGNAL ;
    PORT
      LAYER M5 ;
        RECT  25.68 69.036 25.704 69.12 ;
    END
  END cfg_data[231]
  PIN cfg_data[232]
    DIRECTION INPUT ;
    USE SIGNAL ;
    PORT
      LAYER M5 ;
        RECT  25.776 69.036 25.8 69.12 ;
    END
  END cfg_data[232]
  PIN cfg_data[233]
    DIRECTION INPUT ;
    USE SIGNAL ;
    PORT
      LAYER M5 ;
        RECT  25.872 69.036 25.896 69.12 ;
    END
  END cfg_data[233]
  PIN cfg_data[234]
    DIRECTION INPUT ;
    USE SIGNAL ;
    PORT
      LAYER M5 ;
        RECT  25.968 69.036 25.992 69.12 ;
    END
  END cfg_data[234]
  PIN cfg_data[235]
    DIRECTION INPUT ;
    USE SIGNAL ;
    PORT
      LAYER M5 ;
        RECT  26.064 69.036 26.088 69.12 ;
    END
  END cfg_data[235]
  PIN cfg_data[236]
    DIRECTION INPUT ;
    USE SIGNAL ;
    PORT
      LAYER M5 ;
        RECT  26.16 69.036 26.184 69.12 ;
    END
  END cfg_data[236]
  PIN cfg_data[237]
    DIRECTION INPUT ;
    USE SIGNAL ;
    PORT
      LAYER M5 ;
        RECT  26.256 69.036 26.28 69.12 ;
    END
  END cfg_data[237]
  PIN cfg_data[238]
    DIRECTION INPUT ;
    USE SIGNAL ;
    PORT
      LAYER M5 ;
        RECT  26.352 69.036 26.376 69.12 ;
    END
  END cfg_data[238]
  PIN cfg_data[239]
    DIRECTION INPUT ;
    USE SIGNAL ;
    PORT
      LAYER M5 ;
        RECT  26.448 69.036 26.472 69.12 ;
    END
  END cfg_data[239]
  PIN cfg_data[23]
    DIRECTION INPUT ;
    USE SIGNAL ;
    PORT
      LAYER M5 ;
        RECT  21.072 69.036 21.096 69.12 ;
    END
  END cfg_data[23]
  PIN cfg_data[240]
    DIRECTION INPUT ;
    USE SIGNAL ;
    PORT
      LAYER M5 ;
        RECT  26.544 69.036 26.568 69.12 ;
    END
  END cfg_data[240]
  PIN cfg_data[241]
    DIRECTION INPUT ;
    USE SIGNAL ;
    PORT
      LAYER M5 ;
        RECT  26.64 69.036 26.664 69.12 ;
    END
  END cfg_data[241]
  PIN cfg_data[242]
    DIRECTION INPUT ;
    USE SIGNAL ;
    PORT
      LAYER M5 ;
        RECT  26.736 69.036 26.76 69.12 ;
    END
  END cfg_data[242]
  PIN cfg_data[243]
    DIRECTION INPUT ;
    USE SIGNAL ;
    PORT
      LAYER M5 ;
        RECT  26.832 69.036 26.856 69.12 ;
    END
  END cfg_data[243]
  PIN cfg_data[244]
    DIRECTION INPUT ;
    USE SIGNAL ;
    PORT
      LAYER M5 ;
        RECT  17.712 69.036 17.736 69.12 ;
    END
  END cfg_data[244]
  PIN cfg_data[245]
    DIRECTION INPUT ;
    USE SIGNAL ;
    PORT
      LAYER M5 ;
        RECT  17.808 69.036 17.832 69.12 ;
    END
  END cfg_data[245]
  PIN cfg_data[246]
    DIRECTION INPUT ;
    USE SIGNAL ;
    PORT
      LAYER M5 ;
        RECT  17.904 69.036 17.928 69.12 ;
    END
  END cfg_data[246]
  PIN cfg_data[247]
    DIRECTION INPUT ;
    USE SIGNAL ;
    PORT
      LAYER M5 ;
        RECT  18 69.036 18.024 69.12 ;
    END
  END cfg_data[247]
  PIN cfg_data[248]
    DIRECTION INPUT ;
    USE SIGNAL ;
    PORT
      LAYER M5 ;
        RECT  18.096 69.036 18.12 69.12 ;
    END
  END cfg_data[248]
  PIN cfg_data[249]
    DIRECTION INPUT ;
    USE SIGNAL ;
    PORT
      LAYER M5 ;
        RECT  18.192 69.036 18.216 69.12 ;
    END
  END cfg_data[249]
  PIN cfg_data[24]
    DIRECTION INPUT ;
    USE SIGNAL ;
    PORT
      LAYER M5 ;
        RECT  21.168 69.036 21.192 69.12 ;
    END
  END cfg_data[24]
  PIN cfg_data[250]
    DIRECTION INPUT ;
    USE SIGNAL ;
    PORT
      LAYER M5 ;
        RECT  18.288 69.036 18.312 69.12 ;
    END
  END cfg_data[250]
  PIN cfg_data[251]
    DIRECTION INPUT ;
    USE SIGNAL ;
    PORT
      LAYER M5 ;
        RECT  18.384 69.036 18.408 69.12 ;
    END
  END cfg_data[251]
  PIN cfg_data[252]
    DIRECTION INPUT ;
    USE SIGNAL ;
    PORT
      LAYER M5 ;
        RECT  18.48 69.036 18.504 69.12 ;
    END
  END cfg_data[252]
  PIN cfg_data[253]
    DIRECTION INPUT ;
    USE SIGNAL ;
    PORT
      LAYER M5 ;
        RECT  18.576 69.036 18.6 69.12 ;
    END
  END cfg_data[253]
  PIN cfg_data[254]
    DIRECTION INPUT ;
    USE SIGNAL ;
    PORT
      LAYER M5 ;
        RECT  18.672 69.036 18.696 69.12 ;
    END
  END cfg_data[254]
  PIN cfg_data[255]
    DIRECTION INPUT ;
    USE SIGNAL ;
    PORT
      LAYER M5 ;
        RECT  18.768 69.036 18.792 69.12 ;
    END
  END cfg_data[255]
  PIN cfg_data[25]
    DIRECTION INPUT ;
    USE SIGNAL ;
    PORT
      LAYER M5 ;
        RECT  21.264 69.036 21.288 69.12 ;
    END
  END cfg_data[25]
  PIN cfg_data[26]
    DIRECTION INPUT ;
    USE SIGNAL ;
    PORT
      LAYER M5 ;
        RECT  21.36 69.036 21.384 69.12 ;
    END
  END cfg_data[26]
  PIN cfg_data[27]
    DIRECTION INPUT ;
    USE SIGNAL ;
    PORT
      LAYER M5 ;
        RECT  21.456 69.036 21.48 69.12 ;
    END
  END cfg_data[27]
  PIN cfg_data[28]
    DIRECTION INPUT ;
    USE SIGNAL ;
    PORT
      LAYER M5 ;
        RECT  21.552 69.036 21.576 69.12 ;
    END
  END cfg_data[28]
  PIN cfg_data[29]
    DIRECTION INPUT ;
    USE SIGNAL ;
    PORT
      LAYER M5 ;
        RECT  21.648 69.036 21.672 69.12 ;
    END
  END cfg_data[29]
  PIN cfg_data[2]
    DIRECTION INPUT ;
    USE SIGNAL ;
    PORT
      LAYER M5 ;
        RECT  41.328 69.036 41.352 69.12 ;
    END
  END cfg_data[2]
  PIN cfg_data[30]
    DIRECTION INPUT ;
    USE SIGNAL ;
    PORT
      LAYER M5 ;
        RECT  21.744 69.036 21.768 69.12 ;
    END
  END cfg_data[30]
  PIN cfg_data[31]
    DIRECTION INPUT ;
    USE SIGNAL ;
    PORT
      LAYER M5 ;
        RECT  21.84 69.036 21.864 69.12 ;
    END
  END cfg_data[31]
  PIN cfg_data[32]
    DIRECTION INPUT ;
    USE SIGNAL ;
    PORT
      LAYER M5 ;
        RECT  21.936 69.036 21.96 69.12 ;
    END
  END cfg_data[32]
  PIN cfg_data[33]
    DIRECTION INPUT ;
    USE SIGNAL ;
    PORT
      LAYER M5 ;
        RECT  22.032 69.036 22.056 69.12 ;
    END
  END cfg_data[33]
  PIN cfg_data[34]
    DIRECTION INPUT ;
    USE SIGNAL ;
    PORT
      LAYER M5 ;
        RECT  22.128 69.036 22.152 69.12 ;
    END
  END cfg_data[34]
  PIN cfg_data[35]
    DIRECTION INPUT ;
    USE SIGNAL ;
    PORT
      LAYER M5 ;
        RECT  22.224 69.036 22.248 69.12 ;
    END
  END cfg_data[35]
  PIN cfg_data[36]
    DIRECTION INPUT ;
    USE SIGNAL ;
    PORT
      LAYER M5 ;
        RECT  22.32 69.036 22.344 69.12 ;
    END
  END cfg_data[36]
  PIN cfg_data[37]
    DIRECTION INPUT ;
    USE SIGNAL ;
    PORT
      LAYER M5 ;
        RECT  22.416 69.036 22.44 69.12 ;
    END
  END cfg_data[37]
  PIN cfg_data[38]
    DIRECTION INPUT ;
    USE SIGNAL ;
    PORT
      LAYER M5 ;
        RECT  22.512 69.036 22.536 69.12 ;
    END
  END cfg_data[38]
  PIN cfg_data[39]
    DIRECTION INPUT ;
    USE SIGNAL ;
    PORT
      LAYER M5 ;
        RECT  22.608 69.036 22.632 69.12 ;
    END
  END cfg_data[39]
  PIN cfg_data[3]
    DIRECTION INPUT ;
    USE SIGNAL ;
    PORT
      LAYER M5 ;
        RECT  41.424 69.036 41.448 69.12 ;
    END
  END cfg_data[3]
  PIN cfg_data[40]
    DIRECTION INPUT ;
    USE SIGNAL ;
    PORT
      LAYER M5 ;
        RECT  22.704 69.036 22.728 69.12 ;
    END
  END cfg_data[40]
  PIN cfg_data[41]
    DIRECTION INPUT ;
    USE SIGNAL ;
    PORT
      LAYER M5 ;
        RECT  22.8 69.036 22.824 69.12 ;
    END
  END cfg_data[41]
  PIN cfg_data[42]
    DIRECTION INPUT ;
    USE SIGNAL ;
    PORT
      LAYER M5 ;
        RECT  22.896 69.036 22.92 69.12 ;
    END
  END cfg_data[42]
  PIN cfg_data[43]
    DIRECTION INPUT ;
    USE SIGNAL ;
    PORT
      LAYER M5 ;
        RECT  22.992 69.036 23.016 69.12 ;
    END
  END cfg_data[43]
  PIN cfg_data[44]
    DIRECTION INPUT ;
    USE SIGNAL ;
    PORT
      LAYER M5 ;
        RECT  23.088 69.036 23.112 69.12 ;
    END
  END cfg_data[44]
  PIN cfg_data[45]
    DIRECTION INPUT ;
    USE SIGNAL ;
    PORT
      LAYER M5 ;
        RECT  23.184 69.036 23.208 69.12 ;
    END
  END cfg_data[45]
  PIN cfg_data[46]
    DIRECTION INPUT ;
    USE SIGNAL ;
    PORT
      LAYER M5 ;
        RECT  23.28 69.036 23.304 69.12 ;
    END
  END cfg_data[46]
  PIN cfg_data[47]
    DIRECTION INPUT ;
    USE SIGNAL ;
    PORT
      LAYER M5 ;
        RECT  23.376 69.036 23.4 69.12 ;
    END
  END cfg_data[47]
  PIN cfg_data[48]
    DIRECTION INPUT ;
    USE SIGNAL ;
    PORT
      LAYER M5 ;
        RECT  23.472 69.036 23.496 69.12 ;
    END
  END cfg_data[48]
  PIN cfg_data[49]
    DIRECTION INPUT ;
    USE SIGNAL ;
    PORT
      LAYER M5 ;
        RECT  23.568 69.036 23.592 69.12 ;
    END
  END cfg_data[49]
  PIN cfg_data[4]
    DIRECTION INPUT ;
    USE SIGNAL ;
    PORT
      LAYER M5 ;
        RECT  41.52 69.036 41.544 69.12 ;
    END
  END cfg_data[4]
  PIN cfg_data[50]
    DIRECTION INPUT ;
    USE SIGNAL ;
    PORT
      LAYER M5 ;
        RECT  23.664 69.036 23.688 69.12 ;
    END
  END cfg_data[50]
  PIN cfg_data[51]
    DIRECTION INPUT ;
    USE SIGNAL ;
    PORT
      LAYER M5 ;
        RECT  23.76 69.036 23.784 69.12 ;
    END
  END cfg_data[51]
  PIN cfg_data[52]
    DIRECTION INPUT ;
    USE SIGNAL ;
    PORT
      LAYER M5 ;
        RECT  33.84 69.036 33.864 69.12 ;
    END
  END cfg_data[52]
  PIN cfg_data[53]
    DIRECTION INPUT ;
    USE SIGNAL ;
    PORT
      LAYER M5 ;
        RECT  33.936 69.036 33.96 69.12 ;
    END
  END cfg_data[53]
  PIN cfg_data[54]
    DIRECTION INPUT ;
    USE SIGNAL ;
    PORT
      LAYER M5 ;
        RECT  34.032 69.036 34.056 69.12 ;
    END
  END cfg_data[54]
  PIN cfg_data[55]
    DIRECTION INPUT ;
    USE SIGNAL ;
    PORT
      LAYER M5 ;
        RECT  34.128 69.036 34.152 69.12 ;
    END
  END cfg_data[55]
  PIN cfg_data[56]
    DIRECTION INPUT ;
    USE SIGNAL ;
    PORT
      LAYER M5 ;
        RECT  34.224 69.036 34.248 69.12 ;
    END
  END cfg_data[56]
  PIN cfg_data[57]
    DIRECTION INPUT ;
    USE SIGNAL ;
    PORT
      LAYER M5 ;
        RECT  34.32 69.036 34.344 69.12 ;
    END
  END cfg_data[57]
  PIN cfg_data[58]
    DIRECTION INPUT ;
    USE SIGNAL ;
    PORT
      LAYER M5 ;
        RECT  34.416 69.036 34.44 69.12 ;
    END
  END cfg_data[58]
  PIN cfg_data[59]
    DIRECTION INPUT ;
    USE SIGNAL ;
    PORT
      LAYER M5 ;
        RECT  34.512 69.036 34.536 69.12 ;
    END
  END cfg_data[59]
  PIN cfg_data[5]
    DIRECTION INPUT ;
    USE SIGNAL ;
    PORT
      LAYER M5 ;
        RECT  41.616 69.036 41.64 69.12 ;
    END
  END cfg_data[5]
  PIN cfg_data[60]
    DIRECTION INPUT ;
    USE SIGNAL ;
    PORT
      LAYER M5 ;
        RECT  34.608 69.036 34.632 69.12 ;
    END
  END cfg_data[60]
  PIN cfg_data[61]
    DIRECTION INPUT ;
    USE SIGNAL ;
    PORT
      LAYER M5 ;
        RECT  34.704 69.036 34.728 69.12 ;
    END
  END cfg_data[61]
  PIN cfg_data[62]
    DIRECTION INPUT ;
    USE SIGNAL ;
    PORT
      LAYER M5 ;
        RECT  34.8 69.036 34.824 69.12 ;
    END
  END cfg_data[62]
  PIN cfg_data[63]
    DIRECTION INPUT ;
    USE SIGNAL ;
    PORT
      LAYER M5 ;
        RECT  34.896 69.036 34.92 69.12 ;
    END
  END cfg_data[63]
  PIN cfg_data[64]
    DIRECTION INPUT ;
    USE SIGNAL ;
    PORT
      LAYER M5 ;
        RECT  34.992 69.036 35.016 69.12 ;
    END
  END cfg_data[64]
  PIN cfg_data[65]
    DIRECTION INPUT ;
    USE SIGNAL ;
    PORT
      LAYER M5 ;
        RECT  35.088 69.036 35.112 69.12 ;
    END
  END cfg_data[65]
  PIN cfg_data[66]
    DIRECTION INPUT ;
    USE SIGNAL ;
    PORT
      LAYER M5 ;
        RECT  35.184 69.036 35.208 69.12 ;
    END
  END cfg_data[66]
  PIN cfg_data[67]
    DIRECTION INPUT ;
    USE SIGNAL ;
    PORT
      LAYER M5 ;
        RECT  35.28 69.036 35.304 69.12 ;
    END
  END cfg_data[67]
  PIN cfg_data[68]
    DIRECTION INPUT ;
    USE SIGNAL ;
    PORT
      LAYER M5 ;
        RECT  35.376 69.036 35.4 69.12 ;
    END
  END cfg_data[68]
  PIN cfg_data[69]
    DIRECTION INPUT ;
    USE SIGNAL ;
    PORT
      LAYER M5 ;
        RECT  35.472 69.036 35.496 69.12 ;
    END
  END cfg_data[69]
  PIN cfg_data[6]
    DIRECTION INPUT ;
    USE SIGNAL ;
    PORT
      LAYER M5 ;
        RECT  41.712 69.036 41.736 69.12 ;
    END
  END cfg_data[6]
  PIN cfg_data[70]
    DIRECTION INPUT ;
    USE SIGNAL ;
    PORT
      LAYER M5 ;
        RECT  35.568 69.036 35.592 69.12 ;
    END
  END cfg_data[70]
  PIN cfg_data[71]
    DIRECTION INPUT ;
    USE SIGNAL ;
    PORT
      LAYER M5 ;
        RECT  35.664 69.036 35.688 69.12 ;
    END
  END cfg_data[71]
  PIN cfg_data[72]
    DIRECTION INPUT ;
    USE SIGNAL ;
    PORT
      LAYER M5 ;
        RECT  35.76 69.036 35.784 69.12 ;
    END
  END cfg_data[72]
  PIN cfg_data[73]
    DIRECTION INPUT ;
    USE SIGNAL ;
    PORT
      LAYER M5 ;
        RECT  35.856 69.036 35.88 69.12 ;
    END
  END cfg_data[73]
  PIN cfg_data[74]
    DIRECTION INPUT ;
    USE SIGNAL ;
    PORT
      LAYER M5 ;
        RECT  35.952 69.036 35.976 69.12 ;
    END
  END cfg_data[74]
  PIN cfg_data[75]
    DIRECTION INPUT ;
    USE SIGNAL ;
    PORT
      LAYER M5 ;
        RECT  36.048 69.036 36.072 69.12 ;
    END
  END cfg_data[75]
  PIN cfg_data[76]
    DIRECTION INPUT ;
    USE SIGNAL ;
    PORT
      LAYER M5 ;
        RECT  36.144 69.036 36.168 69.12 ;
    END
  END cfg_data[76]
  PIN cfg_data[77]
    DIRECTION INPUT ;
    USE SIGNAL ;
    PORT
      LAYER M5 ;
        RECT  36.24 69.036 36.264 69.12 ;
    END
  END cfg_data[77]
  PIN cfg_data[78]
    DIRECTION INPUT ;
    USE SIGNAL ;
    PORT
      LAYER M5 ;
        RECT  36.336 69.036 36.36 69.12 ;
    END
  END cfg_data[78]
  PIN cfg_data[79]
    DIRECTION INPUT ;
    USE SIGNAL ;
    PORT
      LAYER M5 ;
        RECT  36.432 69.036 36.456 69.12 ;
    END
  END cfg_data[79]
  PIN cfg_data[7]
    DIRECTION INPUT ;
    USE SIGNAL ;
    PORT
      LAYER M5 ;
        RECT  41.808 69.036 41.832 69.12 ;
    END
  END cfg_data[7]
  PIN cfg_data[80]
    DIRECTION INPUT ;
    USE SIGNAL ;
    PORT
      LAYER M5 ;
        RECT  36.528 69.036 36.552 69.12 ;
    END
  END cfg_data[80]
  PIN cfg_data[81]
    DIRECTION INPUT ;
    USE SIGNAL ;
    PORT
      LAYER M5 ;
        RECT  36.624 69.036 36.648 69.12 ;
    END
  END cfg_data[81]
  PIN cfg_data[82]
    DIRECTION INPUT ;
    USE SIGNAL ;
    PORT
      LAYER M5 ;
        RECT  36.72 69.036 36.744 69.12 ;
    END
  END cfg_data[82]
  PIN cfg_data[83]
    DIRECTION INPUT ;
    USE SIGNAL ;
    PORT
      LAYER M5 ;
        RECT  36.816 69.036 36.84 69.12 ;
    END
  END cfg_data[83]
  PIN cfg_data[84]
    DIRECTION INPUT ;
    USE SIGNAL ;
    PORT
      LAYER M5 ;
        RECT  43.056 69.036 43.08 69.12 ;
    END
  END cfg_data[84]
  PIN cfg_data[85]
    DIRECTION INPUT ;
    USE SIGNAL ;
    PORT
      LAYER M5 ;
        RECT  43.152 69.036 43.176 69.12 ;
    END
  END cfg_data[85]
  PIN cfg_data[86]
    DIRECTION INPUT ;
    USE SIGNAL ;
    PORT
      LAYER M5 ;
        RECT  43.248 69.036 43.272 69.12 ;
    END
  END cfg_data[86]
  PIN cfg_data[87]
    DIRECTION INPUT ;
    USE SIGNAL ;
    PORT
      LAYER M5 ;
        RECT  43.344 69.036 43.368 69.12 ;
    END
  END cfg_data[87]
  PIN cfg_data[88]
    DIRECTION INPUT ;
    USE SIGNAL ;
    PORT
      LAYER M5 ;
        RECT  43.44 69.036 43.464 69.12 ;
    END
  END cfg_data[88]
  PIN cfg_data[89]
    DIRECTION INPUT ;
    USE SIGNAL ;
    PORT
      LAYER M5 ;
        RECT  43.536 69.036 43.56 69.12 ;
    END
  END cfg_data[89]
  PIN cfg_data[8]
    DIRECTION INPUT ;
    USE SIGNAL ;
    PORT
      LAYER M5 ;
        RECT  41.904 69.036 41.928 69.12 ;
    END
  END cfg_data[8]
  PIN cfg_data[90]
    DIRECTION INPUT ;
    USE SIGNAL ;
    PORT
      LAYER M5 ;
        RECT  43.632 69.036 43.656 69.12 ;
    END
  END cfg_data[90]
  PIN cfg_data[91]
    DIRECTION INPUT ;
    USE SIGNAL ;
    PORT
      LAYER M5 ;
        RECT  43.728 69.036 43.752 69.12 ;
    END
  END cfg_data[91]
  PIN cfg_data[92]
    DIRECTION INPUT ;
    USE SIGNAL ;
    PORT
      LAYER M5 ;
        RECT  43.824 69.036 43.848 69.12 ;
    END
  END cfg_data[92]
  PIN cfg_data[93]
    DIRECTION INPUT ;
    USE SIGNAL ;
    PORT
      LAYER M5 ;
        RECT  43.92 69.036 43.944 69.12 ;
    END
  END cfg_data[93]
  PIN cfg_data[94]
    DIRECTION INPUT ;
    USE SIGNAL ;
    PORT
      LAYER M5 ;
        RECT  44.016 69.036 44.04 69.12 ;
    END
  END cfg_data[94]
  PIN cfg_data[95]
    DIRECTION INPUT ;
    USE SIGNAL ;
    PORT
      LAYER M5 ;
        RECT  44.112 69.036 44.136 69.12 ;
    END
  END cfg_data[95]
  PIN cfg_data[96]
    DIRECTION INPUT ;
    USE SIGNAL ;
    PORT
      LAYER M5 ;
        RECT  44.208 69.036 44.232 69.12 ;
    END
  END cfg_data[96]
  PIN cfg_data[97]
    DIRECTION INPUT ;
    USE SIGNAL ;
    PORT
      LAYER M5 ;
        RECT  44.304 69.036 44.328 69.12 ;
    END
  END cfg_data[97]
  PIN cfg_data[98]
    DIRECTION INPUT ;
    USE SIGNAL ;
    PORT
      LAYER M5 ;
        RECT  44.4 69.036 44.424 69.12 ;
    END
  END cfg_data[98]
  PIN cfg_data[99]
    DIRECTION INPUT ;
    USE SIGNAL ;
    PORT
      LAYER M5 ;
        RECT  44.496 69.036 44.52 69.12 ;
    END
  END cfg_data[99]
  PIN cfg_data[9]
    DIRECTION INPUT ;
    USE SIGNAL ;
    PORT
      LAYER M5 ;
        RECT  42 69.036 42.024 69.12 ;
    END
  END cfg_data[9]
  PIN cfg_target[0]
    DIRECTION INPUT ;
    USE SIGNAL ;
    PORT
      LAYER M5 ;
        RECT  18.864 69.036 18.888 69.12 ;
    END
  END cfg_target[0]
  PIN cfg_target[1]
    DIRECTION INPUT ;
    USE SIGNAL ;
    PORT
      LAYER M5 ;
        RECT  18.96 69.036 18.984 69.12 ;
    END
  END cfg_target[1]
  PIN cfg_target[2]
    DIRECTION INPUT ;
    USE SIGNAL ;
    PORT
      LAYER M5 ;
        RECT  19.056 69.036 19.08 69.12 ;
    END
  END cfg_target[2]
  PIN cfg_target[3]
    DIRECTION INPUT ;
    USE SIGNAL ;
    PORT
      LAYER M5 ;
        RECT  19.152 69.036 19.176 69.12 ;
    END
  END cfg_target[3]
  PIN cfg_target[4]
    DIRECTION INPUT ;
    USE SIGNAL ;
    PORT
      LAYER M5 ;
        RECT  19.248 69.036 19.272 69.12 ;
    END
  END cfg_target[4]
  PIN cfg_target[5]
    DIRECTION INPUT ;
    USE SIGNAL ;
    PORT
      LAYER M5 ;
        RECT  19.344 69.036 19.368 69.12 ;
    END
  END cfg_target[5]
  PIN cfg_target[6]
    DIRECTION INPUT ;
    USE SIGNAL ;
    PORT
      LAYER M5 ;
        RECT  19.44 69.036 19.464 69.12 ;
    END
  END cfg_target[6]
  PIN cfg_target[7]
    DIRECTION INPUT ;
    USE SIGNAL ;
    PORT
      LAYER M5 ;
        RECT  19.536 69.036 19.56 69.12 ;
    END
  END cfg_target[7]
  PIN cfg_v
    DIRECTION INPUT ;
    USE SIGNAL ;
    PORT
      LAYER M5 ;
        RECT  19.632 69.036 19.656 69.12 ;
    END
  END cfg_v
  PIN clk
    DIRECTION INPUT ;
    USE SIGNAL ;
    PORT
      LAYER M5 ;
        RECT  19.728 69.036 19.752 69.12 ;
    END
  END clk
  PIN desc_base[0]
    DIRECTION INPUT ;
    USE SIGNAL ;
    PORT
      LAYER M5 ;
        RECT  19.824 69.036 19.848 69.12 ;
    END
  END desc_base[0]
  PIN desc_base[10]
    DIRECTION INPUT ;
    USE SIGNAL ;
    PORT
      LAYER M5 ;
        RECT  26.928 69.036 26.952 69.12 ;
    END
  END desc_base[10]
  PIN desc_base[11]
    DIRECTION INPUT ;
    USE SIGNAL ;
    PORT
      LAYER M5 ;
        RECT  27.024 69.036 27.048 69.12 ;
    END
  END desc_base[11]
  PIN desc_base[1]
    DIRECTION INPUT ;
    USE SIGNAL ;
    PORT
      LAYER M5 ;
        RECT  19.92 69.036 19.944 69.12 ;
    END
  END desc_base[1]
  PIN desc_base[2]
    DIRECTION INPUT ;
    USE SIGNAL ;
    PORT
      LAYER M5 ;
        RECT  20.016 69.036 20.04 69.12 ;
    END
  END desc_base[2]
  PIN desc_base[3]
    DIRECTION INPUT ;
    USE SIGNAL ;
    PORT
      LAYER M5 ;
        RECT  20.112 69.036 20.136 69.12 ;
    END
  END desc_base[3]
  PIN desc_base[4]
    DIRECTION INPUT ;
    USE SIGNAL ;
    PORT
      LAYER M5 ;
        RECT  20.208 69.036 20.232 69.12 ;
    END
  END desc_base[4]
  PIN desc_base[5]
    DIRECTION INPUT ;
    USE SIGNAL ;
    PORT
      LAYER M5 ;
        RECT  20.304 69.036 20.328 69.12 ;
    END
  END desc_base[5]
  PIN desc_base[6]
    DIRECTION INPUT ;
    USE SIGNAL ;
    PORT
      LAYER M5 ;
        RECT  20.4 69.036 20.424 69.12 ;
    END
  END desc_base[6]
  PIN desc_base[7]
    DIRECTION INPUT ;
    USE SIGNAL ;
    PORT
      LAYER M5 ;
        RECT  20.496 69.036 20.52 69.12 ;
    END
  END desc_base[7]
  PIN desc_base[8]
    DIRECTION INPUT ;
    USE SIGNAL ;
    PORT
      LAYER M5 ;
        RECT  20.592 69.036 20.616 69.12 ;
    END
  END desc_base[8]
  PIN desc_base[9]
    DIRECTION INPUT ;
    USE SIGNAL ;
    PORT
      LAYER M5 ;
        RECT  20.688 69.036 20.712 69.12 ;
    END
  END desc_base[9]
  PIN desc_limit[0]
    DIRECTION INPUT ;
    USE SIGNAL ;
    PORT
      LAYER M5 ;
        RECT  27.12 69.036 27.144 69.12 ;
    END
  END desc_limit[0]
  PIN desc_limit[10]
    DIRECTION INPUT ;
    USE SIGNAL ;
    PORT
      LAYER M5 ;
        RECT  28.08 69.036 28.104 69.12 ;
    END
  END desc_limit[10]
  PIN desc_limit[11]
    DIRECTION INPUT ;
    USE SIGNAL ;
    PORT
      LAYER M5 ;
        RECT  28.176 69.036 28.2 69.12 ;
    END
  END desc_limit[11]
  PIN desc_limit[12]
    DIRECTION INPUT ;
    USE SIGNAL ;
    PORT
      LAYER M5 ;
        RECT  28.272 69.036 28.296 69.12 ;
    END
  END desc_limit[12]
  PIN desc_limit[1]
    DIRECTION INPUT ;
    USE SIGNAL ;
    PORT
      LAYER M5 ;
        RECT  27.216 69.036 27.24 69.12 ;
    END
  END desc_limit[1]
  PIN desc_limit[2]
    DIRECTION INPUT ;
    USE SIGNAL ;
    PORT
      LAYER M5 ;
        RECT  27.312 69.036 27.336 69.12 ;
    END
  END desc_limit[2]
  PIN desc_limit[3]
    DIRECTION INPUT ;
    USE SIGNAL ;
    PORT
      LAYER M5 ;
        RECT  27.408 69.036 27.432 69.12 ;
    END
  END desc_limit[3]
  PIN desc_limit[4]
    DIRECTION INPUT ;
    USE SIGNAL ;
    PORT
      LAYER M5 ;
        RECT  27.504 69.036 27.528 69.12 ;
    END
  END desc_limit[4]
  PIN desc_limit[5]
    DIRECTION INPUT ;
    USE SIGNAL ;
    PORT
      LAYER M5 ;
        RECT  27.6 69.036 27.624 69.12 ;
    END
  END desc_limit[5]
  PIN desc_limit[6]
    DIRECTION INPUT ;
    USE SIGNAL ;
    PORT
      LAYER M5 ;
        RECT  27.696 69.036 27.72 69.12 ;
    END
  END desc_limit[6]
  PIN desc_limit[7]
    DIRECTION INPUT ;
    USE SIGNAL ;
    PORT
      LAYER M5 ;
        RECT  27.792 69.036 27.816 69.12 ;
    END
  END desc_limit[7]
  PIN desc_limit[8]
    DIRECTION INPUT ;
    USE SIGNAL ;
    PORT
      LAYER M5 ;
        RECT  27.888 69.036 27.912 69.12 ;
    END
  END desc_limit[8]
  PIN desc_limit[9]
    DIRECTION INPUT ;
    USE SIGNAL ;
    PORT
      LAYER M5 ;
        RECT  27.984 69.036 28.008 69.12 ;
    END
  END desc_limit[9]
  PIN desc_loops[0]
    DIRECTION INPUT ;
    USE SIGNAL ;
    PORT
      LAYER M5 ;
        RECT  28.368 69.036 28.392 69.12 ;
    END
  END desc_loops[0]
  PIN desc_loops[10]
    DIRECTION INPUT ;
    USE SIGNAL ;
    PORT
      LAYER M5 ;
        RECT  29.328 69.036 29.352 69.12 ;
    END
  END desc_loops[10]
  PIN desc_loops[11]
    DIRECTION INPUT ;
    USE SIGNAL ;
    PORT
      LAYER M5 ;
        RECT  29.424 69.036 29.448 69.12 ;
    END
  END desc_loops[11]
  PIN desc_loops[12]
    DIRECTION INPUT ;
    USE SIGNAL ;
    PORT
      LAYER M5 ;
        RECT  29.52 69.036 29.544 69.12 ;
    END
  END desc_loops[12]
  PIN desc_loops[13]
    DIRECTION INPUT ;
    USE SIGNAL ;
    PORT
      LAYER M5 ;
        RECT  29.616 69.036 29.64 69.12 ;
    END
  END desc_loops[13]
  PIN desc_loops[14]
    DIRECTION INPUT ;
    USE SIGNAL ;
    PORT
      LAYER M5 ;
        RECT  29.712 69.036 29.736 69.12 ;
    END
  END desc_loops[14]
  PIN desc_loops[15]
    DIRECTION INPUT ;
    USE SIGNAL ;
    PORT
      LAYER M5 ;
        RECT  29.808 69.036 29.832 69.12 ;
    END
  END desc_loops[15]
  PIN desc_loops[1]
    DIRECTION INPUT ;
    USE SIGNAL ;
    PORT
      LAYER M5 ;
        RECT  28.464 69.036 28.488 69.12 ;
    END
  END desc_loops[1]
  PIN desc_loops[2]
    DIRECTION INPUT ;
    USE SIGNAL ;
    PORT
      LAYER M5 ;
        RECT  28.56 69.036 28.584 69.12 ;
    END
  END desc_loops[2]
  PIN desc_loops[3]
    DIRECTION INPUT ;
    USE SIGNAL ;
    PORT
      LAYER M5 ;
        RECT  28.656 69.036 28.68 69.12 ;
    END
  END desc_loops[3]
  PIN desc_loops[4]
    DIRECTION INPUT ;
    USE SIGNAL ;
    PORT
      LAYER M5 ;
        RECT  28.752 69.036 28.776 69.12 ;
    END
  END desc_loops[4]
  PIN desc_loops[5]
    DIRECTION INPUT ;
    USE SIGNAL ;
    PORT
      LAYER M5 ;
        RECT  28.848 69.036 28.872 69.12 ;
    END
  END desc_loops[5]
  PIN desc_loops[6]
    DIRECTION INPUT ;
    USE SIGNAL ;
    PORT
      LAYER M5 ;
        RECT  28.944 69.036 28.968 69.12 ;
    END
  END desc_loops[6]
  PIN desc_loops[7]
    DIRECTION INPUT ;
    USE SIGNAL ;
    PORT
      LAYER M5 ;
        RECT  29.04 69.036 29.064 69.12 ;
    END
  END desc_loops[7]
  PIN desc_loops[8]
    DIRECTION INPUT ;
    USE SIGNAL ;
    PORT
      LAYER M5 ;
        RECT  29.136 69.036 29.16 69.12 ;
    END
  END desc_loops[8]
  PIN desc_loops[9]
    DIRECTION INPUT ;
    USE SIGNAL ;
    PORT
      LAYER M5 ;
        RECT  29.232 69.036 29.256 69.12 ;
    END
  END desc_loops[9]
  PIN desc_v
    DIRECTION INPUT ;
    USE SIGNAL ;
    PORT
      LAYER M5 ;
        RECT  29.904 69.036 29.928 69.12 ;
    END
  END desc_v
  PIN launch_v
    DIRECTION INPUT ;
    USE SIGNAL ;
    PORT
      LAYER M5 ;
        RECT  30.576 69.036 30.6 69.12 ;
    END
  END launch_v
  PIN rst_n
    DIRECTION INPUT ;
    USE SIGNAL ;
    PORT
      LAYER M5 ;
        RECT  30.672 69.036 30.696 69.12 ;
    END
  END rst_n
  PIN s_active[0]
    DIRECTION OUTPUT ;
    USE SIGNAL ;
    PORT
      LAYER M5 ;
        RECT  39.12 0 39.144 0.084 ;
    END
  END s_active[0]
  PIN s_active[10]
    DIRECTION OUTPUT ;
    USE SIGNAL ;
    PORT
      LAYER M5 ;
        RECT  40.08 0 40.104 0.084 ;
    END
  END s_active[10]
  PIN s_active[11]
    DIRECTION OUTPUT ;
    USE SIGNAL ;
    PORT
      LAYER M5 ;
        RECT  40.176 0 40.2 0.084 ;
    END
  END s_active[11]
  PIN s_active[12]
    DIRECTION OUTPUT ;
    USE SIGNAL ;
    PORT
      LAYER M5 ;
        RECT  40.272 0 40.296 0.084 ;
    END
  END s_active[12]
  PIN s_active[13]
    DIRECTION OUTPUT ;
    USE SIGNAL ;
    PORT
      LAYER M5 ;
        RECT  40.368 0 40.392 0.084 ;
    END
  END s_active[13]
  PIN s_active[14]
    DIRECTION OUTPUT ;
    USE SIGNAL ;
    PORT
      LAYER M5 ;
        RECT  40.464 0 40.488 0.084 ;
    END
  END s_active[14]
  PIN s_active[15]
    DIRECTION OUTPUT ;
    USE SIGNAL ;
    PORT
      LAYER M5 ;
        RECT  40.56 0 40.584 0.084 ;
    END
  END s_active[15]
  PIN s_active[16]
    DIRECTION OUTPUT ;
    USE SIGNAL ;
    PORT
      LAYER M5 ;
        RECT  40.656 0 40.68 0.084 ;
    END
  END s_active[16]
  PIN s_active[17]
    DIRECTION OUTPUT ;
    USE SIGNAL ;
    PORT
      LAYER M5 ;
        RECT  40.752 0 40.776 0.084 ;
    END
  END s_active[17]
  PIN s_active[18]
    DIRECTION OUTPUT ;
    USE SIGNAL ;
    PORT
      LAYER M5 ;
        RECT  40.848 0 40.872 0.084 ;
    END
  END s_active[18]
  PIN s_active[19]
    DIRECTION OUTPUT ;
    USE SIGNAL ;
    PORT
      LAYER M5 ;
        RECT  40.944 0 40.968 0.084 ;
    END
  END s_active[19]
  PIN s_active[1]
    DIRECTION OUTPUT ;
    USE SIGNAL ;
    PORT
      LAYER M5 ;
        RECT  39.216 0 39.24 0.084 ;
    END
  END s_active[1]
  PIN s_active[2]
    DIRECTION OUTPUT ;
    USE SIGNAL ;
    PORT
      LAYER M5 ;
        RECT  39.312 0 39.336 0.084 ;
    END
  END s_active[2]
  PIN s_active[3]
    DIRECTION OUTPUT ;
    USE SIGNAL ;
    PORT
      LAYER M5 ;
        RECT  39.408 0 39.432 0.084 ;
    END
  END s_active[3]
  PIN s_active[4]
    DIRECTION OUTPUT ;
    USE SIGNAL ;
    PORT
      LAYER M5 ;
        RECT  39.504 0 39.528 0.084 ;
    END
  END s_active[4]
  PIN s_active[5]
    DIRECTION OUTPUT ;
    USE SIGNAL ;
    PORT
      LAYER M5 ;
        RECT  39.6 0 39.624 0.084 ;
    END
  END s_active[5]
  PIN s_active[6]
    DIRECTION OUTPUT ;
    USE SIGNAL ;
    PORT
      LAYER M5 ;
        RECT  39.696 0 39.72 0.084 ;
    END
  END s_active[6]
  PIN s_active[7]
    DIRECTION OUTPUT ;
    USE SIGNAL ;
    PORT
      LAYER M5 ;
        RECT  39.792 0 39.816 0.084 ;
    END
  END s_active[7]
  PIN s_active[8]
    DIRECTION OUTPUT ;
    USE SIGNAL ;
    PORT
      LAYER M5 ;
        RECT  39.888 0 39.912 0.084 ;
    END
  END s_active[8]
  PIN s_active[9]
    DIRECTION OUTPUT ;
    USE SIGNAL ;
    PORT
      LAYER M5 ;
        RECT  39.984 0 40.008 0.084 ;
    END
  END s_active[9]
  PIN s_fault[0]
    DIRECTION OUTPUT ;
    USE SIGNAL ;
    PORT
      LAYER M5 ;
        RECT  41.04 0 41.064 0.084 ;
    END
  END s_fault[0]
  PIN s_fault[10]
    DIRECTION OUTPUT ;
    USE SIGNAL ;
    PORT
      LAYER M5 ;
        RECT  42 0 42.024 0.084 ;
    END
  END s_fault[10]
  PIN s_fault[11]
    DIRECTION OUTPUT ;
    USE SIGNAL ;
    PORT
      LAYER M5 ;
        RECT  42.096 0 42.12 0.084 ;
    END
  END s_fault[11]
  PIN s_fault[12]
    DIRECTION OUTPUT ;
    USE SIGNAL ;
    PORT
      LAYER M5 ;
        RECT  42.192 0 42.216 0.084 ;
    END
  END s_fault[12]
  PIN s_fault[13]
    DIRECTION OUTPUT ;
    USE SIGNAL ;
    PORT
      LAYER M5 ;
        RECT  42.288 0 42.312 0.084 ;
    END
  END s_fault[13]
  PIN s_fault[14]
    DIRECTION OUTPUT ;
    USE SIGNAL ;
    PORT
      LAYER M5 ;
        RECT  42.384 0 42.408 0.084 ;
    END
  END s_fault[14]
  PIN s_fault[15]
    DIRECTION OUTPUT ;
    USE SIGNAL ;
    PORT
      LAYER M5 ;
        RECT  42.48 0 42.504 0.084 ;
    END
  END s_fault[15]
  PIN s_fault[16]
    DIRECTION OUTPUT ;
    USE SIGNAL ;
    PORT
      LAYER M5 ;
        RECT  42.576 0 42.6 0.084 ;
    END
  END s_fault[16]
  PIN s_fault[17]
    DIRECTION OUTPUT ;
    USE SIGNAL ;
    PORT
      LAYER M5 ;
        RECT  42.672 0 42.696 0.084 ;
    END
  END s_fault[17]
  PIN s_fault[18]
    DIRECTION OUTPUT ;
    USE SIGNAL ;
    PORT
      LAYER M5 ;
        RECT  42.768 0 42.792 0.084 ;
    END
  END s_fault[18]
  PIN s_fault[19]
    DIRECTION OUTPUT ;
    USE SIGNAL ;
    PORT
      LAYER M5 ;
        RECT  42.864 0 42.888 0.084 ;
    END
  END s_fault[19]
  PIN s_fault[1]
    DIRECTION OUTPUT ;
    USE SIGNAL ;
    PORT
      LAYER M5 ;
        RECT  41.136 0 41.16 0.084 ;
    END
  END s_fault[1]
  PIN s_fault[20]
    DIRECTION OUTPUT ;
    USE SIGNAL ;
    PORT
      LAYER M5 ;
        RECT  42.96 0 42.984 0.084 ;
    END
  END s_fault[20]
  PIN s_fault[21]
    DIRECTION OUTPUT ;
    USE SIGNAL ;
    PORT
      LAYER M5 ;
        RECT  43.056 0 43.08 0.084 ;
    END
  END s_fault[21]
  PIN s_fault[22]
    DIRECTION OUTPUT ;
    USE SIGNAL ;
    PORT
      LAYER M5 ;
        RECT  43.152 0 43.176 0.084 ;
    END
  END s_fault[22]
  PIN s_fault[23]
    DIRECTION OUTPUT ;
    USE SIGNAL ;
    PORT
      LAYER M5 ;
        RECT  43.248 0 43.272 0.084 ;
    END
  END s_fault[23]
  PIN s_fault[24]
    DIRECTION OUTPUT ;
    USE SIGNAL ;
    PORT
      LAYER M5 ;
        RECT  43.344 0 43.368 0.084 ;
    END
  END s_fault[24]
  PIN s_fault[25]
    DIRECTION OUTPUT ;
    USE SIGNAL ;
    PORT
      LAYER M5 ;
        RECT  43.44 0 43.464 0.084 ;
    END
  END s_fault[25]
  PIN s_fault[26]
    DIRECTION OUTPUT ;
    USE SIGNAL ;
    PORT
      LAYER M5 ;
        RECT  43.536 0 43.56 0.084 ;
    END
  END s_fault[26]
  PIN s_fault[27]
    DIRECTION OUTPUT ;
    USE SIGNAL ;
    PORT
      LAYER M5 ;
        RECT  43.632 0 43.656 0.084 ;
    END
  END s_fault[27]
  PIN s_fault[28]
    DIRECTION OUTPUT ;
    USE SIGNAL ;
    PORT
      LAYER M5 ;
        RECT  43.728 0 43.752 0.084 ;
    END
  END s_fault[28]
  PIN s_fault[29]
    DIRECTION OUTPUT ;
    USE SIGNAL ;
    PORT
      LAYER M5 ;
        RECT  43.824 0 43.848 0.084 ;
    END
  END s_fault[29]
  PIN s_fault[2]
    DIRECTION OUTPUT ;
    USE SIGNAL ;
    PORT
      LAYER M5 ;
        RECT  41.232 0 41.256 0.084 ;
    END
  END s_fault[2]
  PIN s_fault[30]
    DIRECTION OUTPUT ;
    USE SIGNAL ;
    PORT
      LAYER M5 ;
        RECT  43.92 0 43.944 0.084 ;
    END
  END s_fault[30]
  PIN s_fault[31]
    DIRECTION OUTPUT ;
    USE SIGNAL ;
    PORT
      LAYER M5 ;
        RECT  44.016 0 44.04 0.084 ;
    END
  END s_fault[31]
  PIN s_fault[3]
    DIRECTION OUTPUT ;
    USE SIGNAL ;
    PORT
      LAYER M5 ;
        RECT  41.328 0 41.352 0.084 ;
    END
  END s_fault[3]
  PIN s_fault[4]
    DIRECTION OUTPUT ;
    USE SIGNAL ;
    PORT
      LAYER M5 ;
        RECT  41.424 0 41.448 0.084 ;
    END
  END s_fault[4]
  PIN s_fault[5]
    DIRECTION OUTPUT ;
    USE SIGNAL ;
    PORT
      LAYER M5 ;
        RECT  41.52 0 41.544 0.084 ;
    END
  END s_fault[5]
  PIN s_fault[6]
    DIRECTION OUTPUT ;
    USE SIGNAL ;
    PORT
      LAYER M5 ;
        RECT  41.616 0 41.64 0.084 ;
    END
  END s_fault[6]
  PIN s_fault[7]
    DIRECTION OUTPUT ;
    USE SIGNAL ;
    PORT
      LAYER M5 ;
        RECT  41.712 0 41.736 0.084 ;
    END
  END s_fault[7]
  PIN s_fault[8]
    DIRECTION OUTPUT ;
    USE SIGNAL ;
    PORT
      LAYER M5 ;
        RECT  41.808 0 41.832 0.084 ;
    END
  END s_fault[8]
  PIN s_fault[9]
    DIRECTION OUTPUT ;
    USE SIGNAL ;
    PORT
      LAYER M5 ;
        RECT  41.904 0 41.928 0.084 ;
    END
  END s_fault[9]
  PIN s_ready[0]
    DIRECTION OUTPUT ;
    USE SIGNAL ;
    PORT
      LAYER M5 ;
        RECT  44.112 0 44.136 0.084 ;
    END
  END s_ready[0]
  PIN s_ready[10]
    DIRECTION OUTPUT ;
    USE SIGNAL ;
    PORT
      LAYER M5 ;
        RECT  45.072 0 45.096 0.084 ;
    END
  END s_ready[10]
  PIN s_ready[11]
    DIRECTION OUTPUT ;
    USE SIGNAL ;
    PORT
      LAYER M5 ;
        RECT  45.168 0 45.192 0.084 ;
    END
  END s_ready[11]
  PIN s_ready[12]
    DIRECTION OUTPUT ;
    USE SIGNAL ;
    PORT
      LAYER M5 ;
        RECT  32.208 0 32.232 0.084 ;
    END
  END s_ready[12]
  PIN s_ready[13]
    DIRECTION OUTPUT ;
    USE SIGNAL ;
    PORT
      LAYER M5 ;
        RECT  32.304 0 32.328 0.084 ;
    END
  END s_ready[13]
  PIN s_ready[14]
    DIRECTION OUTPUT ;
    USE SIGNAL ;
    PORT
      LAYER M5 ;
        RECT  32.4 0 32.424 0.084 ;
    END
  END s_ready[14]
  PIN s_ready[15]
    DIRECTION OUTPUT ;
    USE SIGNAL ;
    PORT
      LAYER M5 ;
        RECT  32.496 0 32.52 0.084 ;
    END
  END s_ready[15]
  PIN s_ready[16]
    DIRECTION OUTPUT ;
    USE SIGNAL ;
    PORT
      LAYER M5 ;
        RECT  32.592 0 32.616 0.084 ;
    END
  END s_ready[16]
  PIN s_ready[17]
    DIRECTION OUTPUT ;
    USE SIGNAL ;
    PORT
      LAYER M5 ;
        RECT  32.688 0 32.712 0.084 ;
    END
  END s_ready[17]
  PIN s_ready[18]
    DIRECTION OUTPUT ;
    USE SIGNAL ;
    PORT
      LAYER M5 ;
        RECT  32.784 0 32.808 0.084 ;
    END
  END s_ready[18]
  PIN s_ready[19]
    DIRECTION OUTPUT ;
    USE SIGNAL ;
    PORT
      LAYER M5 ;
        RECT  32.88 0 32.904 0.084 ;
    END
  END s_ready[19]
  PIN s_ready[1]
    DIRECTION OUTPUT ;
    USE SIGNAL ;
    PORT
      LAYER M5 ;
        RECT  44.208 0 44.232 0.084 ;
    END
  END s_ready[1]
  PIN s_ready[2]
    DIRECTION OUTPUT ;
    USE SIGNAL ;
    PORT
      LAYER M5 ;
        RECT  44.304 0 44.328 0.084 ;
    END
  END s_ready[2]
  PIN s_ready[3]
    DIRECTION OUTPUT ;
    USE SIGNAL ;
    PORT
      LAYER M5 ;
        RECT  44.4 0 44.424 0.084 ;
    END
  END s_ready[3]
  PIN s_ready[4]
    DIRECTION OUTPUT ;
    USE SIGNAL ;
    PORT
      LAYER M5 ;
        RECT  44.496 0 44.52 0.084 ;
    END
  END s_ready[4]
  PIN s_ready[5]
    DIRECTION OUTPUT ;
    USE SIGNAL ;
    PORT
      LAYER M5 ;
        RECT  44.592 0 44.616 0.084 ;
    END
  END s_ready[5]
  PIN s_ready[6]
    DIRECTION OUTPUT ;
    USE SIGNAL ;
    PORT
      LAYER M5 ;
        RECT  44.688 0 44.712 0.084 ;
    END
  END s_ready[6]
  PIN s_ready[7]
    DIRECTION OUTPUT ;
    USE SIGNAL ;
    PORT
      LAYER M5 ;
        RECT  44.784 0 44.808 0.084 ;
    END
  END s_ready[7]
  PIN s_ready[8]
    DIRECTION OUTPUT ;
    USE SIGNAL ;
    PORT
      LAYER M5 ;
        RECT  44.88 0 44.904 0.084 ;
    END
  END s_ready[8]
  PIN s_ready[9]
    DIRECTION OUTPUT ;
    USE SIGNAL ;
    PORT
      LAYER M5 ;
        RECT  44.976 0 45 0.084 ;
    END
  END s_ready[9]
  PIN t_active[0]
    DIRECTION INPUT ;
    USE SIGNAL ;
    PORT
      LAYER M5 ;
        RECT  32.976 0 33 0.084 ;
    END
  END t_active[0]
  PIN t_active[10]
    DIRECTION INPUT ;
    USE SIGNAL ;
    PORT
      LAYER M5 ;
        RECT  33.936 0 33.96 0.084 ;
    END
  END t_active[10]
  PIN t_active[11]
    DIRECTION INPUT ;
    USE SIGNAL ;
    PORT
      LAYER M5 ;
        RECT  34.032 0 34.056 0.084 ;
    END
  END t_active[11]
  PIN t_active[12]
    DIRECTION INPUT ;
    USE SIGNAL ;
    PORT
      LAYER M5 ;
        RECT  34.128 0 34.152 0.084 ;
    END
  END t_active[12]
  PIN t_active[13]
    DIRECTION INPUT ;
    USE SIGNAL ;
    PORT
      LAYER M5 ;
        RECT  34.224 0 34.248 0.084 ;
    END
  END t_active[13]
  PIN t_active[14]
    DIRECTION INPUT ;
    USE SIGNAL ;
    PORT
      LAYER M5 ;
        RECT  34.32 0 34.344 0.084 ;
    END
  END t_active[14]
  PIN t_active[15]
    DIRECTION INPUT ;
    USE SIGNAL ;
    PORT
      LAYER M5 ;
        RECT  34.416 0 34.44 0.084 ;
    END
  END t_active[15]
  PIN t_active[16]
    DIRECTION INPUT ;
    USE SIGNAL ;
    PORT
      LAYER M5 ;
        RECT  34.512 0 34.536 0.084 ;
    END
  END t_active[16]
  PIN t_active[17]
    DIRECTION INPUT ;
    USE SIGNAL ;
    PORT
      LAYER M5 ;
        RECT  34.608 0 34.632 0.084 ;
    END
  END t_active[17]
  PIN t_active[18]
    DIRECTION INPUT ;
    USE SIGNAL ;
    PORT
      LAYER M5 ;
        RECT  34.704 0 34.728 0.084 ;
    END
  END t_active[18]
  PIN t_active[19]
    DIRECTION INPUT ;
    USE SIGNAL ;
    PORT
      LAYER M5 ;
        RECT  34.8 0 34.824 0.084 ;
    END
  END t_active[19]
  PIN t_active[1]
    DIRECTION INPUT ;
    USE SIGNAL ;
    PORT
      LAYER M5 ;
        RECT  33.072 0 33.096 0.084 ;
    END
  END t_active[1]
  PIN t_active[2]
    DIRECTION INPUT ;
    USE SIGNAL ;
    PORT
      LAYER M5 ;
        RECT  33.168 0 33.192 0.084 ;
    END
  END t_active[2]
  PIN t_active[3]
    DIRECTION INPUT ;
    USE SIGNAL ;
    PORT
      LAYER M5 ;
        RECT  33.264 0 33.288 0.084 ;
    END
  END t_active[3]
  PIN t_active[4]
    DIRECTION INPUT ;
    USE SIGNAL ;
    PORT
      LAYER M5 ;
        RECT  33.36 0 33.384 0.084 ;
    END
  END t_active[4]
  PIN t_active[5]
    DIRECTION INPUT ;
    USE SIGNAL ;
    PORT
      LAYER M5 ;
        RECT  33.456 0 33.48 0.084 ;
    END
  END t_active[5]
  PIN t_active[6]
    DIRECTION INPUT ;
    USE SIGNAL ;
    PORT
      LAYER M5 ;
        RECT  33.552 0 33.576 0.084 ;
    END
  END t_active[6]
  PIN t_active[7]
    DIRECTION INPUT ;
    USE SIGNAL ;
    PORT
      LAYER M5 ;
        RECT  33.648 0 33.672 0.084 ;
    END
  END t_active[7]
  PIN t_active[8]
    DIRECTION INPUT ;
    USE SIGNAL ;
    PORT
      LAYER M5 ;
        RECT  33.744 0 33.768 0.084 ;
    END
  END t_active[8]
  PIN t_active[9]
    DIRECTION INPUT ;
    USE SIGNAL ;
    PORT
      LAYER M5 ;
        RECT  33.84 0 33.864 0.084 ;
    END
  END t_active[9]
  PIN t_fault[0]
    DIRECTION INPUT ;
    USE SIGNAL ;
    PORT
      LAYER M5 ;
        RECT  34.896 0 34.92 0.084 ;
    END
  END t_fault[0]
  PIN t_fault[10]
    DIRECTION INPUT ;
    USE SIGNAL ;
    PORT
      LAYER M5 ;
        RECT  35.856 0 35.88 0.084 ;
    END
  END t_fault[10]
  PIN t_fault[11]
    DIRECTION INPUT ;
    USE SIGNAL ;
    PORT
      LAYER M5 ;
        RECT  35.952 0 35.976 0.084 ;
    END
  END t_fault[11]
  PIN t_fault[12]
    DIRECTION INPUT ;
    USE SIGNAL ;
    PORT
      LAYER M5 ;
        RECT  36.048 0 36.072 0.084 ;
    END
  END t_fault[12]
  PIN t_fault[13]
    DIRECTION INPUT ;
    USE SIGNAL ;
    PORT
      LAYER M5 ;
        RECT  36.144 0 36.168 0.084 ;
    END
  END t_fault[13]
  PIN t_fault[14]
    DIRECTION INPUT ;
    USE SIGNAL ;
    PORT
      LAYER M5 ;
        RECT  36.24 0 36.264 0.084 ;
    END
  END t_fault[14]
  PIN t_fault[15]
    DIRECTION INPUT ;
    USE SIGNAL ;
    PORT
      LAYER M5 ;
        RECT  36.336 0 36.36 0.084 ;
    END
  END t_fault[15]
  PIN t_fault[16]
    DIRECTION INPUT ;
    USE SIGNAL ;
    PORT
      LAYER M5 ;
        RECT  36.432 0 36.456 0.084 ;
    END
  END t_fault[16]
  PIN t_fault[17]
    DIRECTION INPUT ;
    USE SIGNAL ;
    PORT
      LAYER M5 ;
        RECT  36.528 0 36.552 0.084 ;
    END
  END t_fault[17]
  PIN t_fault[18]
    DIRECTION INPUT ;
    USE SIGNAL ;
    PORT
      LAYER M5 ;
        RECT  36.624 0 36.648 0.084 ;
    END
  END t_fault[18]
  PIN t_fault[19]
    DIRECTION INPUT ;
    USE SIGNAL ;
    PORT
      LAYER M5 ;
        RECT  36.72 0 36.744 0.084 ;
    END
  END t_fault[19]
  PIN t_fault[1]
    DIRECTION INPUT ;
    USE SIGNAL ;
    PORT
      LAYER M5 ;
        RECT  34.992 0 35.016 0.084 ;
    END
  END t_fault[1]
  PIN t_fault[20]
    DIRECTION INPUT ;
    USE SIGNAL ;
    PORT
      LAYER M5 ;
        RECT  36.816 0 36.84 0.084 ;
    END
  END t_fault[20]
  PIN t_fault[21]
    DIRECTION INPUT ;
    USE SIGNAL ;
    PORT
      LAYER M5 ;
        RECT  36.912 0 36.936 0.084 ;
    END
  END t_fault[21]
  PIN t_fault[22]
    DIRECTION INPUT ;
    USE SIGNAL ;
    PORT
      LAYER M5 ;
        RECT  37.008 0 37.032 0.084 ;
    END
  END t_fault[22]
  PIN t_fault[23]
    DIRECTION INPUT ;
    USE SIGNAL ;
    PORT
      LAYER M5 ;
        RECT  37.104 0 37.128 0.084 ;
    END
  END t_fault[23]
  PIN t_fault[24]
    DIRECTION INPUT ;
    USE SIGNAL ;
    PORT
      LAYER M5 ;
        RECT  37.2 0 37.224 0.084 ;
    END
  END t_fault[24]
  PIN t_fault[25]
    DIRECTION INPUT ;
    USE SIGNAL ;
    PORT
      LAYER M5 ;
        RECT  37.296 0 37.32 0.084 ;
    END
  END t_fault[25]
  PIN t_fault[26]
    DIRECTION INPUT ;
    USE SIGNAL ;
    PORT
      LAYER M5 ;
        RECT  37.392 0 37.416 0.084 ;
    END
  END t_fault[26]
  PIN t_fault[27]
    DIRECTION INPUT ;
    USE SIGNAL ;
    PORT
      LAYER M5 ;
        RECT  37.488 0 37.512 0.084 ;
    END
  END t_fault[27]
  PIN t_fault[28]
    DIRECTION INPUT ;
    USE SIGNAL ;
    PORT
      LAYER M5 ;
        RECT  37.584 0 37.608 0.084 ;
    END
  END t_fault[28]
  PIN t_fault[29]
    DIRECTION INPUT ;
    USE SIGNAL ;
    PORT
      LAYER M5 ;
        RECT  37.68 0 37.704 0.084 ;
    END
  END t_fault[29]
  PIN t_fault[2]
    DIRECTION INPUT ;
    USE SIGNAL ;
    PORT
      LAYER M5 ;
        RECT  35.088 0 35.112 0.084 ;
    END
  END t_fault[2]
  PIN t_fault[30]
    DIRECTION INPUT ;
    USE SIGNAL ;
    PORT
      LAYER M5 ;
        RECT  37.776 0 37.8 0.084 ;
    END
  END t_fault[30]
  PIN t_fault[31]
    DIRECTION INPUT ;
    USE SIGNAL ;
    PORT
      LAYER M5 ;
        RECT  37.872 0 37.896 0.084 ;
    END
  END t_fault[31]
  PIN t_fault[3]
    DIRECTION INPUT ;
    USE SIGNAL ;
    PORT
      LAYER M5 ;
        RECT  35.184 0 35.208 0.084 ;
    END
  END t_fault[3]
  PIN t_fault[4]
    DIRECTION INPUT ;
    USE SIGNAL ;
    PORT
      LAYER M5 ;
        RECT  35.28 0 35.304 0.084 ;
    END
  END t_fault[4]
  PIN t_fault[5]
    DIRECTION INPUT ;
    USE SIGNAL ;
    PORT
      LAYER M5 ;
        RECT  35.376 0 35.4 0.084 ;
    END
  END t_fault[5]
  PIN t_fault[6]
    DIRECTION INPUT ;
    USE SIGNAL ;
    PORT
      LAYER M5 ;
        RECT  35.472 0 35.496 0.084 ;
    END
  END t_fault[6]
  PIN t_fault[7]
    DIRECTION INPUT ;
    USE SIGNAL ;
    PORT
      LAYER M5 ;
        RECT  35.568 0 35.592 0.084 ;
    END
  END t_fault[7]
  PIN t_fault[8]
    DIRECTION INPUT ;
    USE SIGNAL ;
    PORT
      LAYER M5 ;
        RECT  35.664 0 35.688 0.084 ;
    END
  END t_fault[8]
  PIN t_fault[9]
    DIRECTION INPUT ;
    USE SIGNAL ;
    PORT
      LAYER M5 ;
        RECT  35.76 0 35.784 0.084 ;
    END
  END t_fault[9]
  PIN t_ready[0]
    DIRECTION INPUT ;
    USE SIGNAL ;
    PORT
      LAYER M5 ;
        RECT  37.968 0 37.992 0.084 ;
    END
  END t_ready[0]
  PIN t_ready[10]
    DIRECTION INPUT ;
    USE SIGNAL ;
    PORT
      LAYER M5 ;
        RECT  29.712 0 29.736 0.084 ;
    END
  END t_ready[10]
  PIN t_ready[11]
    DIRECTION INPUT ;
    USE SIGNAL ;
    PORT
      LAYER M5 ;
        RECT  29.808 0 29.832 0.084 ;
    END
  END t_ready[11]
  PIN t_ready[12]
    DIRECTION INPUT ;
    USE SIGNAL ;
    PORT
      LAYER M5 ;
        RECT  29.904 0 29.928 0.084 ;
    END
  END t_ready[12]
  PIN t_ready[13]
    DIRECTION INPUT ;
    USE SIGNAL ;
    PORT
      LAYER M5 ;
        RECT  30 0 30.024 0.084 ;
    END
  END t_ready[13]
  PIN t_ready[14]
    DIRECTION INPUT ;
    USE SIGNAL ;
    PORT
      LAYER M5 ;
        RECT  30.096 0 30.12 0.084 ;
    END
  END t_ready[14]
  PIN t_ready[15]
    DIRECTION INPUT ;
    USE SIGNAL ;
    PORT
      LAYER M5 ;
        RECT  30.192 0 30.216 0.084 ;
    END
  END t_ready[15]
  PIN t_ready[16]
    DIRECTION INPUT ;
    USE SIGNAL ;
    PORT
      LAYER M5 ;
        RECT  30.288 0 30.312 0.084 ;
    END
  END t_ready[16]
  PIN t_ready[17]
    DIRECTION INPUT ;
    USE SIGNAL ;
    PORT
      LAYER M5 ;
        RECT  30.384 0 30.408 0.084 ;
    END
  END t_ready[17]
  PIN t_ready[18]
    DIRECTION INPUT ;
    USE SIGNAL ;
    PORT
      LAYER M5 ;
        RECT  30.48 0 30.504 0.084 ;
    END
  END t_ready[18]
  PIN t_ready[19]
    DIRECTION INPUT ;
    USE SIGNAL ;
    PORT
      LAYER M5 ;
        RECT  30.576 0 30.6 0.084 ;
    END
  END t_ready[19]
  PIN t_ready[1]
    DIRECTION INPUT ;
    USE SIGNAL ;
    PORT
      LAYER M5 ;
        RECT  38.064 0 38.088 0.084 ;
    END
  END t_ready[1]
  PIN t_ready[2]
    DIRECTION INPUT ;
    USE SIGNAL ;
    PORT
      LAYER M5 ;
        RECT  38.16 0 38.184 0.084 ;
    END
  END t_ready[2]
  PIN t_ready[3]
    DIRECTION INPUT ;
    USE SIGNAL ;
    PORT
      LAYER M5 ;
        RECT  38.256 0 38.28 0.084 ;
    END
  END t_ready[3]
  PIN t_ready[4]
    DIRECTION INPUT ;
    USE SIGNAL ;
    PORT
      LAYER M5 ;
        RECT  29.136 0 29.16 0.084 ;
    END
  END t_ready[4]
  PIN t_ready[5]
    DIRECTION INPUT ;
    USE SIGNAL ;
    PORT
      LAYER M5 ;
        RECT  29.232 0 29.256 0.084 ;
    END
  END t_ready[5]
  PIN t_ready[6]
    DIRECTION INPUT ;
    USE SIGNAL ;
    PORT
      LAYER M5 ;
        RECT  29.328 0 29.352 0.084 ;
    END
  END t_ready[6]
  PIN t_ready[7]
    DIRECTION INPUT ;
    USE SIGNAL ;
    PORT
      LAYER M5 ;
        RECT  29.424 0 29.448 0.084 ;
    END
  END t_ready[7]
  PIN t_ready[8]
    DIRECTION INPUT ;
    USE SIGNAL ;
    PORT
      LAYER M5 ;
        RECT  29.52 0 29.544 0.084 ;
    END
  END t_ready[8]
  PIN t_ready[9]
    DIRECTION INPUT ;
    USE SIGNAL ;
    PORT
      LAYER M5 ;
        RECT  29.616 0 29.64 0.084 ;
    END
  END t_ready[9]
  PIN VDD
    DIRECTION INOUT ;
    USE POWER ;
    PORT
      LAYER M5 ;
        RECT  61.992 2.151 62.112 66.969 ;
        RECT  56.592 2.151 56.712 66.969 ;
        RECT  51.192 2.151 51.312 66.969 ;
        RECT  45.792 2.151 45.912 66.969 ;
        RECT  40.392 2.151 40.512 66.969 ;
        RECT  34.992 2.151 35.112 66.969 ;
        RECT  29.592 2.151 29.712 66.969 ;
        RECT  24.192 2.151 24.312 66.969 ;
        RECT  18.792 2.151 18.912 66.969 ;
        RECT  13.392 2.151 13.512 66.969 ;
        RECT  7.992 2.151 8.112 66.969 ;
        RECT  2.592 2.151 2.712 66.969 ;
    END
  END VDD
  PIN VSS
    DIRECTION INOUT ;
    USE GROUND ;
    PORT
      LAYER M5 ;
        RECT  61.8 2.137 61.92 66.983 ;
        RECT  56.4 2.137 56.52 66.983 ;
        RECT  51 2.137 51.12 66.983 ;
        RECT  45.6 2.137 45.72 66.983 ;
        RECT  40.2 2.137 40.32 66.983 ;
        RECT  34.8 2.137 34.92 66.983 ;
        RECT  29.4 2.137 29.52 66.983 ;
        RECT  24 2.137 24.12 66.983 ;
        RECT  18.6 2.137 18.72 66.983 ;
        RECT  13.2 2.137 13.32 66.983 ;
        RECT  7.8 2.137 7.92 66.983 ;
        RECT  2.4 2.137 2.52 66.983 ;
    END
  END VSS
  OBS
    LAYER RVTN ;
     RECT  2.16 2.16 66.96 2.295 ;
     RECT  2.16 2.565 66.96 2.835 ;
     RECT  2.16 3.105 66.96 3.375 ;
     RECT  2.16 3.645 66.96 3.915 ;
     RECT  2.16 4.185 66.96 4.455 ;
     RECT  2.16 4.725 66.96 4.995 ;
     RECT  2.16 5.265 66.96 5.535 ;
     RECT  2.16 5.805 66.96 6.075 ;
     RECT  2.16 6.345 66.96 6.615 ;
     RECT  2.16 6.885 66.96 7.155 ;
     RECT  2.16 7.425 66.96 7.695 ;
     RECT  2.16 7.965 66.96 8.235 ;
     RECT  2.16 8.505 66.96 8.775 ;
     RECT  2.16 9.045 66.96 9.315 ;
     RECT  2.16 9.585 66.96 9.855 ;
     RECT  2.16 10.125 66.96 10.395 ;
     RECT  2.16 10.665 66.96 10.935 ;
     RECT  2.16 11.205 66.96 11.475 ;
     RECT  2.16 11.745 66.96 12.015 ;
     RECT  2.16 12.285 66.96 12.555 ;
     RECT  2.16 12.825 66.96 13.095 ;
     RECT  2.16 13.365 66.96 13.635 ;
     RECT  2.16 13.905 66.96 14.175 ;
     RECT  2.16 14.445 66.96 14.715 ;
     RECT  2.16 14.985 66.96 15.255 ;
     RECT  2.16 15.525 66.96 15.795 ;
     RECT  2.16 16.065 66.96 16.335 ;
     RECT  2.16 16.605 66.96 16.875 ;
     RECT  2.16 17.145 66.96 17.415 ;
     RECT  2.16 17.685 66.96 17.955 ;
     RECT  2.16 18.225 66.96 18.495 ;
     RECT  2.16 18.765 66.96 19.035 ;
     RECT  2.16 19.305 66.96 19.575 ;
     RECT  2.16 19.845 66.96 20.115 ;
     RECT  2.16 20.385 66.96 20.655 ;
     RECT  2.16 20.925 66.96 21.195 ;
     RECT  2.16 21.465 66.96 21.735 ;
     RECT  2.16 22.005 66.96 22.275 ;
     RECT  2.16 22.545 66.96 22.815 ;
     RECT  2.16 23.085 66.96 23.355 ;
     RECT  2.16 23.625 66.96 23.895 ;
     RECT  2.16 24.165 66.96 24.435 ;
     RECT  2.16 24.705 66.96 24.975 ;
     RECT  2.16 25.245 66.96 25.515 ;
     RECT  2.16 25.785 66.96 26.055 ;
     RECT  2.16 26.325 66.96 26.595 ;
     RECT  2.16 26.865 66.96 27.135 ;
     RECT  2.16 27.405 66.96 27.675 ;
     RECT  2.16 27.945 66.96 28.215 ;
     RECT  2.16 28.485 66.96 28.755 ;
     RECT  2.16 29.025 66.96 29.295 ;
     RECT  2.16 29.565 66.96 29.835 ;
     RECT  2.16 30.105 66.96 30.375 ;
     RECT  2.16 30.645 66.96 30.915 ;
     RECT  2.16 31.185 66.96 31.455 ;
     RECT  2.16 31.725 66.96 31.995 ;
     RECT  2.16 32.265 66.96 32.535 ;
     RECT  2.16 32.805 66.96 33.075 ;
     RECT  2.16 33.345 66.96 33.615 ;
     RECT  2.16 33.885 66.96 34.155 ;
     RECT  2.16 34.425 66.96 34.695 ;
     RECT  2.16 34.965 66.96 35.235 ;
     RECT  2.16 35.505 66.96 35.775 ;
     RECT  2.16 36.045 66.96 36.315 ;
     RECT  2.16 36.585 66.96 36.855 ;
     RECT  2.16 37.125 66.96 37.395 ;
     RECT  2.16 37.665 66.96 37.935 ;
     RECT  2.16 38.205 66.96 38.475 ;
     RECT  2.16 38.745 66.96 39.015 ;
     RECT  2.16 39.285 66.96 39.555 ;
     RECT  2.16 39.825 66.96 40.095 ;
     RECT  2.16 40.365 66.96 40.635 ;
     RECT  2.16 40.905 66.96 41.175 ;
     RECT  2.16 41.445 66.96 41.715 ;
     RECT  2.16 41.985 66.96 42.255 ;
     RECT  2.16 42.525 66.96 42.795 ;
     RECT  2.16 43.065 66.96 43.335 ;
     RECT  2.16 43.605 66.96 43.875 ;
     RECT  2.16 44.145 66.96 44.415 ;
     RECT  2.16 44.685 66.96 44.955 ;
     RECT  2.16 45.225 66.96 45.495 ;
     RECT  2.16 45.765 66.96 46.035 ;
     RECT  2.16 46.305 66.96 46.575 ;
     RECT  2.16 46.845 66.96 47.115 ;
     RECT  2.16 47.385 66.96 47.655 ;
     RECT  2.16 47.925 66.96 48.195 ;
     RECT  2.16 48.465 66.96 48.735 ;
     RECT  2.16 49.005 66.96 49.275 ;
     RECT  2.16 49.545 66.96 49.815 ;
     RECT  2.16 50.085 66.96 50.355 ;
     RECT  2.16 50.625 66.96 50.895 ;
     RECT  2.16 51.165 66.96 51.435 ;
     RECT  2.16 51.705 66.96 51.975 ;
     RECT  2.16 52.245 66.96 52.515 ;
     RECT  2.16 52.785 66.96 53.055 ;
     RECT  2.16 53.325 66.96 53.595 ;
     RECT  2.16 53.865 66.96 54.135 ;
     RECT  2.16 54.405 66.96 54.675 ;
     RECT  2.16 54.945 66.96 55.215 ;
     RECT  2.16 55.485 66.96 55.755 ;
     RECT  2.16 56.025 66.96 56.295 ;
     RECT  2.16 56.565 66.96 56.835 ;
     RECT  2.16 57.105 66.96 57.375 ;
     RECT  2.16 57.645 66.96 57.915 ;
     RECT  2.16 58.185 66.96 58.455 ;
     RECT  2.16 58.725 66.96 58.995 ;
     RECT  2.16 59.265 66.96 59.535 ;
     RECT  2.16 59.805 66.96 60.075 ;
     RECT  2.16 60.345 66.96 60.615 ;
     RECT  2.16 60.885 66.96 61.155 ;
     RECT  2.16 61.425 66.96 61.695 ;
     RECT  2.16 61.965 66.96 62.235 ;
     RECT  2.16 62.505 66.96 62.775 ;
     RECT  2.16 63.045 66.96 63.315 ;
     RECT  2.16 63.585 66.96 63.855 ;
     RECT  2.16 64.125 66.96 64.395 ;
     RECT  2.16 64.665 66.96 64.935 ;
     RECT  2.16 65.205 66.96 65.475 ;
     RECT  2.16 65.745 66.96 66.015 ;
     RECT  2.16 66.285 66.96 66.555 ;
     RECT  2.16 66.825 66.96 66.96 ;
    LAYER RVTP ;
     RECT  2.16 2.295 66.96 2.565 ;
     RECT  2.16 2.835 66.96 3.105 ;
     RECT  2.16 3.375 66.96 3.645 ;
     RECT  2.16 3.915 66.96 4.185 ;
     RECT  2.16 4.455 66.96 4.725 ;
     RECT  2.16 4.995 66.96 5.265 ;
     RECT  2.16 5.535 66.96 5.805 ;
     RECT  2.16 6.075 66.96 6.345 ;
     RECT  2.16 6.615 66.96 6.885 ;
     RECT  2.16 7.155 66.96 7.425 ;
     RECT  2.16 7.695 66.96 7.965 ;
     RECT  2.16 8.235 66.96 8.505 ;
     RECT  2.16 8.775 66.96 9.045 ;
     RECT  2.16 9.315 66.96 9.585 ;
     RECT  2.16 9.855 66.96 10.125 ;
     RECT  2.16 10.395 66.96 10.665 ;
     RECT  2.16 10.935 66.96 11.205 ;
     RECT  2.16 11.475 66.96 11.745 ;
     RECT  2.16 12.015 66.96 12.285 ;
     RECT  2.16 12.555 66.96 12.825 ;
     RECT  2.16 13.095 66.96 13.365 ;
     RECT  2.16 13.635 66.96 13.905 ;
     RECT  2.16 14.175 66.96 14.445 ;
     RECT  2.16 14.715 66.96 14.985 ;
     RECT  2.16 15.255 66.96 15.525 ;
     RECT  2.16 15.795 66.96 16.065 ;
     RECT  2.16 16.335 66.96 16.605 ;
     RECT  2.16 16.875 66.96 17.145 ;
     RECT  2.16 17.415 66.96 17.685 ;
     RECT  2.16 17.955 66.96 18.225 ;
     RECT  2.16 18.495 66.96 18.765 ;
     RECT  2.16 19.035 66.96 19.305 ;
     RECT  2.16 19.575 66.96 19.845 ;
     RECT  2.16 20.115 66.96 20.385 ;
     RECT  2.16 20.655 66.96 20.925 ;
     RECT  2.16 21.195 66.96 21.465 ;
     RECT  2.16 21.735 66.96 22.005 ;
     RECT  2.16 22.275 66.96 22.545 ;
     RECT  2.16 22.815 66.96 23.085 ;
     RECT  2.16 23.355 66.96 23.625 ;
     RECT  2.16 23.895 66.96 24.165 ;
     RECT  2.16 24.435 66.96 24.705 ;
     RECT  2.16 24.975 66.96 25.245 ;
     RECT  2.16 25.515 66.96 25.785 ;
     RECT  2.16 26.055 66.96 26.325 ;
     RECT  2.16 26.595 66.96 26.865 ;
     RECT  2.16 27.135 66.96 27.405 ;
     RECT  2.16 27.675 66.96 27.945 ;
     RECT  2.16 28.215 66.96 28.485 ;
     RECT  2.16 28.755 66.96 29.025 ;
     RECT  2.16 29.295 66.96 29.565 ;
     RECT  2.16 29.835 66.96 30.105 ;
     RECT  2.16 30.375 66.96 30.645 ;
     RECT  2.16 30.915 66.96 31.185 ;
     RECT  2.16 31.455 66.96 31.725 ;
     RECT  2.16 31.995 66.96 32.265 ;
     RECT  2.16 32.535 66.96 32.805 ;
     RECT  2.16 33.075 66.96 33.345 ;
     RECT  2.16 33.615 66.96 33.885 ;
     RECT  2.16 34.155 66.96 34.425 ;
     RECT  2.16 34.695 66.96 34.965 ;
     RECT  2.16 35.235 66.96 35.505 ;
     RECT  2.16 35.775 66.96 36.045 ;
     RECT  2.16 36.315 66.96 36.585 ;
     RECT  2.16 36.855 66.96 37.125 ;
     RECT  2.16 37.395 66.96 37.665 ;
     RECT  2.16 37.935 66.96 38.205 ;
     RECT  2.16 38.475 66.96 38.745 ;
     RECT  2.16 39.015 66.96 39.285 ;
     RECT  2.16 39.555 66.96 39.825 ;
     RECT  2.16 40.095 66.96 40.365 ;
     RECT  2.16 40.635 66.96 40.905 ;
     RECT  2.16 41.175 66.96 41.445 ;
     RECT  2.16 41.715 66.96 41.985 ;
     RECT  2.16 42.255 66.96 42.525 ;
     RECT  2.16 42.795 66.96 43.065 ;
     RECT  2.16 43.335 66.96 43.605 ;
     RECT  2.16 43.875 66.96 44.145 ;
     RECT  2.16 44.415 66.96 44.685 ;
     RECT  2.16 44.955 66.96 45.225 ;
     RECT  2.16 45.495 66.96 45.765 ;
     RECT  2.16 46.035 66.96 46.305 ;
     RECT  2.16 46.575 66.96 46.845 ;
     RECT  2.16 47.115 66.96 47.385 ;
     RECT  2.16 47.655 66.96 47.925 ;
     RECT  2.16 48.195 66.96 48.465 ;
     RECT  2.16 48.735 66.96 49.005 ;
     RECT  2.16 49.275 66.96 49.545 ;
     RECT  2.16 49.815 66.96 50.085 ;
     RECT  2.16 50.355 66.96 50.625 ;
     RECT  2.16 50.895 66.96 51.165 ;
     RECT  2.16 51.435 66.96 51.705 ;
     RECT  2.16 51.975 66.96 52.245 ;
     RECT  2.16 52.515 66.96 52.785 ;
     RECT  2.16 53.055 66.96 53.325 ;
     RECT  2.16 53.595 66.96 53.865 ;
     RECT  2.16 54.135 66.96 54.405 ;
     RECT  2.16 54.675 66.96 54.945 ;
     RECT  2.16 55.215 66.96 55.485 ;
     RECT  2.16 55.755 66.96 56.025 ;
     RECT  2.16 56.295 66.96 56.565 ;
     RECT  2.16 56.835 66.96 57.105 ;
     RECT  2.16 57.375 66.96 57.645 ;
     RECT  2.16 57.915 66.96 58.185 ;
     RECT  2.16 58.455 66.96 58.725 ;
     RECT  2.16 58.995 66.96 59.265 ;
     RECT  2.16 59.535 66.96 59.805 ;
     RECT  2.16 60.075 66.96 60.345 ;
     RECT  2.16 60.615 66.96 60.885 ;
     RECT  2.16 61.155 66.96 61.425 ;
     RECT  2.16 61.695 66.96 61.965 ;
     RECT  2.16 62.235 66.96 62.505 ;
     RECT  2.16 62.775 66.96 63.045 ;
     RECT  2.16 63.315 66.96 63.585 ;
     RECT  2.16 63.855 66.96 64.125 ;
     RECT  2.16 64.395 66.96 64.665 ;
     RECT  2.16 64.935 66.96 65.205 ;
     RECT  2.16 65.475 66.96 65.745 ;
     RECT  2.16 66.015 66.96 66.285 ;
     RECT  2.16 66.555 66.96 66.825 ;
    LAYER M1 ;
     RECT  2.16 2.151 66.96 66.969 ;
    LAYER M2 ;
     RECT  0.103 21.861 0.139 21.96 ;
     RECT  0.103 44.586 0.139 44.604 ;
     RECT  0.139 44.496 0.175 44.604 ;
     RECT  0.103 48.708 0.175 48.996 ;
     RECT  0.103 19.62 0.203 19.638 ;
     RECT  0.139 21.438 0.203 21.96 ;
     RECT  0.103 23.022 0.203 23.04 ;
     RECT  0.103 23.94 0.203 23.958 ;
     RECT  0.103 24.714 0.203 24.732 ;
     RECT  0.103 25.641 0.203 25.884 ;
     RECT  0.103 28.458 0.203 28.476 ;
     RECT  0.103 38.79 0.203 38.808 ;
     RECT  0.103 39.834 0.203 40.59 ;
     RECT  0.103 43.191 0.203 43.209 ;
     RECT  0.175 44.082 0.203 44.604 ;
     RECT  0.103 45.846 0.203 45.864 ;
     RECT  0.103 47.664 0.203 47.682 ;
     RECT  0.175 48.708 0.203 49.032 ;
     RECT  0.203 21.438 0.239 21.879 ;
     RECT  0.203 40.572 0.239 40.59 ;
     RECT  0.203 49.014 0.275 49.032 ;
     RECT  0.239 21.861 0.347 21.879 ;
     RECT  0.203 44.082 0.419 44.514 ;
     RECT  0.499 31.158 0.535 31.176 ;
     RECT  0.103 35.748 0.535 35.766 ;
     RECT  0.535 26.91 0.635 27.504 ;
     RECT  0.635 26.91 2.155 26.928 ;
     RECT  0.535 34.056 2.155 34.074 ;
     RECT  0.535 35.316 2.155 35.802 ;
     RECT  0.535 17.658 2.16 17.676 ;
     RECT  0.103 18.774 2.16 18.792 ;
     RECT  0.535 25.056 2.16 25.074 ;
     RECT  2.155 26.91 2.16 27.324 ;
     RECT  0.535 31.158 2.16 31.914 ;
     RECT  0.535 33.048 2.16 33.066 ;
     RECT  2.155 34.056 2.16 35.802 ;
     RECT  0.535 37.566 2.16 37.584 ;
     RECT  0.535 42.156 2.16 42.174 ;
     RECT  0.535 43.308 2.16 43.326 ;
     RECT  0.419 44.496 2.16 44.514 ;
     RECT  2.16 2.151 17.887 66.969 ;
     RECT  17.887 2.151 18.851 67.014 ;
     RECT  18.851 2.151 29.371 66.969 ;
     RECT  29.371 1.962 34.511 66.969 ;
     RECT  35.563 1.152 35.699 1.17 ;
     RECT  34.511 2.106 36.211 66.969 ;
     RECT  36.211 1.962 37.643 66.969 ;
     RECT  37.643 2.106 40.199 66.969 ;
     RECT  40.199 2.151 40.963 66.969 ;
     RECT  40.963 2.106 41.963 66.969 ;
     RECT  41.963 2.151 42.727 66.969 ;
     RECT  42.727 2.106 44.383 66.969 ;
     RECT  44.383 2.07 45.031 66.969 ;
     RECT  45.031 2.034 46.183 66.969 ;
     RECT  46.183 1.998 46.219 66.969 ;
     RECT  46.219 1.926 48.155 66.969 ;
     RECT  48.155 2.151 66.96 66.969 ;
     RECT  66.96 19.746 67.307 51.426 ;
     RECT  67.307 19.746 67.811 38.43 ;
     RECT  67.307 39.186 67.847 51.426 ;
     RECT  67.811 19.746 68.027 33.444 ;
     RECT  67.811 34.2 68.351 38.43 ;
     RECT  68.027 19.746 68.387 21.924 ;
     RECT  68.027 22.716 68.387 33.444 ;
     RECT  68.351 37.746 68.387 38.43 ;
     RECT  67.847 39.186 68.387 42.552 ;
     RECT  67.847 43.308 68.387 49.302 ;
     RECT  67.847 50.166 68.387 51.426 ;
     RECT  68.387 19.746 68.423 21.609 ;
     RECT  68.387 23.328 68.423 25.47 ;
     RECT  68.387 26.226 68.423 30.024 ;
     RECT  68.387 30.888 68.423 33.444 ;
     RECT  68.351 34.2 68.423 36.882 ;
     RECT  68.387 39.186 68.423 40.626 ;
     RECT  68.387 45.738 68.423 45.864 ;
     RECT  68.387 46.818 68.423 48.024 ;
     RECT  68.387 48.906 68.423 49.302 ;
     RECT  68.423 26.226 68.459 28.512 ;
     RECT  68.423 46.818 68.459 46.944 ;
     RECT  68.423 47.898 68.459 48.024 ;
     RECT  68.423 23.328 68.495 24.93 ;
     RECT  68.387 43.308 68.927 44.748 ;
     RECT  68.927 44.388 68.963 44.748 ;
     RECT  68.459 26.226 68.999 27.936 ;
     RECT  68.423 31.428 68.999 33.444 ;
     RECT  68.423 35.514 68.999 36.882 ;
     RECT  68.963 44.388 68.999 44.442 ;
     RECT  68.423 45.774 68.999 45.864 ;
     RECT  68.387 50.292 68.999 51.426 ;
     RECT  68.423 20.43 69.035 21.564 ;
     RECT  68.495 23.328 69.035 23.886 ;
     RECT  68.495 24.912 69.035 24.93 ;
     RECT  68.999 26.226 69.035 26.244 ;
     RECT  68.999 27.342 69.035 27.936 ;
     RECT  68.423 29.646 69.035 30.024 ;
     RECT  68.999 31.662 69.035 33.444 ;
     RECT  68.423 34.2 69.035 34.218 ;
     RECT  68.999 35.514 69.035 36.108 ;
     RECT  68.999 36.864 69.035 36.882 ;
     RECT  68.387 37.908 69.035 38.43 ;
     RECT  68.423 40.608 69.035 40.626 ;
     RECT  68.387 41.454 69.035 41.814 ;
     RECT  68.927 43.308 69.035 43.632 ;
     RECT  68.999 44.388 69.035 44.406 ;
     RECT  68.999 45.846 69.035 45.864 ;
     RECT  68.459 46.818 69.035 46.836 ;
     RECT  68.459 48.006 69.035 48.024 ;
     RECT  68.423 48.906 69.035 48.924 ;
     RECT  68.999 50.328 69.035 51.39 ;
    LAYER M3 ;
     RECT  47.88 0.043 47.898 0.091 ;
     RECT  34.776 0.091 34.794 0.139 ;
     RECT  35.676 0.091 35.694 0.139 ;
     RECT  37.476 0.091 37.494 0.139 ;
     RECT  47.556 0.091 47.898 0.139 ;
     RECT  41.94 0.043 41.958 0.173 ;
     RECT  47.016 0.139 47.898 0.187 ;
     RECT  37.476 0.139 37.638 0.269 ;
     RECT  34.776 0.139 35.694 0.317 ;
     RECT  37.62 0.269 37.638 0.317 ;
     RECT  32.76 0.091 32.778 0.475 ;
     RECT  32.76 0.475 33.21 0.571 ;
     RECT  47.016 0.187 47.934 0.811 ;
     RECT  47.016 0.811 48.474 0.955 ;
     RECT  42.12 0.811 42.138 0.989 ;
     RECT  34.776 0.317 34.794 1.147 ;
     RECT  35.676 0.317 35.694 1.147 ;
     RECT  34.776 1.147 35.694 1.175 ;
     RECT  32.58 0.571 33.21 1.579 ;
     RECT  28.908 1.099 28.926 1.675 ;
     RECT  39.384 1.099 39.402 1.675 ;
     RECT  28.908 1.675 29.034 1.723 ;
     RECT  31.968 1.579 33.21 1.723 ;
     RECT  34.776 1.175 35.586 1.723 ;
     RECT  28.908 1.723 30.582 1.771 ;
     RECT  41.508 1.723 41.526 1.771 ;
     RECT  42.696 1.723 42.714 1.771 ;
     RECT  45.036 1.723 45.054 1.771 ;
     RECT  46.188 0.859 46.206 1.771 ;
     RECT  45.036 1.771 46.206 1.867 ;
     RECT  31.968 1.723 35.586 1.957 ;
     RECT  37.152 1.723 37.17 1.957 ;
     RECT  37.152 1.957 37.638 2.029 ;
     RECT  45.036 1.867 46.242 2.065 ;
     RECT  39.384 1.675 40.014 2.101 ;
     RECT  41.508 1.771 42.714 2.101 ;
     RECT  44.388 2.065 46.242 2.101 ;
     RECT  39.348 2.101 40.194 2.143 ;
     RECT  40.968 2.101 42.75 2.143 ;
     RECT  31.968 1.957 36.234 2.191 ;
     RECT  47.016 0.955 48.942 2.219 ;
     RECT  28.908 1.771 30.762 2.251 ;
     RECT  31.608 2.191 36.234 2.251 ;
     RECT  37.008 2.029 37.638 2.251 ;
     RECT  28.908 2.251 30.834 2.299 ;
     RECT  31.608 2.251 37.638 2.299 ;
     RECT  38.52 2.191 38.538 2.299 ;
     RECT  39.348 2.143 42.75 2.299 ;
     RECT  44.208 2.101 46.242 2.299 ;
     RECT  47.016 2.219 48.834 2.299 ;
     RECT  28.908 2.299 37.638 2.335 ;
     RECT  38.52 2.299 48.834 2.335 ;
     RECT  2.415 2.143 2.505 2.413 ;
     RECT  7.815 2.143 7.905 2.413 ;
     RECT  13.215 2.143 13.305 2.413 ;
     RECT  18.615 2.143 18.705 2.413 ;
     RECT  24.015 2.143 24.105 2.413 ;
     RECT  51.015 2.143 51.105 2.413 ;
     RECT  56.415 2.143 56.505 2.413 ;
     RECT  61.815 2.143 61.905 2.413 ;
     RECT  28.908 2.335 48.834 3.065 ;
     RECT  29.016 3.065 48.834 3.299 ;
     RECT  29.016 3.299 48.402 3.839 ;
     RECT  29.016 3.839 48.258 3.875 ;
     RECT  29.16 3.875 48.258 4.109 ;
     RECT  29.196 4.109 48.258 4.415 ;
     RECT  29.232 4.415 48.258 4.685 ;
     RECT  29.415 4.685 48.258 4.757 ;
     RECT  29.415 4.757 48.186 4.955 ;
     RECT  29.415 4.955 29.697 5.737 ;
     RECT  30.42 4.955 48.186 5.737 ;
     RECT  29.415 5.737 48.186 6.305 ;
     RECT  47.664 6.305 48.186 6.539 ;
     RECT  30.492 6.305 46.89 6.809 ;
     RECT  30.492 6.809 30.51 6.845 ;
     RECT  31.284 6.809 46.89 6.845 ;
     RECT  32.832 6.845 46.89 6.917 ;
     RECT  31.284 6.845 32.022 6.953 ;
     RECT  31.284 6.953 31.338 7.079 ;
     RECT  32.832 6.917 46.782 7.079 ;
     RECT  47.664 6.539 47.682 7.349 ;
     RECT  32.904 7.079 46.71 7.385 ;
     RECT  32.904 7.385 46.458 7.421 ;
     RECT  33.048 7.421 45.954 7.457 ;
     RECT  33.624 7.457 45.954 7.469 ;
     RECT  33.948 7.469 45.954 7.529 ;
     RECT  33.948 7.529 45.897 7.691 ;
     RECT  44.856 7.691 45.897 7.727 ;
     RECT  45.18 7.727 45.897 7.763 ;
     RECT  33.948 7.691 43.974 7.889 ;
     RECT  33.948 7.889 43.938 7.949 ;
     RECT  34.164 7.949 43.938 8.159 ;
     RECT  34.164 8.159 43.362 8.303 ;
     RECT  34.164 8.303 43.218 8.339 ;
     RECT  34.164 8.339 42.714 8.429 ;
     RECT  34.164 8.429 42.39 8.477 ;
     RECT  41.688 8.477 41.994 8.501 ;
     RECT  34.164 8.477 40.662 8.699 ;
     RECT  41.76 8.501 41.922 8.699 ;
     RECT  37.944 8.699 40.662 8.735 ;
     RECT  34.164 8.699 37.206 8.813 ;
     RECT  36.72 8.813 37.206 8.843 ;
     RECT  37.944 8.735 38.466 8.843 ;
     RECT  37.188 8.843 37.206 8.861 ;
     RECT  39.312 8.735 40.662 8.879 ;
     RECT  34.164 8.813 35.91 8.969 ;
     RECT  39.888 8.879 40.662 8.969 ;
     RECT  41.76 8.699 41.814 8.969 ;
     RECT  37.944 8.843 38.286 9.005 ;
     RECT  34.164 8.969 35.097 9.247 ;
     RECT  34.092 9.247 35.097 9.355 ;
     RECT  33.12 9.355 33.138 9.391 ;
     RECT  33.984 9.355 35.097 9.391 ;
     RECT  33.12 9.391 35.097 9.859 ;
     RECT  32.004 9.691 32.022 9.931 ;
     RECT  32.94 9.859 35.097 9.931 ;
     RECT  32.004 9.931 35.097 10.049 ;
     RECT  32.004 10.049 32.022 10.085 ;
     RECT  32.796 10.049 35.097 10.085 ;
     RECT  34.344 10.085 35.097 10.121 ;
     RECT  34.776 10.121 35.097 10.201 ;
     RECT  32.94 10.085 33.426 10.319 ;
     RECT  33.3 10.319 33.318 10.355 ;
     RECT  34.776 10.201 35.298 10.355 ;
     RECT  31.932 10.363 31.95 10.4 ;
     RECT  34.815 10.355 35.298 10.471 ;
     RECT  41.76 8.969 41.778 10.589 ;
     RECT  34.815 10.471 35.442 10.741 ;
     RECT  18.615 2.413 18.897 17.347 ;
     RECT  4.536 17.221 4.554 17.491 ;
     RECT  6.48 17.221 6.498 17.491 ;
     RECT  4.356 17.491 4.554 17.581 ;
     RECT  6.48 17.491 6.678 17.617 ;
     RECT  3.996 17.581 4.554 17.653 ;
     RECT  5.364 17.491 5.382 17.653 ;
     RECT  6.48 17.617 6.894 17.653 ;
     RECT  3.996 17.653 6.894 17.689 ;
     RECT  7.815 2.413 8.097 17.725 ;
     RECT  0.54 17.653 0.558 17.741 ;
     RECT  2.415 2.413 2.697 17.761 ;
     RECT  18.615 17.347 19.314 17.761 ;
     RECT  7.815 17.725 8.586 17.851 ;
     RECT  10.8 17.725 10.818 17.851 ;
     RECT  10.8 17.851 10.854 17.879 ;
     RECT  2.304 17.761 2.697 17.923 ;
     RECT  18.504 17.761 19.314 17.923 ;
     RECT  10.836 17.879 10.854 17.951 ;
     RECT  7.815 17.851 8.658 18.031 ;
     RECT  9.432 17.851 9.45 18.031 ;
     RECT  3.96 17.689 6.894 18.121 ;
     RECT  3.96 18.121 6.93 18.149 ;
     RECT  3.96 18.149 4.626 18.185 ;
     RECT  5.436 18.149 6.93 18.235 ;
     RECT  7.815 18.031 9.45 18.235 ;
     RECT  5.436 18.235 9.45 18.265 ;
     RECT  18.504 17.923 19.674 18.265 ;
     RECT  18.504 18.265 19.746 18.571 ;
     RECT  2.304 17.923 2.898 18.599 ;
     RECT  2.415 18.599 2.898 18.661 ;
     RECT  2.415 18.661 2.97 18.715 ;
     RECT  0.144 18.235 0.162 18.769 ;
     RECT  5.436 18.265 9.522 18.797 ;
     RECT  4.212 18.185 4.626 18.931 ;
     RECT  9.504 18.797 9.522 18.931 ;
     RECT  4.14 18.931 4.698 18.955 ;
     RECT  5.436 18.797 8.586 18.955 ;
     RECT  9.504 18.931 9.63 19.067 ;
     RECT  2.415 18.715 3.078 19.075 ;
     RECT  3.996 18.955 8.586 19.075 ;
     RECT  18.504 18.571 19.854 19.075 ;
     RECT  18.504 19.075 20.178 19.111 ;
     RECT  10.98 19.039 10.998 19.201 ;
     RECT  9.504 19.067 9.558 19.229 ;
     RECT  2.415 19.075 8.586 19.265 ;
     RECT  9.54 19.229 9.558 19.337 ;
     RECT  2.415 19.265 8.298 19.339 ;
     RECT  18.504 19.111 20.43 19.345 ;
     RECT  2.376 19.339 8.298 19.373 ;
     RECT  10.908 19.201 10.998 19.373 ;
     RECT  0.108 18.769 0.162 19.612 ;
     RECT  18.504 19.345 20.826 19.615 ;
     RECT  2.376 19.373 2.697 19.627 ;
     RECT  0.108 19.612 0.198 19.757 ;
     RECT  0.144 19.757 0.198 19.805 ;
     RECT  24.015 2.413 24.297 19.867 ;
     RECT  10.836 19.741 10.854 19.877 ;
     RECT  68.4 19.741 68.418 19.915 ;
     RECT  61.815 2.413 62.097 20.005 ;
     RECT  23.4 19.867 24.297 20.011 ;
     RECT  61.815 20.005 62.73 20.011 ;
     RECT  22.824 20.011 24.297 20.039 ;
     RECT  60.3 20.011 60.318 20.047 ;
     RECT  61.815 20.011 62.802 20.047 ;
     RECT  63.576 20.011 63.594 20.047 ;
     RECT  64.62 19.921 64.638 20.047 ;
     RECT  3.456 19.373 8.298 20.083 ;
     RECT  21.852 20.011 21.87 20.083 ;
     RECT  61.815 20.047 63.594 20.083 ;
     RECT  64.368 20.047 64.638 20.083 ;
     RECT  10.8 20.011 10.818 20.111 ;
     RECT  22.824 20.039 22.842 20.141 ;
     RECT  26.784 20.011 26.802 20.141 ;
     RECT  47.628 20.083 47.646 20.155 ;
     RECT  60.3 20.047 60.39 20.155 ;
     RECT  61.308 20.083 63.594 20.155 ;
     RECT  58.716 20.047 58.734 20.183 ;
     RECT  2.304 19.627 2.697 20.191 ;
     RECT  3.456 20.083 8.622 20.191 ;
     RECT  21.852 20.083 21.942 20.191 ;
     RECT  61.164 20.155 63.594 20.191 ;
     RECT  64.368 20.083 65.358 20.191 ;
     RECT  67.788 19.915 68.418 20.203 ;
     RECT  2.304 20.191 8.622 20.219 ;
     RECT  61.164 20.191 65.358 20.219 ;
     RECT  60.084 20.155 60.39 20.299 ;
     RECT  61.164 20.219 64.818 20.299 ;
     RECT  2.304 20.219 8.334 20.309 ;
     RECT  60.084 20.299 64.818 20.309 ;
     RECT  47.628 20.155 48.078 20.317 ;
     RECT  48.852 19.741 48.87 20.317 ;
     RECT  47.628 20.317 48.87 20.333 ;
     RECT  18.504 19.615 20.934 20.389 ;
     RECT  21.852 20.191 22.518 20.389 ;
     RECT  47.628 20.333 48.798 20.389 ;
     RECT  9.216 20.281 9.234 20.443 ;
     RECT  2.304 20.309 3.474 20.525 ;
     RECT  67.788 20.203 69.03 20.683 ;
     RECT  67.752 20.683 69.03 20.779 ;
     RECT  4.212 20.309 8.334 20.885 ;
     RECT  60.3 20.309 64.818 20.885 ;
     RECT  6.768 20.885 8.334 20.965 ;
     RECT  2.376 20.525 3.474 21.091 ;
     RECT  4.212 20.885 6.03 21.091 ;
     RECT  6.768 20.965 8.37 21.091 ;
     RECT  9.216 20.443 9.27 21.091 ;
     RECT  47.268 20.389 48.798 21.091 ;
     RECT  65.736 21.001 65.754 21.127 ;
     RECT  10.8 21.127 10.818 21.163 ;
     RECT  64.656 20.885 64.818 21.163 ;
     RECT  65.736 21.127 66.402 21.163 ;
     RECT  46.764 21.091 48.798 21.235 ;
     RECT  67.716 20.779 69.03 21.235 ;
     RECT  6.768 21.091 9.378 21.263 ;
     RECT  10.8 21.163 10.854 21.271 ;
     RECT  64.656 21.163 66.402 21.271 ;
     RECT  60.3 20.885 63.81 21.299 ;
     RECT  67.284 21.235 69.03 21.355 ;
     RECT  51.015 2.413 51.297 21.361 ;
     RECT  58.716 20.929 58.734 21.361 ;
     RECT  10.728 21.271 10.854 21.389 ;
     RECT  0.144 19.805 0.162 21.403 ;
     RECT  60.3 21.299 62.406 21.425 ;
     RECT  50.616 21.361 51.297 21.469 ;
     RECT  42.804 21.433 42.822 21.533 ;
     RECT  58.716 21.361 58.878 21.533 ;
     RECT  2.376 21.091 6.03 21.547 ;
     RECT  67.248 21.355 69.03 21.569 ;
     RECT  64.656 21.271 66.438 21.586 ;
     RECT  67.248 21.569 68.418 21.586 ;
     RECT  2.304 21.547 6.03 21.631 ;
     RECT  6.768 21.263 9.306 21.631 ;
     RECT  46.764 21.235 48.834 21.631 ;
     RECT  63.288 21.299 63.81 21.631 ;
     RECT  64.656 21.586 68.418 21.631 ;
     RECT  0.144 21.403 0.234 21.643 ;
     RECT  2.304 21.631 9.306 21.659 ;
     RECT  50.544 21.469 51.297 21.659 ;
     RECT  3.996 21.659 9.306 21.695 ;
     RECT  0.144 21.643 0.342 21.739 ;
     RECT  46.764 21.631 49.23 21.775 ;
     RECT  0.108 21.739 0.342 21.971 ;
     RECT  46.764 21.775 49.806 22.009 ;
     RECT  10.764 21.389 10.782 22.037 ;
     RECT  29.415 6.305 29.697 22.045 ;
     RECT  63.288 21.631 68.418 22.061 ;
     RECT  3.996 21.695 8.514 22.073 ;
     RECT  58.716 21.533 58.806 22.073 ;
     RECT  9.252 21.695 9.306 22.081 ;
     RECT  60.624 21.425 62.406 22.081 ;
     RECT  63.288 22.061 68.382 22.081 ;
     RECT  0.18 21.971 0.342 22.109 ;
     RECT  46.764 22.009 50.202 22.109 ;
     RECT  60.624 22.081 68.382 22.109 ;
     RECT  56.415 2.413 56.697 22.171 ;
     RECT  60.624 22.109 61.002 22.199 ;
     RECT  56.304 22.171 56.697 22.207 ;
     RECT  61.776 22.109 66.546 22.235 ;
     RECT  56.232 22.207 56.697 22.253 ;
     RECT  9.252 22.081 9.342 22.279 ;
     RECT  2.304 21.659 3.078 22.477 ;
     RECT  3.996 22.073 8.442 22.477 ;
     RECT  0.216 22.109 0.342 22.541 ;
     RECT  2.304 22.477 8.442 22.541 ;
     RECT  46.8 22.109 50.202 22.541 ;
     RECT  47.34 22.541 50.202 22.585 ;
     RECT  51.015 21.659 51.297 22.585 ;
     RECT  67.284 22.109 68.382 22.739 ;
     RECT  28.8 22.045 29.697 22.819 ;
     RECT  58.788 22.073 58.806 22.819 ;
     RECT  60.84 22.199 61.002 22.981 ;
     RECT  61.776 22.235 66.438 22.981 ;
     RECT  0.144 22.843 0.198 23.017 ;
     RECT  9.252 22.279 9.45 23.017 ;
     RECT  6.624 22.541 8.442 23.089 ;
     RECT  9.216 23.017 9.45 23.089 ;
     RECT  60.84 22.981 66.438 23.089 ;
     RECT  67.284 22.739 67.95 23.089 ;
     RECT  60.84 23.089 67.95 23.125 ;
     RECT  59.868 22.795 59.886 23.161 ;
     RECT  60.732 23.125 67.95 23.161 ;
     RECT  59.868 23.161 67.95 23.165 ;
     RECT  59.868 23.165 60.03 23.279 ;
     RECT  60.804 23.165 67.95 23.279 ;
     RECT  2.304 22.541 5.85 23.309 ;
     RECT  6.624 23.089 9.45 23.315 ;
     RECT  59.868 23.279 59.886 23.315 ;
     RECT  47.34 22.585 51.297 23.359 ;
     RECT  46.764 23.359 51.297 23.431 ;
     RECT  18.504 20.389 22.518 23.557 ;
     RECT  46.764 23.431 51.354 23.557 ;
     RECT  58.716 22.819 58.806 23.557 ;
     RECT  60.984 23.279 67.95 23.557 ;
     RECT  69.012 22.891 69.03 23.557 ;
     RECT  46.764 23.557 51.39 23.585 ;
     RECT  2.376 23.309 5.85 23.593 ;
     RECT  6.624 23.315 9.414 23.593 ;
     RECT  60.984 23.557 69.03 23.621 ;
     RECT  46.8 23.585 51.39 23.665 ;
     RECT  10.836 23.521 10.926 23.693 ;
     RECT  58.716 23.557 58.842 23.701 ;
     RECT  58.716 23.701 58.914 23.819 ;
     RECT  2.376 23.593 9.414 23.891 ;
     RECT  58.896 23.819 58.914 23.891 ;
     RECT  10.908 23.693 10.926 23.927 ;
     RECT  54.684 23.701 54.702 23.927 ;
     RECT  61.092 23.621 69.03 23.933 ;
     RECT  61.128 23.933 69.03 23.999 ;
     RECT  59.868 24.091 59.886 24.131 ;
     RECT  61.596 23.999 69.03 24.161 ;
     RECT  18.504 23.557 23.238 24.169 ;
     RECT  24.015 20.039 24.297 24.169 ;
     RECT  9.396 23.891 9.414 24.205 ;
     RECT  9.396 24.205 9.486 24.233 ;
     RECT  46.8 23.665 51.534 24.233 ;
     RECT  61.596 24.161 63.846 24.233 ;
     RECT  2.376 23.891 8.658 24.235 ;
     RECT  64.62 24.161 69.03 24.269 ;
     RECT  46.872 24.233 51.534 24.331 ;
     RECT  2.268 24.235 8.658 24.359 ;
     RECT  64.62 24.269 66.618 24.359 ;
     RECT  9.468 24.233 9.486 24.395 ;
     RECT  28.404 22.819 29.697 24.403 ;
     RECT  2.304 24.359 8.658 24.431 ;
     RECT  46.872 24.331 51.606 24.431 ;
     RECT  2.304 24.431 8.586 24.461 ;
     RECT  46.908 24.431 51.606 24.467 ;
     RECT  28.332 24.403 29.697 24.511 ;
     RECT  64.692 24.359 66.618 24.539 ;
     RECT  34.815 10.741 35.622 24.601 ;
     RECT  64.728 24.539 66.618 24.737 ;
     RECT  58.752 24.673 58.77 24.745 ;
     RECT  0.108 23.017 0.198 24.811 ;
     RECT  60.984 24.745 61.002 24.859 ;
     RECT  59.76 24.901 59.778 24.904 ;
     RECT  60.84 24.859 61.002 24.904 ;
     RECT  59.76 24.904 61.002 24.935 ;
     RECT  67.788 24.269 69.03 24.935 ;
     RECT  59.76 24.935 60.498 24.941 ;
     RECT  67.788 24.935 68.418 25.003 ;
     RECT  0.108 24.811 0.342 25.051 ;
     RECT  28.332 24.511 29.898 25.051 ;
     RECT  41.868 24.709 41.886 25.051 ;
     RECT  0.108 25.051 0.558 25.133 ;
     RECT  59.904 24.941 60.498 25.169 ;
     RECT  61.815 24.233 63.846 25.243 ;
     RECT  2.304 24.461 4.986 25.249 ;
     RECT  5.796 24.461 8.586 25.249 ;
     RECT  18.504 24.169 24.297 25.249 ;
     RECT  58.716 24.745 58.77 25.249 ;
     RECT  2.304 25.249 8.766 25.285 ;
     RECT  18.504 25.249 24.39 25.285 ;
     RECT  61.308 25.243 63.846 25.285 ;
     RECT  64.728 24.737 65.034 25.285 ;
     RECT  2.304 25.285 9.198 25.321 ;
     RECT  18.504 25.285 24.498 25.321 ;
     RECT  65.772 24.737 66.618 25.387 ;
     RECT  67.752 25.003 68.418 25.387 ;
     RECT  61.308 25.285 65.034 25.439 ;
     RECT  61.308 25.439 64.782 25.511 ;
     RECT  65.772 25.387 68.418 25.519 ;
     RECT  58.716 25.249 58.806 25.583 ;
     RECT  65.7 25.519 68.418 25.619 ;
     RECT  18.504 25.321 24.822 25.681 ;
     RECT  58.788 25.583 58.806 25.681 ;
     RECT  28.332 25.051 30.474 25.789 ;
     RECT  58.788 25.681 58.842 25.789 ;
     RECT  65.736 25.619 66.69 25.817 ;
     RECT  28.332 25.789 30.618 25.861 ;
     RECT  10.764 25.411 10.782 25.889 ;
     RECT  0.108 25.133 0.234 25.901 ;
     RECT  0.144 25.901 0.234 25.963 ;
     RECT  26.856 25.825 26.874 25.979 ;
     RECT  58.788 25.789 58.878 26.051 ;
     RECT  67.752 25.619 68.418 26.059 ;
     RECT  0.144 25.963 0.342 26.093 ;
     RECT  18.504 25.681 25.182 26.095 ;
     RECT  58.86 26.051 58.878 26.123 ;
     RECT  59.904 25.169 60.21 26.203 ;
     RECT  61.056 25.675 61.074 26.203 ;
     RECT  18.504 26.095 25.362 26.221 ;
     RECT  2.304 25.321 9.27 26.251 ;
     RECT  18.504 26.221 25.506 26.257 ;
     RECT  2.304 26.251 9.666 26.291 ;
     RECT  28.332 25.861 31.122 26.365 ;
     RECT  31.932 26.329 31.95 26.365 ;
     RECT  67.752 26.059 69.03 26.365 ;
     RECT  10.908 26.257 10.998 26.393 ;
     RECT  2.304 26.291 9.594 26.401 ;
     RECT  59.904 26.203 61.074 26.401 ;
     RECT  61.815 25.511 64.782 26.401 ;
     RECT  65.736 25.817 66.438 26.401 ;
     RECT  65.664 26.401 66.438 26.539 ;
     RECT  67.284 26.365 69.03 26.539 ;
     RECT  10.908 26.393 10.926 26.555 ;
     RECT  59.904 26.401 64.782 26.555 ;
     RECT  28.332 26.365 31.95 26.635 ;
     RECT  60.192 26.555 64.782 26.635 ;
     RECT  60.192 26.635 64.818 26.761 ;
     RECT  0.144 26.093 0.162 26.765 ;
     RECT  65.664 26.539 69.03 26.765 ;
     RECT  28.332 26.635 31.986 26.797 ;
     RECT  60.192 26.761 64.89 26.825 ;
     RECT  65.664 26.765 67.878 26.861 ;
     RECT  18.504 26.257 26.226 26.869 ;
     RECT  28.26 26.797 31.986 26.869 ;
     RECT  2.268 26.401 9.594 26.933 ;
     RECT  2.268 26.933 9.522 26.969 ;
     RECT  10.8 26.941 10.818 27.059 ;
     RECT  60.336 26.825 64.89 27.103 ;
     RECT  65.664 26.861 67.842 27.103 ;
     RECT  18.504 26.869 26.802 27.139 ;
     RECT  60.336 27.103 67.842 27.203 ;
     RECT  68.94 26.765 69.03 27.245 ;
     RECT  2.268 26.969 9.306 27.301 ;
     RECT  2.16 27.301 9.306 27.341 ;
     RECT  28.152 26.869 31.986 27.373 ;
     RECT  58.716 26.869 58.734 27.373 ;
     RECT  0.54 26.905 0.558 27.451 ;
     RECT  0.54 27.451 0.63 27.509 ;
     RECT  0.54 27.509 0.558 27.533 ;
     RECT  58.716 27.373 58.842 27.599 ;
     RECT  18.504 27.139 26.946 27.607 ;
     RECT  27.864 27.373 31.986 27.607 ;
     RECT  60.444 27.203 67.842 27.607 ;
     RECT  60.444 27.607 67.878 27.707 ;
     RECT  67.248 27.707 67.878 27.779 ;
     RECT  58.752 27.599 58.842 27.869 ;
     RECT  0.324 27.787 0.342 27.917 ;
     RECT  10.8 27.841 10.818 27.941 ;
     RECT  69.012 27.245 69.03 28.013 ;
     RECT  58.788 27.869 58.842 28.021 ;
     RECT  2.415 27.341 9.306 28.075 ;
     RECT  2.304 28.075 9.306 28.111 ;
     RECT  2.304 28.111 9.558 28.211 ;
     RECT  58.788 28.021 58.878 28.211 ;
     RECT  67.284 27.779 67.878 28.267 ;
     RECT  2.304 28.211 9.486 28.319 ;
     RECT  0.18 28.219 0.198 28.444 ;
     RECT  60.444 27.707 66.186 28.453 ;
     RECT  60.444 28.453 66.33 28.493 ;
     RECT  60.444 28.493 65.646 28.561 ;
     RECT  2.304 28.319 9.45 28.589 ;
     RECT  10.764 28.525 10.782 28.678 ;
     RECT  0.108 28.444 0.198 28.685 ;
     RECT  67.284 28.267 68.454 28.685 ;
     RECT  0.18 28.685 0.198 28.733 ;
     RECT  60.084 28.561 65.646 28.795 ;
     RECT  59.868 28.795 65.646 28.823 ;
     RECT  10.728 28.678 10.818 28.859 ;
     RECT  59.868 28.823 64.962 28.949 ;
     RECT  18.504 27.607 31.986 29.065 ;
     RECT  67.284 28.685 68.418 29.065 ;
     RECT  58.788 28.211 58.806 29.101 ;
     RECT  18.504 29.065 32.31 29.299 ;
     RECT  2.304 28.589 9.414 29.323 ;
     RECT  59.868 28.949 64.782 29.327 ;
     RECT  58.788 29.101 58.878 29.335 ;
     RECT  59.868 29.327 62.55 29.335 ;
     RECT  2.304 29.323 9.486 29.363 ;
     RECT  2.304 29.363 9.414 29.399 ;
     RECT  58.788 29.335 62.55 29.461 ;
     RECT  58.716 29.461 62.55 29.489 ;
     RECT  66.564 29.065 68.418 29.497 ;
     RECT  60.84 29.489 62.55 29.597 ;
     RECT  66.42 29.497 68.418 29.597 ;
     RECT  66.672 29.597 68.418 29.611 ;
     RECT  63.324 29.327 64.782 29.731 ;
     RECT  10.8 28.859 10.818 29.767 ;
     RECT  18.504 29.299 32.778 29.803 ;
     RECT  0.144 29.707 0.162 29.885 ;
     RECT  10.8 29.767 10.854 29.911 ;
     RECT  66.672 29.611 69.03 29.933 ;
     RECT  2.415 29.399 9.414 29.939 ;
     RECT  58.716 29.489 59.994 29.939 ;
     RECT  10.8 29.911 10.926 30.029 ;
     RECT  67.752 29.933 69.03 30.035 ;
     RECT  66.672 29.933 66.726 30.065 ;
     RECT  18.504 29.803 32.814 30.109 ;
     RECT  18.504 30.109 32.922 30.307 ;
     RECT  60.84 29.597 62.298 30.307 ;
     RECT  60.732 30.307 62.298 30.331 ;
     RECT  63.324 29.731 65.286 30.331 ;
     RECT  59.724 29.939 59.994 30.365 ;
     RECT  60.732 30.331 65.286 30.415 ;
     RECT  18.504 30.307 33.39 30.451 ;
     RECT  59.796 30.365 59.994 30.451 ;
     RECT  60.732 30.415 65.538 30.451 ;
     RECT  2.415 29.939 3.618 30.479 ;
     RECT  59.796 30.451 65.538 30.479 ;
     RECT  59.868 30.479 64.782 30.569 ;
     RECT  60.012 30.569 64.782 30.605 ;
     RECT  18.504 30.451 33.498 30.649 ;
     RECT  66.708 30.065 66.726 30.667 ;
     RECT  67.752 30.035 68.418 30.667 ;
     RECT  4.464 29.939 9.414 30.721 ;
     RECT  34.815 24.601 36.198 30.721 ;
     RECT  58.716 29.939 58.806 30.749 ;
     RECT  66.708 30.667 68.418 30.763 ;
     RECT  2.415 30.479 3.294 30.811 ;
     RECT  65.52 30.479 65.538 30.811 ;
     RECT  66.708 30.763 68.958 30.811 ;
     RECT  18.504 30.649 33.57 30.847 ;
     RECT  65.52 30.811 65.574 30.847 ;
     RECT  66.312 30.811 68.958 30.847 ;
     RECT  65.52 30.847 68.958 30.875 ;
     RECT  10.8 30.029 10.818 30.883 ;
     RECT  58.752 30.749 58.806 30.883 ;
     RECT  0.324 30.763 0.342 30.907 ;
     RECT  10.728 30.883 10.818 30.983 ;
     RECT  66.6 30.875 68.958 30.989 ;
     RECT  60.408 30.605 64.782 31.019 ;
     RECT  0.216 30.907 0.342 31.085 ;
     RECT  18.504 30.847 33.606 31.117 ;
     RECT  34.524 30.721 36.198 31.117 ;
     RECT  41.292 25.051 41.886 31.189 ;
     RECT  58.752 30.883 58.878 31.189 ;
     RECT  4.14 30.721 9.414 31.243 ;
     RECT  2.304 30.811 3.294 31.289 ;
     RECT  10.8 30.983 10.818 31.289 ;
     RECT  58.752 31.189 58.914 31.289 ;
     RECT  60.408 31.019 60.426 31.351 ;
     RECT  61.2 31.019 64.782 31.387 ;
     RECT  65.52 30.875 65.862 31.387 ;
     RECT  18.504 31.117 36.198 31.495 ;
     RECT  61.2 31.387 65.862 31.523 ;
     RECT  58.752 31.289 58.806 31.531 ;
     RECT  60.084 31.351 60.426 31.531 ;
     RECT  60.012 31.531 60.426 31.565 ;
     RECT  10.836 31.423 10.854 31.649 ;
     RECT  61.38 31.523 65.862 31.693 ;
     RECT  66.6 30.989 67.806 31.693 ;
     RECT  41.292 31.189 42.21 31.801 ;
     RECT  0.504 31.153 0.522 31.891 ;
     RECT  0.504 31.891 0.558 31.949 ;
     RECT  61.38 31.693 67.806 31.963 ;
     RECT  2.412 31.289 3.294 32.071 ;
     RECT  4.032 31.243 9.414 32.071 ;
     RECT  58.716 31.531 58.806 32.071 ;
     RECT  61.38 31.963 67.842 32.071 ;
     RECT  0.504 31.949 0.522 32.141 ;
     RECT  2.412 32.071 9.414 32.233 ;
     RECT  61.38 32.071 67.878 32.237 ;
     RECT  40.215 8.969 40.497 32.269 ;
     RECT  41.292 31.801 42.786 32.269 ;
     RECT  61.38 32.237 66.618 32.269 ;
     RECT  67.788 32.237 67.878 32.269 ;
     RECT  68.976 31.243 69.03 32.269 ;
     RECT  61.2 32.269 66.618 32.297 ;
     RECT  60.012 31.565 60.03 32.341 ;
     RECT  61.2 32.297 66.33 32.341 ;
     RECT  67.788 32.269 69.03 32.429 ;
     RECT  59.832 32.341 60.03 32.443 ;
     RECT  60.768 32.341 66.33 32.443 ;
     RECT  59.832 32.443 66.33 32.495 ;
     RECT  2.304 32.233 9.414 32.737 ;
     RECT  2.304 32.737 9.522 32.837 ;
     RECT  58.716 32.071 58.878 32.845 ;
     RECT  2.304 32.837 9.45 32.909 ;
     RECT  67.788 32.429 67.878 32.965 ;
     RECT  58.716 32.845 58.914 33.071 ;
     RECT  59.832 32.495 64.782 33.071 ;
     RECT  0.54 33.043 0.558 33.101 ;
     RECT  67.284 32.965 67.878 33.151 ;
     RECT  69.012 32.429 69.03 33.151 ;
     RECT  67.284 33.151 69.03 33.163 ;
     RECT  59.868 33.071 64.782 33.349 ;
     RECT  65.592 32.495 66.33 33.349 ;
     RECT  59.868 33.349 66.33 33.385 ;
     RECT  2.304 32.909 9.414 33.448 ;
     RECT  59.868 33.385 66.474 33.449 ;
     RECT  2.268 33.448 9.414 33.539 ;
     RECT  10.764 33.421 10.782 33.539 ;
     RECT  40.215 32.269 42.786 33.817 ;
     RECT  58.716 33.071 58.806 33.881 ;
     RECT  0.144 33.739 0.162 33.917 ;
     RECT  67.248 33.163 69.03 33.917 ;
     RECT  0.324 34.027 0.342 34.051 ;
     RECT  40.215 33.817 43.326 34.123 ;
     RECT  2.304 33.539 9.414 34.187 ;
     RECT  60.048 33.449 66.474 34.219 ;
     RECT  67.284 33.917 69.03 34.223 ;
     RECT  40.215 34.123 43.65 34.231 ;
     RECT  60.048 34.219 66.51 34.231 ;
     RECT  0.324 34.051 0.558 34.253 ;
     RECT  59.796 34.231 66.51 34.301 ;
     RECT  59.868 34.301 66.51 34.349 ;
     RECT  59.868 34.349 60.066 34.385 ;
     RECT  59.976 34.385 60.066 34.493 ;
     RECT  40.215 34.231 44.19 34.501 ;
     RECT  61.092 34.349 66.51 34.529 ;
     RECT  2.304 34.187 4.95 34.603 ;
     RECT  61.092 34.529 63.738 34.619 ;
     RECT  67.284 34.223 68.418 34.637 ;
     RECT  5.904 34.187 9.414 34.651 ;
     RECT  61.164 34.619 63.558 34.655 ;
     RECT  5.904 34.651 9.522 34.691 ;
     RECT  61.164 34.655 63.486 34.691 ;
     RECT  2.16 34.603 4.95 34.727 ;
     RECT  64.584 34.529 66.51 34.771 ;
     RECT  58.716 33.881 58.77 34.861 ;
     RECT  2.304 34.727 4.95 34.939 ;
     RECT  5.904 34.691 9.486 34.939 ;
     RECT  0.144 34.795 0.162 34.973 ;
     RECT  58.716 34.861 58.806 35.033 ;
     RECT  64.584 34.771 66.726 35.117 ;
     RECT  67.788 34.637 68.418 35.159 ;
     RECT  64.584 35.117 66.222 35.195 ;
     RECT  61.38 34.691 63.486 35.231 ;
     RECT  59.976 34.493 59.994 35.401 ;
     RECT  59.976 35.401 60.534 35.437 ;
     RECT  68.364 35.159 68.418 35.467 ;
     RECT  63.036 35.231 63.486 35.509 ;
     RECT  59.904 35.437 60.534 35.581 ;
     RECT  61.38 35.231 62.298 35.581 ;
     RECT  2.304 34.939 9.486 35.609 ;
     RECT  18.504 31.495 36.774 35.671 ;
     RECT  37.872 31.765 37.89 35.671 ;
     RECT  64.584 35.195 65.538 35.707 ;
     RECT  0.54 35.311 0.558 35.74 ;
     RECT  59.868 35.581 62.298 35.803 ;
     RECT  63.036 35.509 63.666 35.803 ;
     RECT  64.44 35.707 65.538 35.803 ;
     RECT  54.72 35.779 54.738 35.879 ;
     RECT  59.796 35.803 62.298 35.879 ;
     RECT  0.108 35.74 0.558 35.885 ;
     RECT  9.216 35.609 9.486 35.941 ;
     RECT  63.036 35.803 65.538 35.941 ;
     RECT  67.248 35.371 67.302 36.043 ;
     RECT  68.364 35.467 69.03 36.043 ;
     RECT  60.84 35.879 62.298 36.049 ;
     RECT  63.036 35.941 65.682 36.049 ;
     RECT  67.248 36.043 69.03 36.049 ;
     RECT  9.216 35.941 9.738 36.275 ;
     RECT  2.304 35.609 8.37 36.347 ;
     RECT  18.504 35.671 37.89 36.391 ;
     RECT  60.84 36.049 65.682 36.391 ;
     RECT  9.216 36.275 9.666 36.419 ;
     RECT  2.412 36.347 8.37 36.481 ;
     RECT  66.6 36.049 69.03 36.553 ;
     RECT  58.788 35.033 58.806 36.571 ;
     RECT  18.504 36.391 38.466 36.589 ;
     RECT  58.752 36.571 58.806 36.589 ;
     RECT  59.868 35.879 59.958 36.661 ;
     RECT  60.84 36.391 65.79 36.661 ;
     RECT  66.528 36.553 69.03 36.661 ;
     RECT  59.796 36.661 60.03 36.701 ;
     RECT  0.54 35.885 0.558 36.749 ;
     RECT  60.84 36.661 69.03 36.887 ;
     RECT  59.868 36.701 60.03 36.907 ;
     RECT  60.84 36.887 65.286 36.907 ;
     RECT  2.412 36.481 8.658 36.923 ;
     RECT  10.8 36.787 10.818 36.923 ;
     RECT  66.096 36.887 68.418 37.037 ;
     RECT  54.72 36.931 54.738 37.049 ;
     RECT  2.412 36.923 8.586 37.192 ;
     RECT  58.716 36.589 58.806 37.201 ;
     RECT  18.504 36.589 38.754 37.229 ;
     RECT  58.716 37.201 58.842 37.229 ;
     RECT  2.304 37.192 8.586 37.355 ;
     RECT  10.836 37.291 10.854 37.391 ;
     RECT  9.432 36.419 9.666 37.427 ;
     RECT  9.432 37.427 9.486 37.471 ;
     RECT  58.788 37.229 58.842 37.499 ;
     RECT  0.144 37.339 0.162 37.561 ;
     RECT  66.096 37.037 68.382 37.613 ;
     RECT  0.144 37.561 0.558 37.805 ;
     RECT  67.752 37.613 68.382 37.867 ;
     RECT  2.304 37.355 8.37 37.895 ;
     RECT  67.752 37.867 69.03 37.967 ;
     RECT  59.868 36.907 65.286 37.975 ;
     RECT  66.096 37.613 66.726 37.975 ;
     RECT  59.868 37.975 66.726 38.039 ;
     RECT  65.412 38.039 66.726 38.093 ;
     RECT  10.8 38.011 10.818 38.129 ;
     RECT  60.84 38.039 64.674 38.129 ;
     RECT  65.412 38.093 66.69 38.129 ;
     RECT  67.752 37.967 67.806 38.129 ;
     RECT  65.448 38.129 66.69 38.201 ;
     RECT  67.752 38.129 67.77 38.201 ;
     RECT  9.36 37.471 9.486 38.209 ;
     RECT  4.032 37.895 8.37 38.251 ;
     RECT  4.032 38.251 8.55 38.371 ;
     RECT  9.288 38.209 9.486 38.371 ;
     RECT  65.484 38.201 66.69 38.399 ;
     RECT  4.032 38.371 9.486 38.435 ;
     RECT  59.868 38.039 60.102 38.435 ;
     RECT  61.488 38.129 64.674 38.435 ;
     RECT  69.012 37.967 69.03 38.435 ;
     RECT  58.716 38.011 58.734 38.443 ;
     RECT  66.672 38.399 66.69 38.579 ;
     RECT  2.304 37.895 3.294 38.641 ;
     RECT  4.032 38.435 8.37 38.641 ;
     RECT  0.144 37.805 0.234 38.669 ;
     RECT  61.488 38.435 63.918 38.765 ;
     RECT  0.144 38.669 0.198 38.785 ;
     RECT  2.304 38.641 8.37 38.849 ;
     RECT  2.304 38.849 5.526 38.923 ;
     RECT  10.656 38.821 10.674 38.947 ;
     RECT  2.268 38.923 5.526 38.975 ;
     RECT  10.656 38.947 10.746 38.975 ;
     RECT  18.504 37.229 38.502 39.019 ;
     RECT  2.304 38.975 5.526 39.047 ;
     RECT  65.484 38.399 65.574 39.055 ;
     RECT  58.716 38.443 58.806 39.091 ;
     RECT  18.504 39.019 38.538 39.119 ;
     RECT  6.516 38.849 8.37 39.209 ;
     RECT  9.144 38.435 9.486 39.209 ;
     RECT  58.716 39.091 58.878 39.245 ;
     RECT  68.4 39.181 68.418 39.307 ;
     RECT  60.084 38.435 60.102 39.325 ;
     RECT  67.284 39.091 67.302 39.325 ;
     RECT  68.364 39.307 68.418 39.325 ;
     RECT  59.868 39.325 60.102 39.353 ;
     RECT  61.815 38.765 63.918 39.361 ;
     RECT  64.764 39.055 65.574 39.361 ;
     RECT  66.6 39.325 68.418 39.533 ;
     RECT  10.692 38.975 10.746 39.559 ;
     RECT  61.815 39.361 65.574 39.559 ;
     RECT  6.516 39.209 8.226 39.595 ;
     RECT  61.815 39.559 65.79 39.595 ;
     RECT  66.6 39.533 66.726 39.595 ;
     RECT  10.692 39.559 10.854 39.623 ;
     RECT  58.716 39.245 58.842 39.623 ;
     RECT  9.18 39.209 9.486 39.631 ;
     RECT  10.764 39.623 10.854 39.659 ;
     RECT  58.752 39.623 58.842 39.659 ;
     RECT  4.032 39.047 5.526 39.721 ;
     RECT  10.836 39.659 10.854 39.749 ;
     RECT  4.032 39.721 5.67 39.787 ;
     RECT  6.408 39.595 8.226 39.787 ;
     RECT  58.824 39.659 58.842 39.857 ;
     RECT  2.304 39.047 3.294 39.901 ;
     RECT  4.032 39.787 8.226 39.901 ;
     RECT  2.304 39.901 8.226 39.979 ;
     RECT  2.268 39.979 8.226 39.991 ;
     RECT  2.268 39.991 8.298 40.063 ;
     RECT  9.18 39.631 9.594 40.063 ;
     RECT  61.815 39.595 66.726 40.099 ;
     RECT  67.788 39.533 68.418 40.171 ;
     RECT  2.268 40.063 9.594 40.199 ;
     RECT  61.488 40.099 66.726 40.199 ;
     RECT  18.504 39.119 38.502 40.261 ;
     RECT  2.304 40.199 5.814 40.289 ;
     RECT  6.696 40.199 8.298 40.289 ;
     RECT  9.072 40.199 9.594 40.289 ;
     RECT  65.736 40.199 66.726 40.289 ;
     RECT  61.488 40.199 64.998 40.411 ;
     RECT  0.108 38.785 0.198 40.459 ;
     RECT  9.072 40.289 9.234 40.469 ;
     RECT  18.504 40.261 38.79 40.567 ;
     RECT  0.108 40.459 0.342 40.589 ;
     RECT  66.348 40.289 66.726 40.589 ;
     RECT  0.108 40.589 0.234 40.595 ;
     RECT  0.144 40.595 0.234 40.637 ;
     RECT  2.304 40.289 5.742 40.667 ;
     RECT  58.788 40.567 58.806 40.702 ;
     RECT  58.752 40.702 58.806 40.703 ;
     RECT  59.868 39.353 60.03 40.711 ;
     RECT  18.504 40.567 38.934 40.739 ;
     RECT  66.348 40.589 66.69 40.739 ;
     RECT  58.752 40.703 58.77 40.801 ;
     RECT  18.504 40.739 38.862 40.829 ;
     RECT  61.344 40.411 64.998 40.865 ;
     RECT  63.468 40.865 64.998 40.877 ;
     RECT  59.868 40.711 60.39 40.909 ;
     RECT  61.344 40.865 62.73 40.909 ;
     RECT  10.8 40.837 10.818 40.937 ;
     RECT  59.868 40.909 62.73 40.937 ;
     RECT  66.672 40.739 66.69 40.973 ;
     RECT  61.056 40.937 62.73 41.009 ;
     RECT  4.284 40.667 5.742 41.071 ;
     RECT  6.84 40.289 8.298 41.071 ;
     RECT  45.615 7.763 45.897 41.071 ;
     RECT  56.415 22.253 56.697 41.071 ;
     RECT  45.504 41.071 45.897 41.117 ;
     RECT  56.304 41.071 56.697 41.117 ;
     RECT  2.304 40.667 3.51 41.207 ;
     RECT  9.216 40.469 9.234 41.279 ;
     RECT  4.284 41.071 8.298 41.341 ;
     RECT  0.144 40.637 0.162 41.357 ;
     RECT  61.2 41.009 62.694 41.405 ;
     RECT  67.788 40.171 69.03 41.413 ;
     RECT  4.284 41.341 8.91 41.449 ;
     RECT  66.708 41.413 69.03 41.453 ;
     RECT  58.716 40.801 58.77 41.501 ;
     RECT  0.216 41.371 0.234 41.549 ;
     RECT  65.88 41.251 65.898 41.549 ;
     RECT  18.504 40.829 38.43 41.611 ;
     RECT  58.752 41.501 58.77 41.611 ;
     RECT  18.504 41.611 38.826 41.647 ;
     RECT  2.412 41.207 3.51 41.683 ;
     RECT  4.248 41.449 8.91 41.683 ;
     RECT  1.26 41.611 1.278 41.707 ;
     RECT  1.152 41.707 1.278 41.741 ;
     RECT  59.868 40.937 59.886 41.755 ;
     RECT  61.38 41.405 62.694 41.791 ;
     RECT  63.468 40.877 64.962 41.791 ;
     RECT  67.752 41.453 69.03 41.819 ;
     RECT  18.504 41.647 38.97 41.908 ;
     RECT  2.412 41.683 8.91 41.909 ;
     RECT  66.708 41.453 66.726 41.933 ;
     RECT  58.752 41.611 58.842 41.947 ;
     RECT  18.504 41.908 39.006 41.953 ;
     RECT  1.152 41.741 1.17 41.981 ;
     RECT  5.616 41.909 8.91 41.981 ;
     RECT  10.8 41.791 10.818 41.981 ;
     RECT  18.504 41.953 39.078 41.981 ;
     RECT  61.38 41.791 64.962 41.995 ;
     RECT  45.615 41.117 45.897 42.043 ;
     RECT  56.415 41.117 56.697 42.043 ;
     RECT  2.412 41.909 4.77 42.061 ;
     RECT  58.752 41.947 58.878 42.077 ;
     RECT  18.576 41.981 39.078 42.089 ;
     RECT  45.504 42.043 45.897 42.089 ;
     RECT  56.304 42.043 56.697 42.089 ;
     RECT  61.38 41.995 65.07 42.179 ;
     RECT  59.868 41.755 60.03 42.259 ;
     RECT  59.868 42.259 60.21 42.295 ;
     RECT  14.832 42.259 14.85 42.331 ;
     RECT  59.868 42.295 60.462 42.331 ;
     RECT  61.38 42.179 62.37 42.331 ;
     RECT  2.304 42.061 4.77 42.359 ;
     RECT  0.54 42.151 0.558 42.413 ;
     RECT  58.752 42.077 58.77 42.427 ;
     RECT  67.752 41.819 68.382 42.493 ;
     RECT  14.832 42.331 14.886 42.557 ;
     RECT  18.576 42.089 39.006 42.557 ;
     RECT  67.284 42.493 68.382 42.557 ;
     RECT  18.576 42.557 38.934 42.593 ;
     RECT  58.716 42.427 58.77 42.593 ;
     RECT  59.868 42.331 62.37 42.601 ;
     RECT  14.832 42.557 14.85 42.629 ;
     RECT  18.576 42.593 38.862 42.629 ;
     RECT  63.288 42.179 65.07 42.691 ;
     RECT  65.952 41.989 66.402 42.691 ;
     RECT  2.304 42.359 3.294 42.701 ;
     RECT  67.284 42.557 67.914 42.701 ;
     RECT  59.724 42.601 62.37 42.719 ;
     RECT  63.288 42.691 66.402 42.727 ;
     RECT  4.14 42.359 4.77 42.763 ;
     RECT  5.616 41.981 8.838 42.763 ;
     RECT  5.616 42.763 9.342 42.799 ;
     RECT  4.14 42.763 4.878 42.859 ;
     RECT  5.616 42.799 9.486 42.859 ;
     RECT  4.14 42.859 9.486 42.989 ;
     RECT  10.8 42.763 10.818 42.989 ;
     RECT  18.576 42.629 38.826 43.061 ;
     RECT  63.288 42.727 66.474 43.069 ;
     RECT  2.415 42.701 3.294 43.105 ;
     RECT  63.288 43.069 66.726 43.181 ;
     RECT  45.615 42.089 45.897 43.231 ;
     RECT  56.415 42.089 56.697 43.231 ;
     RECT  4.176 42.989 9.486 43.259 ;
     RECT  63.288 43.181 66.546 43.259 ;
     RECT  63.288 43.259 64.494 43.267 ;
     RECT  0.108 43.18 0.198 43.277 ;
     RECT  56.304 43.231 56.697 43.277 ;
     RECT  65.34 43.259 66.366 43.295 ;
     RECT  0.144 43.277 0.198 43.303 ;
     RECT  14.868 43.339 14.886 43.375 ;
     RECT  45.504 43.231 45.897 43.375 ;
     RECT  2.415 43.105 3.33 43.411 ;
     RECT  40.215 34.501 44.73 43.411 ;
     RECT  45.468 43.375 45.897 43.411 ;
     RECT  59.868 42.719 62.37 43.411 ;
     RECT  63.144 43.267 64.494 43.411 ;
     RECT  67.788 42.701 67.914 43.411 ;
     RECT  69.012 43.303 69.03 43.411 ;
     RECT  2.415 43.411 3.402 43.435 ;
     RECT  67.788 43.411 69.03 43.435 ;
     RECT  59.868 43.411 64.494 43.529 ;
     RECT  0.144 43.303 0.558 43.565 ;
     RECT  14.868 43.375 14.958 43.601 ;
     RECT  4.32 43.259 9.486 43.609 ;
     RECT  10.764 43.537 10.782 43.673 ;
     RECT  2.376 43.435 3.402 43.675 ;
     RECT  4.32 43.609 9.558 43.709 ;
     RECT  14.868 43.601 14.886 43.709 ;
     RECT  59.868 43.529 60.894 43.709 ;
     RECT  67.752 43.435 69.03 43.757 ;
     RECT  67.752 43.757 67.806 43.771 ;
     RECT  4.32 43.709 9.486 43.835 ;
     RECT  58.716 42.593 58.734 43.915 ;
     RECT  2.304 43.675 3.402 44.041 ;
     RECT  4.32 43.835 9.054 44.041 ;
     RECT  59.868 43.709 60.03 44.059 ;
     RECT  65.34 43.295 66.33 44.077 ;
     RECT  0.144 43.565 0.414 44.105 ;
     RECT  59.724 44.059 60.03 44.105 ;
     RECT  40.215 43.411 45.897 44.113 ;
     RECT  0.144 44.105 0.342 44.141 ;
     RECT  2.304 44.041 9.054 44.149 ;
     RECT  65.304 44.077 66.33 44.149 ;
     RECT  67.284 43.771 67.806 44.149 ;
     RECT  61.668 43.529 64.494 44.203 ;
     RECT  65.304 44.149 67.806 44.203 ;
     RECT  58.716 43.915 58.95 44.213 ;
     RECT  60.84 43.709 60.894 44.213 ;
     RECT  2.268 44.149 9.054 44.237 ;
     RECT  61.668 44.203 67.806 44.285 ;
     RECT  0.144 44.141 0.234 44.299 ;
     RECT  59.796 44.105 60.03 44.339 ;
     RECT  61.668 44.285 62.37 44.339 ;
     RECT  58.716 44.213 58.914 44.375 ;
     RECT  40.215 44.113 45.99 44.383 ;
     RECT  68.904 43.757 69.03 44.411 ;
     RECT  61.668 44.339 62.334 44.443 ;
     RECT  2.304 44.237 9.054 44.447 ;
     RECT  68.904 44.411 68.994 44.447 ;
     RECT  63.288 44.285 67.806 44.581 ;
     RECT  68.904 44.447 68.958 44.581 ;
     RECT  0.108 44.299 0.234 44.609 ;
     RECT  40.215 44.383 46.206 44.689 ;
     RECT  0.144 44.609 0.234 44.813 ;
     RECT  10.8 44.689 10.818 44.879 ;
     RECT  0.216 44.813 0.234 44.909 ;
     RECT  63.288 44.581 68.958 44.909 ;
     RECT  2.304 44.447 8.514 44.915 ;
     RECT  59.796 44.339 59.994 44.915 ;
     RECT  40.215 44.689 46.242 44.923 ;
     RECT  60.912 44.443 62.334 45.031 ;
     RECT  60.876 45.031 62.334 45.121 ;
     RECT  63.288 44.909 66.762 45.121 ;
     RECT  58.716 44.375 58.806 45.157 ;
     RECT  18.576 43.061 38.43 45.229 ;
     RECT  60.876 45.121 66.762 45.229 ;
     RECT  18.576 45.229 38.79 45.265 ;
     RECT  60.84 45.229 66.762 45.293 ;
     RECT  9.288 45.031 9.306 45.301 ;
     RECT  2.304 44.915 5.742 45.355 ;
     RECT  59.868 44.915 59.994 45.391 ;
     RECT  9.288 45.301 9.342 45.419 ;
     RECT  40.215 44.923 46.566 45.427 ;
     RECT  47.34 24.467 51.462 45.427 ;
     RECT  67.788 44.909 68.958 45.451 ;
     RECT  58.716 45.157 58.914 45.455 ;
     RECT  60.84 45.293 66.186 45.455 ;
     RECT  58.716 45.455 58.806 45.491 ;
     RECT  60.948 45.455 62.478 45.491 ;
     RECT  17.676 43.069 17.694 45.527 ;
     RECT  2.268 45.355 5.742 45.599 ;
     RECT  59.868 45.391 60.03 45.599 ;
     RECT  6.84 44.915 8.514 45.661 ;
     RECT  6.588 45.661 8.514 45.697 ;
     RECT  9.288 45.419 9.306 45.697 ;
     RECT  60.948 45.491 61.002 45.725 ;
     RECT  67.788 45.451 69.03 45.739 ;
     RECT  2.304 45.599 5.742 45.769 ;
     RECT  6.588 45.697 9.306 45.769 ;
     RECT  18.576 45.265 38.826 45.769 ;
     RECT  0.144 45.643 0.162 45.841 ;
     RECT  67.248 45.739 69.03 45.869 ;
     RECT  0.108 45.841 0.198 45.965 ;
     RECT  0.144 45.965 0.198 46.013 ;
     RECT  63.216 45.455 66.186 46.075 ;
     RECT  67.248 45.869 68.382 46.075 ;
     RECT  61.815 45.491 62.478 46.201 ;
     RECT  63.216 46.075 68.382 46.201 ;
     RECT  2.304 45.769 9.306 46.237 ;
     RECT  61.815 46.201 68.382 46.301 ;
     RECT  60.984 45.725 61.002 46.309 ;
     RECT  61.815 46.301 65.79 46.337 ;
     RECT  58.716 45.491 58.734 46.381 ;
     RECT  59.868 45.599 59.886 46.381 ;
     RECT  60.984 46.309 61.038 46.381 ;
     RECT  61.815 46.337 62.622 46.381 ;
     RECT  2.304 46.237 9.342 46.409 ;
     RECT  60.984 46.381 62.622 46.535 ;
     RECT  40.215 45.427 51.462 46.651 ;
     RECT  60.984 46.535 62.334 46.679 ;
     RECT  66.528 46.301 68.382 46.699 ;
     RECT  0.144 46.013 0.162 46.733 ;
     RECT  18.576 45.769 38.862 46.741 ;
     RECT  39.6 46.651 51.462 46.741 ;
     RECT  59.868 46.381 60.138 46.741 ;
     RECT  60.984 46.679 62.226 46.741 ;
     RECT  66.528 46.699 69.03 46.841 ;
     RECT  58.716 46.381 58.77 46.885 ;
     RECT  2.304 46.409 9.306 46.949 ;
     RECT  59.868 46.741 62.226 46.949 ;
     RECT  2.304 46.949 9.126 46.987 ;
     RECT  10.908 47.083 10.926 47.119 ;
     RECT  63.432 46.337 65.79 47.131 ;
     RECT  66.528 46.841 68.454 47.131 ;
     RECT  2.268 46.987 9.126 47.147 ;
     RECT  60.66 46.949 62.226 47.183 ;
     RECT  10.908 47.119 10.998 47.219 ;
     RECT  60.696 47.183 62.226 47.309 ;
     RECT  58.716 46.885 58.842 47.353 ;
     RECT  58.716 47.353 58.914 47.405 ;
     RECT  63.432 47.131 68.454 47.425 ;
     RECT  10.8 47.353 10.854 47.461 ;
     RECT  61.815 47.309 62.226 47.461 ;
     RECT  63 47.425 68.454 47.461 ;
     RECT  0.18 47.419 0.198 47.467 ;
     RECT  58.716 47.405 58.842 47.489 ;
     RECT  61.815 47.461 68.454 47.597 ;
     RECT  10.764 47.461 10.854 47.615 ;
     RECT  0.108 47.467 0.198 47.687 ;
     RECT  61.815 47.597 66.726 47.696 ;
     RECT  67.788 47.597 68.454 47.755 ;
     RECT  10.8 47.615 10.854 47.759 ;
     RECT  2.304 47.147 9.126 47.803 ;
     RECT  58.716 47.489 58.806 47.849 ;
     RECT  61.815 47.696 63.594 47.849 ;
     RECT  0.144 47.687 0.162 47.885 ;
     RECT  2.304 47.803 9.198 47.929 ;
     RECT  60.696 47.309 61.002 47.929 ;
     RECT  2.304 47.929 9.234 48.029 ;
     RECT  67.788 47.755 69.03 48.029 ;
     RECT  2.304 48.029 9.162 48.191 ;
     RECT  59.868 46.949 59.886 48.199 ;
     RECT  60.66 47.929 61.002 48.199 ;
     RECT  59.868 48.199 61.002 48.235 ;
     RECT  61.815 47.849 63.558 48.235 ;
     RECT  2.304 48.191 9.126 48.263 ;
     RECT  59.868 48.235 63.558 48.299 ;
     RECT  64.332 47.696 66.726 48.361 ;
     RECT  67.788 48.029 68.454 48.361 ;
     RECT  64.332 48.361 68.454 48.365 ;
     RECT  2.304 48.263 6.93 48.389 ;
     RECT  10.8 47.759 10.818 48.389 ;
     RECT  60.804 48.299 63.558 48.389 ;
     RECT  64.332 48.365 67.878 48.461 ;
     RECT  3.888 48.389 6.93 48.533 ;
     RECT  2.304 48.389 2.697 48.569 ;
     RECT  64.332 48.461 65.574 48.569 ;
     RECT  60.912 48.389 63.558 48.619 ;
     RECT  64.332 48.569 65.502 48.619 ;
     RECT  66.708 48.461 67.878 48.653 ;
     RECT  2.34 48.569 2.697 48.659 ;
     RECT  58.788 47.849 58.806 48.703 ;
     RECT  67.284 48.653 67.878 48.749 ;
     RECT  58.788 48.703 58.878 48.763 ;
     RECT  58.716 48.763 58.878 48.797 ;
     RECT  10.764 48.667 10.782 48.839 ;
     RECT  58.716 48.797 58.842 48.929 ;
     RECT  7.776 48.263 9.126 48.973 ;
     RECT  59.868 48.299 60.03 48.989 ;
     RECT  0.108 48.7 0.198 49.009 ;
     RECT  60.912 48.619 65.502 49.037 ;
     RECT  5.04 48.533 6.93 49.045 ;
     RECT  7.776 48.973 9.414 49.045 ;
     RECT  5.04 49.045 9.414 49.081 ;
     RECT  0.108 49.009 0.27 49.085 ;
     RECT  60.912 49.037 63.954 49.109 ;
     RECT  0.108 49.085 0.126 49.133 ;
     RECT  1.116 49.003 1.134 49.181 ;
     RECT  3.888 48.533 4.05 49.243 ;
     RECT  5.04 49.081 9.45 49.271 ;
     RECT  5.04 49.271 8.586 49.279 ;
     RECT  67.752 48.749 67.878 49.279 ;
     RECT  69.012 48.811 69.03 49.279 ;
     RECT  64.728 49.037 65.502 49.307 ;
     RECT  3.852 49.243 4.05 49.351 ;
     RECT  4.932 49.279 8.586 49.351 ;
     RECT  65.88 49.315 65.898 49.351 ;
     RECT  60.012 48.989 60.03 49.435 ;
     RECT  60.912 49.109 62.766 49.435 ;
     RECT  65.88 49.351 66.042 49.441 ;
     RECT  3.852 49.351 8.586 49.469 ;
     RECT  9.324 49.271 9.45 49.469 ;
     RECT  60.012 49.435 62.766 49.469 ;
     RECT  64.728 49.307 64.962 49.469 ;
     RECT  65.88 49.441 66.222 49.469 ;
     RECT  60.012 49.469 60.75 49.475 ;
     RECT  3.852 49.469 3.906 49.477 ;
     RECT  66.024 49.469 66.222 49.505 ;
     RECT  3.708 49.477 3.906 49.517 ;
     RECT  4.752 49.469 5.886 49.517 ;
     RECT  4.752 49.517 5.346 49.577 ;
     RECT  9.432 49.469 9.45 49.577 ;
     RECT  64.728 49.469 64.746 49.577 ;
     RECT  67.752 49.279 69.03 49.579 ;
     RECT  67.248 49.579 69.03 49.675 ;
     RECT  13.215 2.413 13.497 49.711 ;
     RECT  6.768 49.469 8.586 49.739 ;
     RECT  60.012 49.475 60.102 49.747 ;
     RECT  5.328 49.577 5.346 49.757 ;
     RECT  13.104 49.711 13.497 49.757 ;
     RECT  61.776 49.469 62.766 49.775 ;
     RECT  10.8 49.747 10.818 49.783 ;
     RECT  63.504 49.109 63.954 49.783 ;
     RECT  58.716 48.929 58.734 49.855 ;
     RECT  61.815 49.775 62.766 49.891 ;
     RECT  63.504 49.783 63.99 49.891 ;
     RECT  10.764 49.783 10.818 49.919 ;
     RECT  67.212 49.675 69.03 49.963 ;
     RECT  7.272 49.739 8.097 50.009 ;
     RECT  10.764 49.919 10.782 50.009 ;
     RECT  58.716 49.855 58.806 50.009 ;
     RECT  59.796 49.747 60.102 50.093 ;
     RECT  67.176 49.963 69.03 50.093 ;
     RECT  60.084 50.093 60.102 50.153 ;
     RECT  66.132 49.505 66.222 50.161 ;
     RECT  67.176 50.093 67.302 50.161 ;
     RECT  66.132 50.161 67.302 50.251 ;
     RECT  65.664 50.251 67.302 50.285 ;
     RECT  61.815 49.891 64.71 50.387 ;
     RECT  63.18 50.387 64.71 50.549 ;
     RECT  64.656 50.549 64.71 50.593 ;
     RECT  65.664 50.285 67.266 50.593 ;
     RECT  63.18 50.549 63.918 50.657 ;
     RECT  63.18 50.657 63.702 50.669 ;
     RECT  60.948 50.389 60.966 50.827 ;
     RECT  68.292 50.093 69.03 50.957 ;
     RECT  58.716 50.009 58.734 50.971 ;
     RECT  64.656 50.593 67.266 51.019 ;
     RECT  64.656 51.019 67.806 51.089 ;
     RECT  64.656 51.089 67.302 51.149 ;
     RECT  60.948 50.827 61.038 51.163 ;
     RECT  61.815 50.387 62.19 51.163 ;
     RECT  64.656 51.149 67.266 51.269 ;
     RECT  60.948 51.163 62.19 51.293 ;
     RECT  64.656 51.269 65.214 51.293 ;
     RECT  64.656 51.293 64.962 51.359 ;
     RECT  66.276 51.269 66.69 51.359 ;
     RECT  59.868 51.307 59.886 51.395 ;
     RECT  64.764 51.359 64.962 51.395 ;
     RECT  68.976 50.957 69.03 51.395 ;
     RECT  68.976 51.395 68.994 51.431 ;
     RECT  63.216 50.669 63.702 51.475 ;
     RECT  63.108 51.475 63.702 51.511 ;
     RECT  58.716 50.971 58.806 51.539 ;
     RECT  60.984 51.293 62.19 51.629 ;
     RECT  66.6 51.359 66.69 51.629 ;
     RECT  61.632 51.629 62.19 51.637 ;
     RECT  63.108 51.511 63.882 51.637 ;
     RECT  61.632 51.637 63.882 51.701 ;
     RECT  66.672 51.629 66.69 51.701 ;
     RECT  61.632 51.701 62.73 51.737 ;
     RECT  61.815 51.737 62.73 51.773 ;
     RECT  63.864 51.701 63.882 51.773 ;
     RECT  58.716 51.539 58.734 51.809 ;
     RECT  64.944 51.395 64.962 51.809 ;
     RECT  58.68 55.867 58.698 55.949 ;
     RECT  60.228 55.915 60.246 56.191 ;
     RECT  59.976 56.191 60.246 56.219 ;
     RECT  54.72 56.203 54.738 56.333 ;
     RECT  59.976 56.219 59.994 56.333 ;
     RECT  18.576 46.741 51.462 63.625 ;
     RECT  18.54 63.625 51.462 63.787 ;
     RECT  18.504 63.787 51.462 63.835 ;
     RECT  18.468 63.835 51.462 64.327 ;
     RECT  18.18 64.327 51.462 64.859 ;
     RECT  18.18 64.859 51.354 64.867 ;
     RECT  17.748 64.867 51.354 65.245 ;
     RECT  17.676 65.245 51.354 65.399 ;
     RECT  17.676 65.399 51.297 65.515 ;
     RECT  17.46 65.515 51.297 66.389 ;
     RECT  17.46 66.389 27.342 66.515 ;
     RECT  28.152 66.389 51.297 66.551 ;
     RECT  2.415 48.659 2.697 66.707 ;
     RECT  7.815 50.009 8.097 66.707 ;
     RECT  13.215 49.757 13.497 66.707 ;
     RECT  45.615 66.551 51.297 66.707 ;
     RECT  56.415 43.277 56.697 66.707 ;
     RECT  61.815 51.773 62.097 66.707 ;
     RECT  22.428 66.515 27.342 66.749 ;
     RECT  28.152 66.551 44.838 66.749 ;
     RECT  22.5 66.749 26.946 66.785 ;
     RECT  41.76 66.749 44.838 66.797 ;
     RECT  45.615 66.707 51.105 66.845 ;
     RECT  29.052 66.749 35.298 66.857 ;
     RECT  29.052 66.857 35.262 66.893 ;
     RECT  41.904 66.797 44.838 66.893 ;
     RECT  36.072 66.749 41.022 66.929 ;
     RECT  41.904 66.893 44.478 66.941 ;
     RECT  2.415 66.707 2.505 66.977 ;
     RECT  7.815 66.707 7.905 66.977 ;
     RECT  13.215 66.707 13.305 66.977 ;
     RECT  29.052 66.893 29.505 66.977 ;
     RECT  45.615 66.845 49.014 66.977 ;
     RECT  49.752 66.845 51.105 66.977 ;
     RECT  56.415 66.707 56.505 66.977 ;
     RECT  61.815 66.707 61.905 66.977 ;
     RECT  36.072 66.929 38.106 67.229 ;
     RECT  41.904 66.941 44.226 67.229 ;
     RECT  49.752 66.977 50.49 67.229 ;
     RECT  17.46 66.515 21.654 67.277 ;
     RECT  22.5 66.785 24.894 67.277 ;
     RECT  25.956 66.785 26.946 67.277 ;
     RECT  29.052 66.977 29.394 67.277 ;
     RECT  30.456 66.893 35.262 67.277 ;
     RECT  36.072 67.229 36.234 67.277 ;
     RECT  37.008 67.229 38.106 67.277 ;
     RECT  38.844 66.929 41.022 67.277 ;
     RECT  41.904 67.229 43.974 67.277 ;
     RECT  45.936 66.977 49.014 67.277 ;
     RECT  50.472 67.229 50.49 67.277 ;
     RECT  25.956 67.277 25.974 67.325 ;
     RECT  31.104 67.277 31.122 67.325 ;
     RECT  33.516 67.277 34.434 67.325 ;
     RECT  36.072 67.277 36.09 67.325 ;
     RECT  40.356 67.277 40.914 67.325 ;
     RECT  48.348 67.277 49.014 67.325 ;
     RECT  24.444 67.277 24.894 67.373 ;
     RECT  17.46 67.277 18.774 67.853 ;
     RECT  20.916 67.277 21.402 67.853 ;
     RECT  24.876 67.373 24.894 67.853 ;
     RECT  33.516 67.325 34.182 67.853 ;
     RECT  38.088 67.277 38.106 67.853 ;
     RECT  40.356 67.325 40.374 67.853 ;
     RECT  39.132 67.277 39.15 68.381 ;
     RECT  17.568 67.853 18.774 68.429 ;
     RECT  31.896 67.277 32.454 68.429 ;
     RECT  19.872 67.277 19.89 68.717 ;
     RECT  26.892 67.277 26.946 68.827 ;
     RECT  33.516 67.853 33.534 68.827 ;
     RECT  22.896 68.731 22.914 68.861 ;
     RECT  21.384 67.853 21.402 68.875 ;
     RECT  23.868 68.731 23.886 68.875 ;
     RECT  26.892 68.827 27.342 68.875 ;
     RECT  46.188 67.277 46.206 68.875 ;
     RECT  23.868 68.875 24.462 68.909 ;
     RECT  21.384 68.875 22.086 69.005 ;
     RECT  24.444 68.909 24.462 69.005 ;
     RECT  25.812 68.875 25.83 69.005 ;
     RECT  26.748 68.875 27.342 69.005 ;
     RECT  28.836 68.875 29.07 69.005 ;
     RECT  33.264 68.827 33.534 69.005 ;
     RECT  35.856 68.779 35.874 69.005 ;
     RECT  36.648 68.875 36.666 69.005 ;
     RECT  44.424 68.875 44.442 69.005 ;
     RECT  45.576 68.875 46.746 69.005 ;
     RECT  48.996 67.325 49.014 69.005 ;
    LAYER M4 ;
     RECT  0.06 17.712 0.133 49.128 ;
     RECT  0.133 17.712 0.569 49.176 ;
     RECT  0.569 17.808 1.145 49.176 ;
     RECT  1.145 17.808 2.408 49.08 ;
     RECT  2.408 2.148 2.512 66.972 ;
     RECT  2.512 2.418 2.704 66.702 ;
     RECT  2.704 17.76 3.697 49.08 ;
     RECT  3.697 17.76 4.025 49.512 ;
     RECT  4.025 17.856 4.565 49.512 ;
     RECT  4.565 30.912 5.317 49.512 ;
     RECT  4.565 17.856 5.537 29.928 ;
     RECT  5.537 24.672 5.605 29.928 ;
     RECT  5.317 30.912 5.605 49.752 ;
     RECT  5.605 24.672 5.681 49.752 ;
     RECT  5.681 24.672 5.825 44.76 ;
     RECT  5.537 17.856 6.721 23.544 ;
     RECT  5.825 24.672 6.721 29.928 ;
     RECT  6.721 17.856 6.793 29.928 ;
     RECT  5.825 30.912 6.793 44.76 ;
     RECT  6.793 17.856 7.045 44.76 ;
     RECT  5.681 45.792 7.045 49.752 ;
     RECT  7.045 17.856 7.808 49.752 ;
     RECT  7.808 2.148 7.912 66.972 ;
     RECT  7.912 2.418 8.104 66.702 ;
     RECT  8.104 38.256 8.129 39.048 ;
     RECT  8.104 34.08 8.201 37.176 ;
     RECT  8.104 18.288 8.237 23.88 ;
     RECT  8.104 25.2 8.237 28.056 ;
     RECT  8.104 40.992 8.237 43.032 ;
     RECT  8.104 29.328 8.243 32.568 ;
     RECT  8.237 18.288 8.309 21.528 ;
     RECT  8.243 29.328 8.309 30.216 ;
     RECT  8.237 25.44 8.381 28.056 ;
     RECT  8.237 22.512 8.417 23.88 ;
     RECT  8.104 45.456 8.417 45.48 ;
     RECT  8.104 46.512 8.525 48.408 ;
     RECT  8.129 38.256 8.561 38.76 ;
     RECT  8.237 41.376 8.561 43.032 ;
     RECT  8.309 18.288 8.597 18.84 ;
     RECT  8.525 46.56 8.669 48.408 ;
     RECT  8.243 31.488 8.777 32.568 ;
     RECT  8.561 41.376 8.777 42.024 ;
     RECT  8.669 46.56 8.846 47.832 ;
     RECT  8.777 41.904 8.849 42.024 ;
     RECT  8.561 43.008 8.885 43.032 ;
     RECT  8.849 41.904 8.921 41.976 ;
     RECT  8.777 31.488 8.993 31.8 ;
     RECT  8.104 44.4 9.029 44.424 ;
     RECT  8.381 26.256 9.137 28.056 ;
     RECT  8.201 34.08 9.209 34.68 ;
     RECT  8.561 38.448 9.209 38.76 ;
     RECT  8.846 46.608 9.209 47.832 ;
     RECT  8.597 18.288 9.245 18.744 ;
     RECT  8.309 19.872 9.281 21.528 ;
     RECT  8.309 29.328 9.281 30.12 ;
     RECT  8.993 31.776 9.281 31.8 ;
     RECT  9.281 21.216 9.317 21.528 ;
     RECT  9.137 26.256 9.317 27.672 ;
     RECT  9.209 46.608 9.317 46.92 ;
     RECT  8.417 22.512 9.425 23.544 ;
     RECT  9.425 23.28 9.461 23.304 ;
     RECT  8.201 36.048 9.461 37.176 ;
     RECT  9.281 29.328 9.497 29.352 ;
     RECT  9.245 18.288 9.533 18.312 ;
     RECT  9.209 34.656 9.533 34.68 ;
     RECT  9.317 26.256 9.605 26.904 ;
     RECT  9.605 26.256 9.677 26.28 ;
     RECT  9.281 19.872 13.208 19.896 ;
     RECT  9.317 21.216 13.208 21.48 ;
     RECT  9.461 36.288 13.208 36.936 ;
     RECT  9.209 38.736 13.208 38.76 ;
     RECT  8.921 41.904 13.208 41.928 ;
     RECT  8.104 49.728 13.208 49.752 ;
     RECT  13.208 2.148 13.312 66.972 ;
     RECT  13.312 2.418 13.504 66.702 ;
     RECT  17.449 67.824 17.557 67.848 ;
     RECT  17.665 66.72 17.737 66.744 ;
     RECT  17.737 66.72 18.133 66.792 ;
     RECT  18.133 66.528 18.169 66.792 ;
     RECT  18.169 66.096 18.313 66.792 ;
     RECT  17.557 67.824 18.313 68.424 ;
     RECT  13.504 41.904 18.493 41.928 ;
     RECT  18.313 66.096 18.515 68.424 ;
     RECT  18.493 41.904 18.565 41.976 ;
     RECT  13.504 19.872 18.608 19.896 ;
     RECT  13.504 21.216 18.608 21.48 ;
     RECT  13.504 36.288 18.608 36.936 ;
     RECT  13.504 38.736 18.608 38.76 ;
     RECT  18.565 41.904 18.608 42.024 ;
     RECT  13.504 49.728 18.608 49.752 ;
     RECT  18.457 63.84 18.608 63.864 ;
     RECT  18.515 66.096 18.608 67.272 ;
     RECT  18.608 2.148 18.712 67.272 ;
     RECT  18.515 68.4 18.853 68.424 ;
     RECT  18.712 2.418 18.904 67.272 ;
     RECT  18.853 68.4 18.995 68.952 ;
     RECT  18.904 66.528 19.043 67.272 ;
     RECT  18.995 68.688 19.043 68.952 ;
     RECT  18.904 64.224 20.081 65.112 ;
     RECT  19.043 68.688 20.147 68.712 ;
     RECT  18.904 41.904 20.185 43.848 ;
     RECT  20.185 41.904 20.797 44.424 ;
     RECT  19.043 66.72 20.905 67.272 ;
     RECT  20.797 41.904 21.089 45 ;
     RECT  20.905 66.72 21.107 67.848 ;
     RECT  18.904 49.728 21.193 49.752 ;
     RECT  20.081 64.224 21.232 64.728 ;
     RECT  21.193 49.728 21.233 50.184 ;
     RECT  21.107 67.248 21.299 67.848 ;
     RECT  20.389 63.216 21.541 63.24 ;
     RECT  21.232 64.224 21.541 64.776 ;
     RECT  21.329 68.976 21.733 69 ;
     RECT  21.541 63.216 21.836 64.776 ;
     RECT  21.733 68.928 21.836 69 ;
     RECT  18.904 19.872 21.841 19.896 ;
     RECT  21.089 44.976 21.845 45 ;
     RECT  21.836 68.88 21.925 69 ;
     RECT  21.836 63.12 21.953 64.776 ;
     RECT  21.925 68.784 22.163 69 ;
     RECT  22.163 68.784 22.211 68.904 ;
     RECT  21.877 31.344 22.313 31.752 ;
     RECT  22.501 66.096 22.637 66.12 ;
     RECT  21.233 50.064 22.741 50.184 ;
     RECT  22.741 50.064 22.787 50.28 ;
     RECT  21.841 19.872 22.813 20.04 ;
     RECT  22.787 50.16 22.849 50.28 ;
     RECT  22.211 68.784 22.885 68.856 ;
     RECT  21.953 63.12 22.889 64.392 ;
     RECT  22.313 31.344 22.997 31.368 ;
     RECT  22.889 63.216 23.137 64.392 ;
     RECT  21.299 67.248 23.353 67.272 ;
     RECT  22.885 68.736 23.509 68.856 ;
     RECT  22.885 33.024 23.929 33.048 ;
     RECT  23.509 68.736 23.939 68.952 ;
     RECT  23.605 6 24.008 6.024 ;
     RECT  22.813 19.872 24.008 20.136 ;
     RECT  18.904 21.216 24.008 21.48 ;
     RECT  23.137 23.856 24.008 23.88 ;
     RECT  23.929 33.024 24.008 33.336 ;
     RECT  18.904 34.656 24.008 34.68 ;
     RECT  18.904 36.288 24.008 36.936 ;
     RECT  18.904 38.736 24.008 38.76 ;
     RECT  22.525 40.848 24.008 40.872 ;
     RECT  21.089 41.904 24.008 43.32 ;
     RECT  22.849 50.16 24.008 50.424 ;
     RECT  23.137 63.216 24.008 65.016 ;
     RECT  23.353 66.768 24.008 67.272 ;
     RECT  24.008 2.148 24.112 67.272 ;
     RECT  24.112 2.418 24.304 67.272 ;
     RECT  24.304 62.4 24.401 65.016 ;
     RECT  23.939 68.832 24.418 68.952 ;
     RECT  24.304 50.16 24.419 50.424 ;
     RECT  24.304 66.72 24.433 67.272 ;
     RECT  24.401 62.4 24.437 64.92 ;
     RECT  24.304 33.312 24.473 34.68 ;
     RECT  24.418 68.832 24.515 69 ;
     RECT  24.515 68.88 24.563 69 ;
     RECT  24.563 68.88 24.611 68.952 ;
     RECT  24.433 66.72 24.659 67.368 ;
     RECT  24.865 67.824 25.139 67.848 ;
     RECT  24.473 33.888 25.301 34.68 ;
     RECT  24.437 64.896 25.661 64.92 ;
     RECT  24.611 68.928 25.757 68.952 ;
     RECT  25.757 68.928 25.765 69 ;
     RECT  24.659 66.72 25.861 66.744 ;
     RECT  24.304 28.224 26.017 28.248 ;
     RECT  25.861 66.72 26.029 67.32 ;
     RECT  26.017 28.224 26.197 28.296 ;
     RECT  26.029 66.72 26.237 67.272 ;
     RECT  26.197 27.936 26.305 28.296 ;
     RECT  26.237 66.72 26.525 67.224 ;
     RECT  26.305 27.936 26.557 28.44 ;
     RECT  24.437 62.4 26.581 63.864 ;
     RECT  26.557 27.408 26.593 28.44 ;
     RECT  26.581 62.4 26.669 64.392 ;
     RECT  26.525 66.72 26.675 66.936 ;
     RECT  24.304 20.016 26.773 20.04 ;
     RECT  26.593 27.408 26.777 28.728 ;
     RECT  26.773 20.016 26.813 20.136 ;
     RECT  24.419 50.16 26.881 50.184 ;
     RECT  25.765 68.784 26.881 69 ;
     RECT  26.777 27.936 26.885 28.728 ;
     RECT  26.885 28.704 26.921 28.728 ;
     RECT  26.881 50.16 26.921 50.328 ;
     RECT  26.675 66.912 27.059 66.936 ;
     RECT  26.881 68.4 27.353 69 ;
     RECT  27.353 68.4 27.587 68.952 ;
     RECT  26.669 62.4 27.641 63.864 ;
     RECT  27.641 62.4 27.857 63.384 ;
     RECT  27.587 68.4 28.211 68.904 ;
     RECT  28.211 68.784 28.549 68.904 ;
     RECT  28.549 68.784 28.825 68.952 ;
     RECT  28.897 1.104 29.005 1.128 ;
     RECT  27.857 62.496 29.077 63.384 ;
     RECT  29.005 1.104 29.113 1.704 ;
     RECT  29.113 1.104 29.171 1.8 ;
     RECT  29.171 1.68 29.185 1.8 ;
     RECT  28.997 67.248 29.185 67.272 ;
     RECT  29.185 1.68 29.221 2.04 ;
     RECT  29.041 3.12 29.221 3.144 ;
     RECT  24.304 40.848 29.221 40.872 ;
     RECT  24.304 41.904 29.221 43.32 ;
     RECT  28.825 68.784 29.221 69 ;
     RECT  29.221 1.68 29.257 3.144 ;
     RECT  26.773 39.84 29.329 39.864 ;
     RECT  29.257 1.68 29.363 3.912 ;
     RECT  27.673 66.096 29.404 66.12 ;
     RECT  29.185 67.104 29.404 67.272 ;
     RECT  29.363 1.728 29.408 3.912 ;
     RECT  24.304 6 29.408 6.024 ;
     RECT  26.813 20.112 29.408 20.136 ;
     RECT  24.304 21.216 29.408 21.48 ;
     RECT  24.304 23.856 29.408 23.88 ;
     RECT  27.925 30.096 29.408 30.12 ;
     RECT  25.301 34.656 29.408 34.68 ;
     RECT  24.304 36.288 29.408 36.936 ;
     RECT  24.304 38.736 29.408 38.76 ;
     RECT  29.329 39.744 29.408 39.864 ;
     RECT  29.221 40.848 29.408 43.32 ;
     RECT  26.921 50.304 29.408 50.328 ;
     RECT  29.077 62.496 29.408 64.92 ;
     RECT  29.404 66.096 29.408 67.272 ;
     RECT  29.221 68.688 29.555 69 ;
     RECT  29.555 68.832 29.651 69 ;
     RECT  29.408 1.728 29.704 67.272 ;
     RECT  29.653 0.24 29.843 0.36 ;
     RECT  29.704 62.496 29.873 64.488 ;
     RECT  29.873 62.592 29.891 64.488 ;
     RECT  29.891 62.832 30.131 64.488 ;
     RECT  29.651 68.928 30.131 69 ;
     RECT  29.704 1.728 30.305 3.912 ;
     RECT  30.305 3.792 30.377 3.912 ;
     RECT  30.305 1.728 30.593 2.808 ;
     RECT  29.704 5.04 30.733 6.024 ;
     RECT  29.704 65.664 30.733 65.688 ;
     RECT  30.733 65.568 30.757 65.688 ;
     RECT  29.704 67.248 30.757 67.272 ;
     RECT  29.704 36.288 30.769 36.936 ;
     RECT  30.593 1.776 30.773 2.808 ;
     RECT  30.131 63.216 30.773 64.488 ;
     RECT  30.757 65.568 30.773 67.272 ;
     RECT  30.773 2.256 30.845 2.808 ;
     RECT  30.733 4.08 30.851 6.024 ;
     RECT  30.805 26.736 30.877 26.76 ;
     RECT  30.769 36.288 30.881 37.128 ;
     RECT  30.773 65.568 30.899 65.592 ;
     RECT  30.773 66.624 30.899 67.272 ;
     RECT  30.757 68.736 30.899 68.856 ;
     RECT  30.877 26.736 30.953 26.856 ;
     RECT  30.953 26.832 30.989 26.856 ;
     RECT  30.899 68.832 31.043 68.856 ;
     RECT  30.899 66.72 31.045 67.272 ;
     RECT  30.851 4.08 31.133 4.536 ;
     RECT  31.045 66.72 31.142 67.32 ;
     RECT  31.133 4.512 31.205 4.536 ;
     RECT  31.142 66.72 31.283 67.272 ;
     RECT  30.845 2.352 31.777 2.808 ;
     RECT  30.773 63.216 31.813 64.44 ;
     RECT  30.851 5.952 31.849 6.024 ;
     RECT  31.777 2.352 31.957 3 ;
     RECT  29.704 10.368 31.961 10.392 ;
     RECT  31.813 63.12 32.177 64.44 ;
     RECT  31.849 5.76 32.245 6.024 ;
     RECT  32.245 4.944 32.317 6.024 ;
     RECT  32.177 64.416 32.465 64.44 ;
     RECT  31.283 67.152 32.54 67.272 ;
     RECT  31.957 1.584 32.605 3 ;
     RECT  32.54 66.72 32.627 67.272 ;
     RECT  32.569 0.576 32.653 0.6 ;
     RECT  31.885 68.4 32.723 68.424 ;
     RECT  32.677 0.096 32.789 0.552 ;
     RECT  32.605 1.584 32.819 3.096 ;
     RECT  32.317 4.944 32.821 6.744 ;
     RECT  30.881 36.288 32.825 36.936 ;
     RECT  29.704 38.736 32.965 38.76 ;
     RECT  29.704 39.744 32.965 43.32 ;
     RECT  32.819 1.632 33.037 3.096 ;
     RECT  33.037 1.632 33.109 3.72 ;
     RECT  32.821 4.944 33.109 7.032 ;
     RECT  32.965 38.736 33.145 43.32 ;
     RECT  33.109 1.632 33.203 7.032 ;
     RECT  33.157 68.832 33.253 68.952 ;
     RECT  33.253 68.832 33.293 69 ;
     RECT  32.789 0.48 33.491 0.552 ;
     RECT  32.177 63.12 33.493 63.24 ;
     RECT  33.293 68.928 33.539 69 ;
     RECT  33.493 62.832 33.605 63.24 ;
     RECT  33.203 1.728 33.613 7.032 ;
     RECT  32.627 67.008 33.649 67.272 ;
     RECT  29.704 34.656 33.689 34.68 ;
     RECT  32.965 65.52 33.833 65.544 ;
     RECT  33.539 68.976 33.875 69 ;
     RECT  33.649 66.72 33.901 67.272 ;
     RECT  33.613 1.728 33.932 7.464 ;
     RECT  33.932 1.728 33.973 7.944 ;
     RECT  31.993 9.696 33.973 9.72 ;
     RECT  33.605 62.832 34.045 63.816 ;
     RECT  34.045 62.832 34.128 64.392 ;
     RECT  33.901 66.624 34.153 67.272 ;
     RECT  29.704 50.16 34.213 50.184 ;
     RECT  34.128 62.832 34.213 64.44 ;
     RECT  34.153 66.624 34.259 67.848 ;
     RECT  34.259 66.624 34.489 67.32 ;
     RECT  34.501 68.928 34.691 68.952 ;
     RECT  29.704 20.016 34.693 20.04 ;
     RECT  32.825 36.288 34.693 36.312 ;
     RECT  33.491 0.528 34.765 0.552 ;
     RECT  33.973 1.728 34.808 9.72 ;
     RECT  34.693 19.824 34.808 20.04 ;
     RECT  29.704 21.216 34.808 21.48 ;
     RECT  29.704 23.856 34.808 23.88 ;
     RECT  34.268 34.608 34.808 34.632 ;
     RECT  34.693 35.808 34.808 36.312 ;
     RECT  33.145 38.688 34.808 43.32 ;
     RECT  34.213 50.064 34.808 50.184 ;
     RECT  34.213 62.544 34.808 64.44 ;
     RECT  34.489 66.624 34.808 67.272 ;
     RECT  34.808 1.728 35.104 67.272 ;
     RECT  35.104 67.104 35.123 67.272 ;
     RECT  34.765 0.096 35.173 0.552 ;
     RECT  35.104 1.728 35.173 7.56 ;
     RECT  35.104 35.808 35.273 36.648 ;
     RECT  35.173 0.096 35.315 7.56 ;
     RECT  35.315 1.152 35.489 7.56 ;
     RECT  35.489 1.152 35.507 1.272 ;
     RECT  35.507 1.152 35.651 1.176 ;
     RECT  35.104 62.544 35.669 64.824 ;
     RECT  35.273 36.048 35.777 36.648 ;
     RECT  35.315 0.096 35.795 0.12 ;
     RECT  35.749 68.976 35.797 69 ;
     RECT  35.797 68.784 35.885 69 ;
     RECT  35.669 63.216 35.987 64.824 ;
     RECT  35.123 67.152 36.017 67.272 ;
     RECT  35.489 2.304 36.085 7.56 ;
     RECT  35.104 8.784 36.085 8.856 ;
     RECT  36.017 67.152 36.134 67.32 ;
     RECT  35.777 36.24 36.137 36.648 ;
     RECT  35.987 63.216 36.137 63.816 ;
     RECT  36.134 67.152 36.277 67.272 ;
     RECT  36.137 63.216 36.419 63.672 ;
     RECT  35.987 64.8 36.457 64.824 ;
     RECT  36.137 36.288 36.493 36.648 ;
     RECT  36.277 66.768 36.673 67.272 ;
     RECT  36.085 2.304 36.677 8.856 ;
     RECT  35.885 68.88 36.71 69 ;
     RECT  36.677 2.304 36.853 7.416 ;
     RECT  36.71 68.928 36.899 68.952 ;
     RECT  36.853 2.256 37.093 7.416 ;
     RECT  37.093 1.728 37.18 7.416 ;
     RECT  36.677 8.544 37.217 8.856 ;
     RECT  37.237 0.144 37.285 0.168 ;
     RECT  36.493 36.288 37.289 36.936 ;
     RECT  36.457 64.8 37.289 65.16 ;
     RECT  36.673 66.72 37.321 67.272 ;
     RECT  37.18 1.68 37.331 7.416 ;
     RECT  36.419 63.216 37.381 63.288 ;
     RECT  37.285 0.144 37.426 0.408 ;
     RECT  37.426 0.096 37.427 0.408 ;
     RECT  37.331 1.92 37.427 7.416 ;
     RECT  37.427 0.096 37.549 0.312 ;
     RECT  37.427 2.112 37.619 7.416 ;
     RECT  37.549 0.144 37.649 0.312 ;
     RECT  37.649 0.144 37.66 0.168 ;
     RECT  37.321 66.672 37.685 67.272 ;
     RECT  37.619 2.448 37.753 7.416 ;
     RECT  37.217 8.544 37.753 8.808 ;
     RECT  37.685 67.056 38.077 67.272 ;
     RECT  38.077 67.056 38.099 67.848 ;
     RECT  37.381 63.12 38.101 63.288 ;
     RECT  37.289 64.8 38.101 64.824 ;
     RECT  38.101 63.12 38.147 64.824 ;
     RECT  38.099 67.2 38.245 67.848 ;
     RECT  37.753 2.448 38.369 8.808 ;
     RECT  38.369 2.544 38.477 8.808 ;
     RECT  38.245 67.2 38.483 68.808 ;
     RECT  38.483 68.352 38.533 68.808 ;
     RECT  35.104 50.064 38.545 50.088 ;
     RECT  38.147 63.12 38.677 64.056 ;
     RECT  38.533 68.352 38.723 68.904 ;
     RECT  38.545 49.536 38.801 50.088 ;
     RECT  38.677 62.832 39.077 64.056 ;
     RECT  39.077 62.736 39.161 64.056 ;
     RECT  38.723 68.352 39.161 68.376 ;
     RECT  38.483 67.2 39.356 67.272 ;
     RECT  39.373 1.104 39.539 1.128 ;
     RECT  39.356 66.72 39.841 67.272 ;
     RECT  38.477 2.544 39.877 7.992 ;
     RECT  39.841 66.48 39.877 67.272 ;
     RECT  39.877 2.352 39.985 8.76 ;
     RECT  39.925 0.192 40.021 0.216 ;
     RECT  39.985 1.68 40.115 8.76 ;
     RECT  40.115 1.728 40.208 8.76 ;
     RECT  35.104 19.824 40.208 19.848 ;
     RECT  35.104 21.216 40.208 21.48 ;
     RECT  35.104 23.856 40.208 23.88 ;
     RECT  37.289 36.624 40.208 36.936 ;
     RECT  35.104 39.744 40.208 43.32 ;
     RECT  38.801 50.064 40.208 50.088 ;
     RECT  39.161 62.832 40.208 64.056 ;
     RECT  39.877 65.52 40.208 67.272 ;
     RECT  40.208 1.728 40.345 67.272 ;
     RECT  40.345 1.728 40.504 67.848 ;
     RECT  40.504 66.48 40.565 67.848 ;
     RECT  40.565 67.248 40.595 67.848 ;
     RECT  40.453 68.928 40.643 68.952 ;
     RECT  40.021 0.144 40.835 0.216 ;
     RECT  40.504 62.304 41.141 64.104 ;
     RECT  40.595 67.248 41.171 67.32 ;
     RECT  41.141 62.592 41.177 64.104 ;
     RECT  41.171 67.248 41.749 67.272 ;
     RECT  41.605 68.928 41.797 68.952 ;
     RECT  41.749 66.768 41.857 67.272 ;
     RECT  40.835 0.144 41.929 0.168 ;
     RECT  41.929 0.048 42.065 0.168 ;
     RECT  40.504 1.728 42.065 8.472 ;
     RECT  41.177 62.832 42.325 64.104 ;
     RECT  42.325 62.448 42.371 64.104 ;
     RECT  42.065 0.048 42.401 8.472 ;
     RECT  41.797 68.88 42.469 68.952 ;
     RECT  42.469 68.832 42.563 68.952 ;
     RECT  42.401 0.048 42.653 8.184 ;
     RECT  42.563 68.832 42.659 68.856 ;
     RECT  42.653 0.048 43.373 7.368 ;
     RECT  43.373 0.048 43.445 7.272 ;
     RECT  42.371 62.448 43.525 63.24 ;
     RECT  40.504 39.744 43.657 43.32 ;
     RECT  43.525 62.448 43.669 63.288 ;
     RECT  42.757 64.32 43.669 64.584 ;
     RECT  43.669 62.448 43.837 64.584 ;
     RECT  43.657 39.744 43.981 43.512 ;
     RECT  41.857 66.72 43.985 67.272 ;
     RECT  43.985 66.72 44.237 67.224 ;
     RECT  44.101 68.736 44.245 68.76 ;
     RECT  44.245 68.736 44.293 68.904 ;
     RECT  43.445 0.048 44.449 7.08 ;
     RECT  44.449 46.032 44.521 46.056 ;
     RECT  44.237 66.72 44.773 66.936 ;
     RECT  44.521 46.032 45.061 46.104 ;
     RECT  44.293 68.736 45.061 69 ;
     RECT  40.504 19.824 45.205 19.848 ;
     RECT  44.449 0.048 45.608 7.416 ;
     RECT  45.205 19.824 45.608 20.136 ;
     RECT  40.504 21.216 45.608 21.48 ;
     RECT  40.504 23.856 45.608 23.88 ;
     RECT  40.504 36.624 45.608 36.936 ;
     RECT  43.981 39.744 45.608 43.848 ;
     RECT  45.061 46.032 45.608 46.584 ;
     RECT  40.504 50.064 45.608 50.088 ;
     RECT  43.837 62.448 45.608 64.776 ;
     RECT  44.773 65.952 45.608 66.936 ;
     RECT  45.061 68.688 45.637 69 ;
     RECT  45.637 68.64 45.733 69 ;
     RECT  45.608 0.048 45.829 66.972 ;
     RECT  45.829 0.048 45.904 67.272 ;
     RECT  45.733 68.544 46.067 69 ;
     RECT  45.904 7.2 46.109 7.224 ;
     RECT  46.067 68.736 46.115 69 ;
     RECT  46.115 68.832 46.163 69 ;
     RECT  45.904 0.048 46.397 5.88 ;
     RECT  46.397 0.048 46.505 5.304 ;
     RECT  45.904 46.512 46.757 46.776 ;
     RECT  46.163 68.88 46.79 69 ;
     RECT  46.505 0.048 46.901 4.488 ;
     RECT  46.79 68.928 46.979 68.952 ;
     RECT  46.901 0.048 47.045 4.44 ;
     RECT  47.045 0.048 47.117 4.296 ;
     RECT  45.904 21.216 47.132 21.48 ;
     RECT  45.904 66.432 47.173 67.272 ;
     RECT  47.117 2.064 47.189 4.296 ;
     RECT  47.132 21.216 47.219 21.576 ;
     RECT  47.219 21.216 47.297 21.48 ;
     RECT  45.904 62.544 47.651 64.44 ;
     RECT  47.189 2.064 47.765 4.152 ;
     RECT  47.117 0.048 47.909 0.984 ;
     RECT  47.909 0.192 47.945 0.984 ;
     RECT  47.765 2.352 48.089 4.152 ;
     RECT  48.089 2.352 48.197 3.816 ;
     RECT  45.904 50.064 48.233 50.088 ;
     RECT  47.173 66.144 48.293 67.272 ;
     RECT  47.651 62.544 48.371 62.568 ;
     RECT  47.651 63.744 48.385 64.44 ;
     RECT  48.293 66.144 48.41 67.32 ;
     RECT  48.197 3.792 48.413 3.816 ;
     RECT  47.945 0.816 48.485 0.984 ;
     RECT  48.385 63.744 48.593 63.816 ;
     RECT  47.297 21.456 48.629 21.48 ;
     RECT  45.904 19.824 48.841 20.04 ;
     RECT  48.197 2.352 48.845 2.376 ;
     RECT  48.841 19.824 48.881 20.328 ;
     RECT  48.485 0.96 48.953 0.984 ;
     RECT  48.956 68.976 49.043 69 ;
     RECT  45.904 23.856 49.093 23.88 ;
     RECT  49.093 23.184 49.165 23.88 ;
     RECT  49.165 23.088 49.489 23.88 ;
     RECT  48.41 66.144 49.961 67.272 ;
     RECT  49.489 23.088 50.033 23.928 ;
     RECT  49.961 66.768 50.033 67.272 ;
     RECT  50.101 65.568 50.485 65.592 ;
     RECT  50.033 67.248 50.501 67.272 ;
     RECT  48.881 20.304 51.008 20.328 ;
     RECT  49.021 22.032 51.008 22.056 ;
     RECT  50.033 23.184 51.008 23.928 ;
     RECT  45.904 36.624 51.008 36.936 ;
     RECT  45.904 39.744 51.008 43.32 ;
     RECT  46.757 46.512 51.008 46.536 ;
     RECT  48.325 50.016 51.008 50.04 ;
     RECT  50.389 56.304 51.008 56.328 ;
     RECT  48.593 63.744 51.008 63.768 ;
     RECT  50.485 64.848 51.008 65.592 ;
     RECT  51.008 2.148 51.112 66.972 ;
     RECT  51.112 2.418 51.304 66.702 ;
     RECT  51.304 23.568 51.401 23.88 ;
     RECT  51.304 56.208 54.709 56.232 ;
     RECT  54.709 56.208 54.749 56.328 ;
     RECT  51.304 22.176 56.221 22.2 ;
     RECT  51.304 20.304 56.408 20.328 ;
     RECT  56.221 22.176 56.408 22.248 ;
     RECT  51.401 23.856 56.408 23.88 ;
     RECT  51.304 36.624 56.408 36.936 ;
     RECT  51.304 39.744 56.408 43.32 ;
     RECT  51.304 46.512 56.408 46.536 ;
     RECT  51.304 50.016 56.408 50.04 ;
     RECT  54.749 56.304 56.408 56.328 ;
     RECT  56.408 2.148 56.512 66.972 ;
     RECT  56.512 2.418 56.704 66.702 ;
     RECT  56.704 56.304 58.625 56.328 ;
     RECT  56.704 50.016 58.645 50.04 ;
     RECT  58.645 49.824 58.691 50.04 ;
     RECT  56.704 46.512 58.705 46.536 ;
     RECT  58.625 55.872 58.709 56.328 ;
     RECT  56.704 36.624 58.741 36.936 ;
     RECT  56.704 39.744 58.745 43.32 ;
     RECT  58.741 36.576 58.781 36.936 ;
     RECT  58.705 44.688 58.817 44.712 ;
     RECT  58.705 48.768 58.889 48.792 ;
     RECT  58.705 46.512 58.925 47.4 ;
     RECT  58.745 39.744 59.713 43.272 ;
     RECT  59.713 30.336 59.785 30.36 ;
     RECT  58.781 36.576 59.785 36.648 ;
     RECT  59.713 39.744 59.785 44.088 ;
     RECT  58.691 49.824 59.785 49.848 ;
     RECT  59.785 49.824 59.845 50.088 ;
     RECT  59.813 51.312 59.845 51.336 ;
     RECT  56.704 22.176 59.857 22.2 ;
     RECT  56.704 23.856 59.857 23.88 ;
     RECT  59.749 24.912 59.857 24.936 ;
     RECT  59.785 35.808 59.893 36.696 ;
     RECT  59.785 30.192 59.897 30.36 ;
     RECT  59.845 48.96 59.897 51.336 ;
     RECT  59.897 48.96 59.932 50.424 ;
     RECT  58.709 56.304 60.005 56.328 ;
     RECT  59.785 34.272 60.037 34.296 ;
     RECT  59.857 23.856 60.181 24.936 ;
     RECT  59.893 35.472 60.325 36.696 ;
     RECT  60.037 33.552 60.401 34.296 ;
     RECT  60.001 31.536 60.437 32.424 ;
     RECT  59.897 30.336 60.541 30.36 ;
     RECT  60.181 23.856 60.545 26.808 ;
     RECT  56.704 20.304 60.649 20.328 ;
     RECT  59.857 28.944 60.649 28.968 ;
     RECT  60.437 32.4 60.685 32.424 ;
     RECT  60.649 20.304 60.689 20.424 ;
     RECT  59.857 22.176 60.721 22.824 ;
     RECT  60.545 23.856 60.721 25.704 ;
     RECT  60.685 32.4 60.757 32.472 ;
     RECT  60.401 33.552 60.757 34.104 ;
     RECT  58.925 46.512 60.757 46.776 ;
     RECT  59.932 49.44 60.803 50.424 ;
     RECT  60.803 50.4 60.937 50.424 ;
     RECT  60.325 35.472 60.973 36.936 ;
     RECT  60.721 22.176 61.045 25.704 ;
     RECT  59.785 39.744 61.045 44.472 ;
     RECT  60.649 27.984 61.225 28.968 ;
     RECT  60.541 30.336 61.225 30.84 ;
     RECT  60.937 50.4 61.436 51.288 ;
     RECT  60.973 35.472 61.549 36.984 ;
     RECT  61.225 27.984 61.585 30.84 ;
     RECT  60.689 20.4 61.808 20.424 ;
     RECT  61.045 21.744 61.808 25.704 ;
     RECT  60.545 26.784 61.808 26.808 ;
     RECT  61.585 27.984 61.808 31.128 ;
     RECT  60.757 32.4 61.808 34.104 ;
     RECT  61.549 35.472 61.808 37.08 ;
     RECT  61.477 38.736 61.808 38.76 ;
     RECT  61.045 39.744 61.808 44.664 ;
     RECT  60.757 46.512 61.808 47.16 ;
     RECT  60.973 48.48 61.808 48.936 ;
     RECT  61.436 50.4 61.808 51.528 ;
     RECT  60.217 55.92 61.808 55.944 ;
     RECT  61.808 2.148 61.912 66.972 ;
     RECT  61.912 2.418 62.104 66.702 ;
     RECT  62.104 36.528 62.309 45.192 ;
     RECT  62.104 46.368 62.849 49.08 ;
     RECT  62.104 21.744 63.065 27.384 ;
     RECT  62.104 28.416 63.169 33.864 ;
     RECT  62.309 36.528 63.281 44.28 ;
     RECT  62.104 35.424 63.317 35.448 ;
     RECT  63.281 39.744 63.349 44.28 ;
     RECT  63.065 21.744 63.385 26.904 ;
     RECT  63.169 28.416 63.389 34.248 ;
     RECT  63.389 30.864 63.457 34.248 ;
     RECT  63.281 36.528 63.493 38.76 ;
     RECT  63.385 21.408 63.497 26.904 ;
     RECT  63.493 36.432 63.497 38.76 ;
     RECT  62.104 50.208 63.497 51.192 ;
     RECT  62.104 20.016 63.529 20.424 ;
     RECT  63.457 30.864 63.533 34.632 ;
     RECT  63.529 20.016 63.605 20.76 ;
     RECT  63.497 21.744 63.605 26.904 ;
     RECT  63.605 20.064 63.635 20.76 ;
     RECT  63.605 22.176 63.635 26.904 ;
     RECT  63.635 22.176 63.641 24.936 ;
     RECT  63.533 30.864 63.713 33.336 ;
     RECT  62.849 46.368 63.741 48.504 ;
     RECT  63.713 31.152 63.785 33.096 ;
     RECT  63.741 47.664 63.817 48.504 ;
     RECT  63.785 31.344 63.857 32.856 ;
     RECT  63.817 47.664 63.857 48.648 ;
     RECT  63.389 28.416 63.893 29.592 ;
     RECT  63.497 50.208 63.893 50.232 ;
     RECT  63.497 36.432 64.285 38.184 ;
     RECT  63.893 29.04 64.393 29.592 ;
     RECT  63.349 39.744 64.429 44.616 ;
     RECT  63.635 20.064 64.469 20.088 ;
     RECT  63.857 47.808 64.469 48.648 ;
     RECT  63.741 46.368 64.577 46.536 ;
     RECT  63.857 31.344 64.613 31.368 ;
     RECT  63.641 22.176 64.717 24.552 ;
     RECT  63.857 32.448 64.721 32.856 ;
     RECT  63.533 34.608 64.753 34.632 ;
     RECT  63.673 51.36 64.753 51.384 ;
     RECT  64.577 46.512 64.757 46.536 ;
     RECT  64.717 22.176 64.793 24.696 ;
     RECT  64.357 28.032 64.793 28.056 ;
     RECT  64.393 29.04 64.793 29.832 ;
     RECT  64.753 51.264 64.793 51.384 ;
     RECT  63.635 26.352 64.897 26.904 ;
     RECT  64.285 35.808 64.901 38.184 ;
     RECT  64.753 34.416 64.937 34.632 ;
     RECT  64.721 32.448 64.973 32.472 ;
     RECT  64.429 39.744 64.973 44.664 ;
     RECT  64.469 47.808 64.973 48.504 ;
     RECT  64.901 35.808 65.009 36.648 ;
     RECT  64.973 40.08 65.009 40.872 ;
     RECT  64.793 22.176 65.077 23.112 ;
     RECT  65.009 35.808 65.081 36.6 ;
     RECT  64.973 42 65.081 42.888 ;
     RECT  64.793 29.808 65.117 29.832 ;
     RECT  64.897 26.352 65.153 27.336 ;
     RECT  65.077 21.552 65.189 23.112 ;
     RECT  64.937 34.416 65.189 34.44 ;
     RECT  65.189 21.552 65.225 22.2 ;
     RECT  64.793 51.264 65.225 51.288 ;
     RECT  64.901 38.16 65.477 38.184 ;
     RECT  64.793 24.096 65.513 24.696 ;
     RECT  65.081 35.808 65.513 35.832 ;
     RECT  64.973 43.92 65.513 44.664 ;
     RECT  65.513 43.92 65.621 43.944 ;
     RECT  64.973 48.432 65.693 48.456 ;
     RECT  65.513 24.672 65.801 24.696 ;
     RECT  65.153 26.352 65.909 26.568 ;
     RECT  65.581 32.016 66.049 32.04 ;
     RECT  65.909 26.544 66.121 26.568 ;
     RECT  65.473 28.464 66.121 28.488 ;
     RECT  65.941 47.904 66.373 47.928 ;
     RECT  66.229 34.944 66.481 34.968 ;
     RECT  66.121 26.544 66.553 28.488 ;
     RECT  66.553 26.544 66.697 29.112 ;
     RECT  65.545 30.816 66.697 30.84 ;
     RECT  66.481 34.224 66.697 34.968 ;
     RECT  65.009 40.08 66.697 40.104 ;
     RECT  65.081 42.048 66.697 42.888 ;
     RECT  66.373 47.136 66.697 47.928 ;
     RECT  66.121 44.976 66.733 45.192 ;
     RECT  66.697 26.544 66.737 30.84 ;
     RECT  66.085 50.352 67.165 50.376 ;
     RECT  67.165 49.968 67.201 50.376 ;
     RECT  65.225 21.552 67.237 21.96 ;
     RECT  66.737 26.64 67.237 30.84 ;
     RECT  66.049 32.016 67.237 32.904 ;
     RECT  66.697 34.224 67.237 35.112 ;
     RECT  66.697 38.064 67.237 38.088 ;
     RECT  66.733 44.976 67.237 46.152 ;
     RECT  66.697 47.136 67.237 48.648 ;
     RECT  67.201 49.68 67.237 50.376 ;
     RECT  67.237 21.36 67.273 21.96 ;
     RECT  67.237 23.568 67.273 23.976 ;
     RECT  67.237 26.64 67.273 30.936 ;
     RECT  67.237 32.016 67.273 38.088 ;
     RECT  66.697 40.08 67.273 40.584 ;
     RECT  66.697 41.904 67.273 43.176 ;
     RECT  67.237 44.208 67.273 50.856 ;
     RECT  67.273 21.36 67.705 24.168 ;
     RECT  67.705 20.784 67.741 24.168 ;
     RECT  67.237 25.392 67.741 25.416 ;
     RECT  67.273 26.64 67.741 38.088 ;
     RECT  67.273 39.12 67.741 51.144 ;
     RECT  67.741 20.688 67.777 51.144 ;
     RECT  67.777 19.92 68.965 51.144 ;
     RECT  68.965 19.92 69.084 51.336 ;
    LAYER M5 ;
     RECT  29.136 0.016 30.6 1.139 ;
     RECT  29.232 1.139 30.6 1.763 ;
     RECT  32.208 0.016 45.192 1.763 ;
     RECT  29.4 1.763 30.6 1.859 ;
     RECT  32.496 1.763 45.192 2.137 ;
     RECT  2.4 2.137 2.52 2.151 ;
     RECT  7.8 2.137 7.92 2.151 ;
     RECT  13.2 2.137 13.32 2.151 ;
     RECT  18.6 2.137 18.72 2.151 ;
     RECT  24 2.137 24.12 2.151 ;
     RECT  32.496 2.137 45.72 2.151 ;
     RECT  51 2.137 51.12 2.151 ;
     RECT  56.4 2.137 56.52 2.151 ;
     RECT  61.8 2.137 61.92 2.151 ;
     RECT  29.4 1.859 30.216 2.291 ;
     RECT  29.4 2.291 29.832 2.915 ;
     RECT  32.496 2.151 45.912 2.915 ;
     RECT  33.36 2.915 45.912 4.019 ;
     RECT  33.552 4.019 45.912 5.459 ;
     RECT  33.552 5.459 43.272 5.605 ;
     RECT  32.832 5.605 43.272 5.939 ;
     RECT  30.816 4.501 30.84 5.987 ;
     RECT  33.552 5.939 43.272 5.987 ;
     RECT  24 2.151 24.312 5.989 ;
     RECT  39.168 5.987 43.272 6.371 ;
     RECT  33.552 5.987 38.184 6.563 ;
     RECT  44.4 5.459 45.912 6.611 ;
     RECT  43.248 6.371 43.272 6.803 ;
     RECT  39.168 6.371 42.168 6.899 ;
     RECT  33.984 6.563 38.184 6.947 ;
     RECT  39.168 6.899 41.976 7.475 ;
     RECT  33.984 6.947 36.456 7.571 ;
     RECT  39.792 7.475 40.872 7.619 ;
     RECT  39.792 7.619 40.512 7.763 ;
     RECT  41.952 7.475 41.976 8.195 ;
     RECT  37.44 6.947 38.184 8.579 ;
     RECT  39.888 7.763 40.512 8.771 ;
     RECT  36.096 7.571 36.456 8.819 ;
     RECT  38.16 8.579 38.184 8.819 ;
     RECT  33.984 7.571 35.112 8.867 ;
     RECT  36.096 8.819 36.12 8.867 ;
     RECT  34.176 8.867 35.112 9.731 ;
     RECT  29.4 2.915 29.712 10.357 ;
     RECT  7.8 2.151 8.112 17.845 ;
     RECT  6.816 17.845 8.112 18.707 ;
     RECT  34.8 9.731 35.112 19.813 ;
     RECT  7.8 18.707 8.112 19.861 ;
     RECT  23.616 5.989 24.312 20.003 ;
     RECT  34.704 19.813 35.112 20.005 ;
     RECT  45.216 6.611 45.912 20.147 ;
     RECT  7.44 19.861 8.112 20.149 ;
     RECT  6.912 20.149 8.112 20.819 ;
     RECT  0.192 22.357 0.216 22.547 ;
     RECT  2.4 2.151 2.712 23.125 ;
     RECT  7.8 20.819 8.112 23.269 ;
     RECT  2.304 23.125 2.712 23.315 ;
     RECT  6.864 23.269 8.112 23.459 ;
     RECT  61.8 2.151 62.112 23.893 ;
     RECT  2.4 23.315 2.712 24.373 ;
     RECT  4.944 20.197 4.968 24.373 ;
     RECT  4.8 24.373 4.968 24.419 ;
     RECT  2.304 24.373 2.712 24.515 ;
     RECT  60.864 23.893 62.112 25.237 ;
     RECT  63.6 20.389 63.624 25.237 ;
     RECT  60.864 25.237 63.624 25.667 ;
     RECT  60.864 25.667 62.112 25.715 ;
     RECT  63.36 25.667 63.624 25.715 ;
     RECT  7.8 23.459 8.112 26.725 ;
     RECT  2.4 24.515 2.712 27.157 ;
     RECT  2.304 27.157 2.712 27.347 ;
     RECT  0.144 27.637 0.168 27.923 ;
     RECT  2.4 27.347 2.712 28.213 ;
     RECT  2.4 28.213 2.808 28.451 ;
     RECT  63.36 25.715 63.384 28.451 ;
     RECT  6.624 27.301 6.648 28.499 ;
     RECT  7.68 26.725 8.112 30.181 ;
     RECT  7.68 30.181 8.232 30.851 ;
     RECT  7.8 30.851 8.232 30.995 ;
     RECT  0.144 30.853 0.168 31.043 ;
     RECT  2.4 28.451 2.712 31.333 ;
     RECT  2.304 31.333 2.712 31.859 ;
     RECT  4.8 24.419 4.824 31.955 ;
     RECT  60.768 28.453 60.792 32.771 ;
     RECT  0.144 33.973 0.168 34.163 ;
     RECT  2.4 31.859 2.712 34.453 ;
     RECT  2.304 34.453 2.712 34.643 ;
     RECT  18.6 2.151 18.912 34.645 ;
     RECT  6.096 36.373 6.12 37.571 ;
     RECT  7.8 30.995 8.112 39.829 ;
     RECT  63.504 36.421 63.528 39.923 ;
     RECT  7.248 39.829 8.112 40.595 ;
     RECT  58.704 41.749 58.728 41.987 ;
     RECT  2.4 34.643 2.712 42.997 ;
     RECT  2.304 42.997 2.712 43.187 ;
     RECT  63.456 40.165 63.48 43.477 ;
     RECT  63.456 43.477 63.672 43.523 ;
     RECT  63.648 43.523 63.672 47.171 ;
     RECT  4.176 37.381 4.2 47.315 ;
     RECT  2.4 43.187 2.712 48.469 ;
     RECT  2.304 48.469 2.712 48.659 ;
     RECT  60.768 47.125 60.792 48.949 ;
     RECT  0.144 48.997 0.168 49.187 ;
     RECT  5.664 47.269 5.688 49.763 ;
     RECT  59.856 48.949 60.792 49.859 ;
     RECT  34.32 20.005 35.112 50.053 ;
     RECT  34.224 50.053 35.112 50.195 ;
     RECT  22.752 50.053 22.776 50.291 ;
     RECT  24 20.003 24.312 50.389 ;
     RECT  59.856 49.859 59.88 51.347 ;
     RECT  61.8 25.715 62.112 51.493 ;
     RECT  58.656 49.813 58.68 55.907 ;
     RECT  61.488 51.493 62.112 55.955 ;
     RECT  51 2.151 51.312 56.293 ;
     RECT  40.2 8.771 40.512 62.293 ;
     RECT  34.8 50.195 35.112 62.533 ;
     RECT  45.6 20.147 45.912 62.677 ;
     RECT  29.4 10.357 30.696 62.773 ;
     RECT  27.312 62.389 27.336 62.821 ;
     RECT  28.56 62.773 30.696 62.821 ;
     RECT  34.224 62.533 35.112 62.821 ;
     RECT  39.12 62.725 39.144 62.821 ;
     RECT  40.2 62.293 41.016 62.821 ;
     RECT  42.336 62.437 42.36 62.821 ;
     RECT  45.6 62.677 46.152 63.013 ;
     RECT  27.312 62.821 30.696 63.061 ;
     RECT  25.824 63.013 25.848 63.109 ;
     RECT  27.264 63.061 30.696 63.109 ;
     RECT  33.504 62.821 35.112 63.109 ;
     RECT  38.688 62.821 42.36 63.109 ;
     RECT  45.168 63.013 46.152 63.109 ;
     RECT  25.584 63.109 25.848 63.157 ;
     RECT  33.024 63.109 35.112 63.157 ;
     RECT  37.392 63.109 37.416 63.157 ;
     RECT  38.544 63.109 42.648 63.157 ;
     RECT  18.6 34.645 19.752 63.205 ;
     RECT  21.888 63.109 22.728 63.205 ;
     RECT  24 50.389 24.408 63.205 ;
     RECT  25.584 63.157 25.944 63.205 ;
     RECT  26.976 63.109 30.696 63.205 ;
     RECT  31.824 63.109 31.848 63.205 ;
     RECT  32.88 63.157 35.112 63.205 ;
     RECT  37.392 63.157 42.648 63.205 ;
     RECT  44.784 63.109 46.152 63.205 ;
     RECT  47.184 21.541 47.208 63.205 ;
     RECT  48.336 50.005 48.36 63.205 ;
     RECT  21.456 63.205 24.456 63.253 ;
     RECT  25.44 63.205 35.208 63.253 ;
     RECT  36.336 63.205 43.272 63.253 ;
     RECT  44.256 63.205 48.36 63.253 ;
     RECT  50.4 56.293 51.312 63.779 ;
     RECT  21.456 63.253 48.36 63.781 ;
     RECT  50.496 63.779 51.312 64.883 ;
     RECT  18.6 63.205 20.424 66.085 ;
     RECT  18.384 66.085 20.424 66.709 ;
     RECT  21.456 63.781 48.408 66.709 ;
     RECT  17.808 66.709 48.84 66.757 ;
     RECT  17.808 66.757 48.936 66.805 ;
     RECT  2.4 48.659 2.712 66.969 ;
     RECT  7.8 40.595 8.112 66.969 ;
     RECT  13.2 2.151 13.512 66.969 ;
     RECT  51 64.883 51.312 66.969 ;
     RECT  56.4 2.151 56.712 66.969 ;
     RECT  61.8 55.955 62.112 66.969 ;
     RECT  2.4 66.969 2.52 66.983 ;
     RECT  7.8 66.969 7.92 66.983 ;
     RECT  13.2 66.969 13.32 66.983 ;
     RECT  51 66.969 51.12 66.983 ;
     RECT  56.4 66.969 56.52 66.983 ;
     RECT  61.8 66.969 61.92 66.983 ;
     RECT  17.808 66.805 49.128 68.389 ;
     RECT  17.712 68.389 49.128 69.072 ;
  END
END ot_hbm_host_cfg_leaf2
END LIBRARY
